VERSION 5.8 ;
BUSBITCHARS "[]" ;
DIVIDERCHAR "/" ;
UNITS
    DATABASE MICRONS 1000 ;
END UNITS

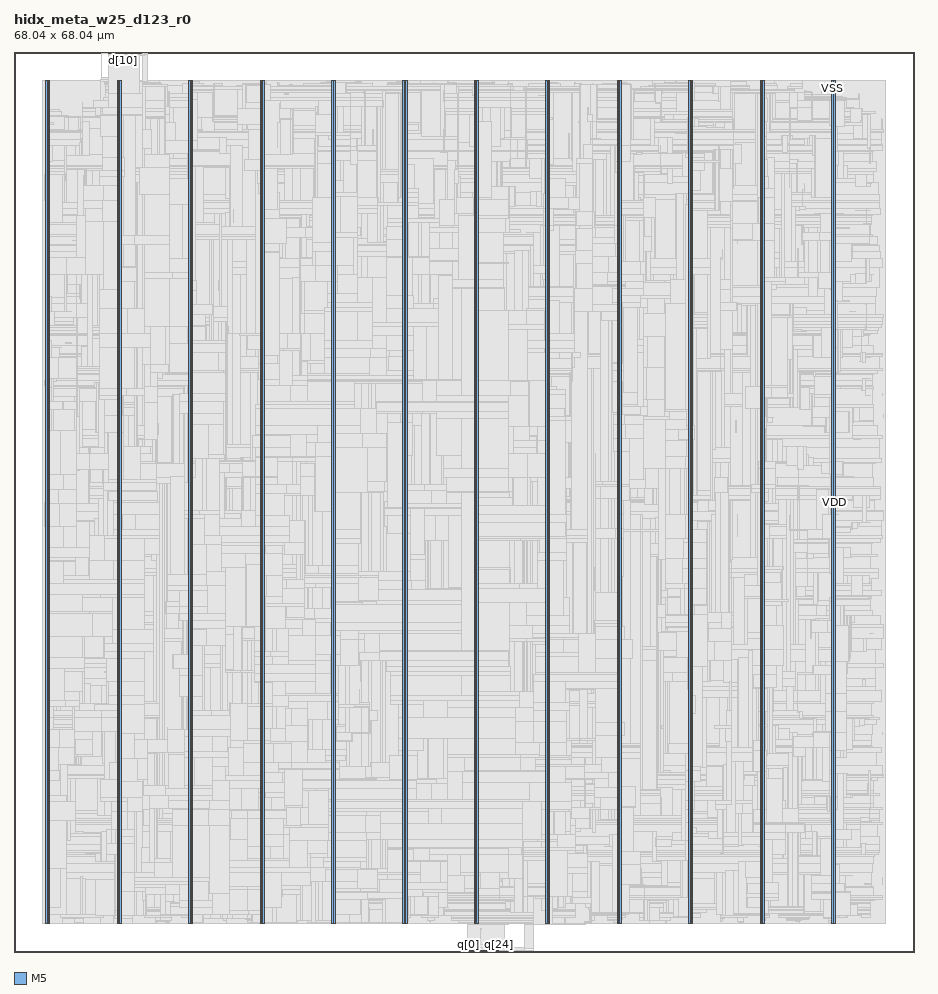
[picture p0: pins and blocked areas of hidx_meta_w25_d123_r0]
MACRO hidx_meta_w25_d123_r0
  FOREIGN hidx_meta_w25_d123_r0 0 0 ;
  CLASS BLOCK ;
  SIZE 68.04 BY 68.04 ;
  PIN clk
    DIRECTION INPUT ;
    USE SIGNAL ;
    PORT
      LAYER M5 ;
        RECT  7.152 67.956 7.176 68.04 ;
    END
  END clk
  PIN d[0]
    DIRECTION INPUT ;
    USE SIGNAL ;
    PORT
      LAYER M5 ;
        RECT  7.248 67.956 7.272 68.04 ;
    END
  END d[0]
  PIN d[10]
    DIRECTION INPUT ;
    USE SIGNAL ;
    PORT
      LAYER M5 ;
        RECT  8.208 67.956 8.232 68.04 ;
    END
  END d[10]
  PIN d[11]
    DIRECTION INPUT ;
    USE SIGNAL ;
    PORT
      LAYER M5 ;
        RECT  8.304 67.956 8.328 68.04 ;
    END
  END d[11]
  PIN d[12]
    DIRECTION INPUT ;
    USE SIGNAL ;
    PORT
      LAYER M5 ;
        RECT  8.4 67.956 8.424 68.04 ;
    END
  END d[12]
  PIN d[13]
    DIRECTION INPUT ;
    USE SIGNAL ;
    PORT
      LAYER M5 ;
        RECT  8.496 67.956 8.52 68.04 ;
    END
  END d[13]
  PIN d[14]
    DIRECTION INPUT ;
    USE SIGNAL ;
    PORT
      LAYER M5 ;
        RECT  8.592 67.956 8.616 68.04 ;
    END
  END d[14]
  PIN d[15]
    DIRECTION INPUT ;
    USE SIGNAL ;
    PORT
      LAYER M5 ;
        RECT  8.688 67.956 8.712 68.04 ;
    END
  END d[15]
  PIN d[16]
    DIRECTION INPUT ;
    USE SIGNAL ;
    PORT
      LAYER M5 ;
        RECT  8.784 67.956 8.808 68.04 ;
    END
  END d[16]
  PIN d[17]
    DIRECTION INPUT ;
    USE SIGNAL ;
    PORT
      LAYER M5 ;
        RECT  8.88 67.956 8.904 68.04 ;
    END
  END d[17]
  PIN d[18]
    DIRECTION INPUT ;
    USE SIGNAL ;
    PORT
      LAYER M5 ;
        RECT  8.976 67.956 9 68.04 ;
    END
  END d[18]
  PIN d[19]
    DIRECTION INPUT ;
    USE SIGNAL ;
    PORT
      LAYER M5 ;
        RECT  9.072 67.956 9.096 68.04 ;
    END
  END d[19]
  PIN d[1]
    DIRECTION INPUT ;
    USE SIGNAL ;
    PORT
      LAYER M5 ;
        RECT  7.344 67.956 7.368 68.04 ;
    END
  END d[1]
  PIN d[20]
    DIRECTION INPUT ;
    USE SIGNAL ;
    PORT
      LAYER M5 ;
        RECT  9.168 67.956 9.192 68.04 ;
    END
  END d[20]
  PIN d[21]
    DIRECTION INPUT ;
    USE SIGNAL ;
    PORT
      LAYER M5 ;
        RECT  9.264 67.956 9.288 68.04 ;
    END
  END d[21]
  PIN d[22]
    DIRECTION INPUT ;
    USE SIGNAL ;
    PORT
      LAYER M5 ;
        RECT  9.36 67.956 9.384 68.04 ;
    END
  END d[22]
  PIN d[23]
    DIRECTION INPUT ;
    USE SIGNAL ;
    PORT
      LAYER M5 ;
        RECT  9.456 67.956 9.48 68.04 ;
    END
  END d[23]
  PIN d[24]
    DIRECTION INPUT ;
    USE SIGNAL ;
    PORT
      LAYER M5 ;
        RECT  9.552 67.956 9.576 68.04 ;
    END
  END d[24]
  PIN d[2]
    DIRECTION INPUT ;
    USE SIGNAL ;
    PORT
      LAYER M5 ;
        RECT  7.44 67.956 7.464 68.04 ;
    END
  END d[2]
  PIN d[3]
    DIRECTION INPUT ;
    USE SIGNAL ;
    PORT
      LAYER M5 ;
        RECT  7.536 67.956 7.56 68.04 ;
    END
  END d[3]
  PIN d[4]
    DIRECTION INPUT ;
    USE SIGNAL ;
    PORT
      LAYER M5 ;
        RECT  7.632 67.956 7.656 68.04 ;
    END
  END d[4]
  PIN d[5]
    DIRECTION INPUT ;
    USE SIGNAL ;
    PORT
      LAYER M5 ;
        RECT  7.728 67.956 7.752 68.04 ;
    END
  END d[5]
  PIN d[6]
    DIRECTION INPUT ;
    USE SIGNAL ;
    PORT
      LAYER M5 ;
        RECT  7.824 67.956 7.848 68.04 ;
    END
  END d[6]
  PIN d[7]
    DIRECTION INPUT ;
    USE SIGNAL ;
    PORT
      LAYER M5 ;
        RECT  7.92 67.956 7.944 68.04 ;
    END
  END d[7]
  PIN d[8]
    DIRECTION INPUT ;
    USE SIGNAL ;
    PORT
      LAYER M5 ;
        RECT  8.016 67.956 8.04 68.04 ;
    END
  END d[8]
  PIN d[9]
    DIRECTION INPUT ;
    USE SIGNAL ;
    PORT
      LAYER M5 ;
        RECT  8.112 67.956 8.136 68.04 ;
    END
  END d[9]
  PIN q[0]
    DIRECTION OUTPUT ;
    USE SIGNAL ;
    PORT
      LAYER M5 ;
        RECT  34.32 0 34.344 0.084 ;
    END
  END q[0]
  PIN q[10]
    DIRECTION OUTPUT ;
    USE SIGNAL ;
    PORT
      LAYER M5 ;
        RECT  35.28 0 35.304 0.084 ;
    END
  END q[10]
  PIN q[11]
    DIRECTION OUTPUT ;
    USE SIGNAL ;
    PORT
      LAYER M5 ;
        RECT  35.376 0 35.4 0.084 ;
    END
  END q[11]
  PIN q[12]
    DIRECTION OUTPUT ;
    USE SIGNAL ;
    PORT
      LAYER M5 ;
        RECT  35.472 0 35.496 0.084 ;
    END
  END q[12]
  PIN q[13]
    DIRECTION OUTPUT ;
    USE SIGNAL ;
    PORT
      LAYER M5 ;
        RECT  35.568 0 35.592 0.084 ;
    END
  END q[13]
  PIN q[14]
    DIRECTION OUTPUT ;
    USE SIGNAL ;
    PORT
      LAYER M5 ;
        RECT  35.664 0 35.688 0.084 ;
    END
  END q[14]
  PIN q[15]
    DIRECTION OUTPUT ;
    USE SIGNAL ;
    PORT
      LAYER M5 ;
        RECT  35.76 0 35.784 0.084 ;
    END
  END q[15]
  PIN q[16]
    DIRECTION OUTPUT ;
    USE SIGNAL ;
    PORT
      LAYER M5 ;
        RECT  35.856 0 35.88 0.084 ;
    END
  END q[16]
  PIN q[17]
    DIRECTION OUTPUT ;
    USE SIGNAL ;
    PORT
      LAYER M5 ;
        RECT  35.952 0 35.976 0.084 ;
    END
  END q[17]
  PIN q[18]
    DIRECTION OUTPUT ;
    USE SIGNAL ;
    PORT
      LAYER M5 ;
        RECT  36.048 0 36.072 0.084 ;
    END
  END q[18]
  PIN q[19]
    DIRECTION OUTPUT ;
    USE SIGNAL ;
    PORT
      LAYER M5 ;
        RECT  36.144 0 36.168 0.084 ;
    END
  END q[19]
  PIN q[1]
    DIRECTION OUTPUT ;
    USE SIGNAL ;
    PORT
      LAYER M5 ;
        RECT  34.416 0 34.44 0.084 ;
    END
  END q[1]
  PIN q[20]
    DIRECTION OUTPUT ;
    USE SIGNAL ;
    PORT
      LAYER M5 ;
        RECT  36.24 0 36.264 0.084 ;
    END
  END q[20]
  PIN q[21]
    DIRECTION OUTPUT ;
    USE SIGNAL ;
    PORT
      LAYER M5 ;
        RECT  36.336 0 36.36 0.084 ;
    END
  END q[21]
  PIN q[22]
    DIRECTION OUTPUT ;
    USE SIGNAL ;
    PORT
      LAYER M5 ;
        RECT  36.432 0 36.456 0.084 ;
    END
  END q[22]
  PIN q[23]
    DIRECTION OUTPUT ;
    USE SIGNAL ;
    PORT
      LAYER M5 ;
        RECT  36.528 0 36.552 0.084 ;
    END
  END q[23]
  PIN q[24]
    DIRECTION OUTPUT ;
    USE SIGNAL ;
    PORT
      LAYER M5 ;
        RECT  36.624 0 36.648 0.084 ;
    END
  END q[24]
  PIN q[2]
    DIRECTION OUTPUT ;
    USE SIGNAL ;
    PORT
      LAYER M5 ;
        RECT  34.512 0 34.536 0.084 ;
    END
  END q[2]
  PIN q[3]
    DIRECTION OUTPUT ;
    USE SIGNAL ;
    PORT
      LAYER M5 ;
        RECT  34.608 0 34.632 0.084 ;
    END
  END q[3]
  PIN q[4]
    DIRECTION OUTPUT ;
    USE SIGNAL ;
    PORT
      LAYER M5 ;
        RECT  34.704 0 34.728 0.084 ;
    END
  END q[4]
  PIN q[5]
    DIRECTION OUTPUT ;
    USE SIGNAL ;
    PORT
      LAYER M5 ;
        RECT  34.8 0 34.824 0.084 ;
    END
  END q[5]
  PIN q[6]
    DIRECTION OUTPUT ;
    USE SIGNAL ;
    PORT
      LAYER M5 ;
        RECT  34.896 0 34.92 0.084 ;
    END
  END q[6]
  PIN q[7]
    DIRECTION OUTPUT ;
    USE SIGNAL ;
    PORT
      LAYER M5 ;
        RECT  34.992 0 35.016 0.084 ;
    END
  END q[7]
  PIN q[8]
    DIRECTION OUTPUT ;
    USE SIGNAL ;
    PORT
      LAYER M5 ;
        RECT  35.088 0 35.112 0.084 ;
    END
  END q[8]
  PIN q[9]
    DIRECTION OUTPUT ;
    USE SIGNAL ;
    PORT
      LAYER M5 ;
        RECT  35.184 0 35.208 0.084 ;
    END
  END q[9]
  PIN rst_n
    DIRECTION INPUT ;
    USE SIGNAL ;
    PORT
      LAYER M5 ;
        RECT  9.648 67.956 9.672 68.04 ;
    END
  END rst_n
  PIN VDD
    DIRECTION INOUT ;
    USE POWER ;
    PORT
      LAYER M5 ;
        RECT  61.992 2.151 62.112 65.889 ;
        RECT  56.592 2.151 56.712 65.889 ;
        RECT  51.192 2.151 51.312 65.889 ;
        RECT  45.792 2.151 45.912 65.889 ;
        RECT  40.392 2.151 40.512 65.889 ;
        RECT  34.992 2.151 35.112 65.889 ;
        RECT  29.592 2.151 29.712 65.889 ;
        RECT  24.192 2.151 24.312 65.889 ;
        RECT  18.792 2.151 18.912 65.889 ;
        RECT  13.392 2.151 13.512 65.889 ;
        RECT  7.992 2.151 8.112 65.889 ;
        RECT  2.592 2.151 2.712 65.889 ;
    END
  END VDD
  PIN VSS
    DIRECTION INOUT ;
    USE GROUND ;
    PORT
      LAYER M5 ;
        RECT  61.8 2.137 61.92 65.903 ;
        RECT  56.4 2.137 56.52 65.903 ;
        RECT  51 2.137 51.12 65.903 ;
        RECT  45.6 2.137 45.72 65.903 ;
        RECT  40.2 2.137 40.32 65.903 ;
        RECT  34.8 2.137 34.92 65.903 ;
        RECT  29.4 2.137 29.52 65.903 ;
        RECT  24 2.137 24.12 65.903 ;
        RECT  18.6 2.137 18.72 65.903 ;
        RECT  13.2 2.137 13.32 65.903 ;
        RECT  7.8 2.137 7.92 65.903 ;
        RECT  2.4 2.137 2.52 65.903 ;
    END
  END VSS
  # OT_OBS_CLOSED layer=M5 d_um=1.536 added=598
  OBS
    LAYER RVTN ;
     RECT  2.16 2.16 65.88 2.295 ;
     RECT  2.16 2.565 65.88 2.835 ;
     RECT  2.16 3.105 65.88 3.375 ;
     RECT  2.16 3.645 65.88 3.915 ;
     RECT  2.16 4.185 65.88 4.455 ;
     RECT  2.16 4.725 65.88 4.995 ;
     RECT  2.16 5.265 65.88 5.535 ;
     RECT  2.16 5.805 65.88 6.075 ;
     RECT  2.16 6.345 65.88 6.615 ;
     RECT  2.16 6.885 65.88 7.155 ;
     RECT  2.16 7.425 65.88 7.695 ;
     RECT  2.16 7.965 65.88 8.235 ;
     RECT  2.16 8.505 65.88 8.775 ;
     RECT  2.16 9.045 65.88 9.315 ;
     RECT  2.16 9.585 65.88 9.855 ;
     RECT  2.16 10.125 65.88 10.395 ;
     RECT  2.16 10.665 65.88 10.935 ;
     RECT  2.16 11.205 65.88 11.475 ;
     RECT  2.16 11.745 65.88 12.015 ;
     RECT  2.16 12.285 65.88 12.555 ;
     RECT  2.16 12.825 65.88 13.095 ;
     RECT  2.16 13.365 65.88 13.635 ;
     RECT  2.16 13.905 65.88 14.175 ;
     RECT  2.16 14.445 65.88 14.715 ;
     RECT  2.16 14.985 65.88 15.255 ;
     RECT  2.16 15.525 65.88 15.795 ;
     RECT  2.16 16.065 65.88 16.335 ;
     RECT  2.16 16.605 65.88 16.875 ;
     RECT  2.16 17.145 65.88 17.415 ;
     RECT  2.16 17.685 65.88 17.955 ;
     RECT  2.16 18.225 65.88 18.495 ;
     RECT  2.16 18.765 65.88 19.035 ;
     RECT  2.16 19.305 65.88 19.575 ;
     RECT  2.16 19.845 65.88 20.115 ;
     RECT  2.16 20.385 65.88 20.655 ;
     RECT  2.16 20.925 65.88 21.195 ;
     RECT  2.16 21.465 65.88 21.735 ;
     RECT  2.16 22.005 65.88 22.275 ;
     RECT  2.16 22.545 65.88 22.815 ;
     RECT  2.16 23.085 65.88 23.355 ;
     RECT  2.16 23.625 65.88 23.895 ;
     RECT  2.16 24.165 65.88 24.435 ;
     RECT  2.16 24.705 65.88 24.975 ;
     RECT  2.16 25.245 65.88 25.515 ;
     RECT  2.16 25.785 65.88 26.055 ;
     RECT  2.16 26.325 65.88 26.595 ;
     RECT  2.16 26.865 65.88 27.135 ;
     RECT  2.16 27.405 65.88 27.675 ;
     RECT  2.16 27.945 65.88 28.215 ;
     RECT  2.16 28.485 65.88 28.755 ;
     RECT  2.16 29.025 65.88 29.295 ;
     RECT  2.16 29.565 65.88 29.835 ;
     RECT  2.16 30.105 65.88 30.375 ;
     RECT  2.16 30.645 65.88 30.915 ;
     RECT  2.16 31.185 65.88 31.455 ;
     RECT  2.16 31.725 65.88 31.995 ;
     RECT  2.16 32.265 65.88 32.535 ;
     RECT  2.16 32.805 65.88 33.075 ;
     RECT  2.16 33.345 65.88 33.615 ;
     RECT  2.16 33.885 65.88 34.155 ;
     RECT  2.16 34.425 65.88 34.695 ;
     RECT  2.16 34.965 65.88 35.235 ;
     RECT  2.16 35.505 65.88 35.775 ;
     RECT  2.16 36.045 65.88 36.315 ;
     RECT  2.16 36.585 65.88 36.855 ;
     RECT  2.16 37.125 65.88 37.395 ;
     RECT  2.16 37.665 65.88 37.935 ;
     RECT  2.16 38.205 65.88 38.475 ;
     RECT  2.16 38.745 65.88 39.015 ;
     RECT  2.16 39.285 65.88 39.555 ;
     RECT  2.16 39.825 65.88 40.095 ;
     RECT  2.16 40.365 65.88 40.635 ;
     RECT  2.16 40.905 65.88 41.175 ;
     RECT  2.16 41.445 65.88 41.715 ;
     RECT  2.16 41.985 65.88 42.255 ;
     RECT  2.16 42.525 65.88 42.795 ;
     RECT  2.16 43.065 65.88 43.335 ;
     RECT  2.16 43.605 65.88 43.875 ;
     RECT  2.16 44.145 65.88 44.415 ;
     RECT  2.16 44.685 65.88 44.955 ;
     RECT  2.16 45.225 65.88 45.495 ;
     RECT  2.16 45.765 65.88 46.035 ;
     RECT  2.16 46.305 65.88 46.575 ;
     RECT  2.16 46.845 65.88 47.115 ;
     RECT  2.16 47.385 65.88 47.655 ;
     RECT  2.16 47.925 65.88 48.195 ;
     RECT  2.16 48.465 65.88 48.735 ;
     RECT  2.16 49.005 65.88 49.275 ;
     RECT  2.16 49.545 65.88 49.815 ;
     RECT  2.16 50.085 65.88 50.355 ;
     RECT  2.16 50.625 65.88 50.895 ;
     RECT  2.16 51.165 65.88 51.435 ;
     RECT  2.16 51.705 65.88 51.975 ;
     RECT  2.16 52.245 65.88 52.515 ;
     RECT  2.16 52.785 65.88 53.055 ;
     RECT  2.16 53.325 65.88 53.595 ;
     RECT  2.16 53.865 65.88 54.135 ;
     RECT  2.16 54.405 65.88 54.675 ;
     RECT  2.16 54.945 65.88 55.215 ;
     RECT  2.16 55.485 65.88 55.755 ;
     RECT  2.16 56.025 65.88 56.295 ;
     RECT  2.16 56.565 65.88 56.835 ;
     RECT  2.16 57.105 65.88 57.375 ;
     RECT  2.16 57.645 65.88 57.915 ;
     RECT  2.16 58.185 65.88 58.455 ;
     RECT  2.16 58.725 65.88 58.995 ;
     RECT  2.16 59.265 65.88 59.535 ;
     RECT  2.16 59.805 65.88 60.075 ;
     RECT  2.16 60.345 65.88 60.615 ;
     RECT  2.16 60.885 65.88 61.155 ;
     RECT  2.16 61.425 65.88 61.695 ;
     RECT  2.16 61.965 65.88 62.235 ;
     RECT  2.16 62.505 65.88 62.775 ;
     RECT  2.16 63.045 65.88 63.315 ;
     RECT  2.16 63.585 65.88 63.855 ;
     RECT  2.16 64.125 65.88 64.395 ;
     RECT  2.16 64.665 65.88 64.935 ;
     RECT  2.16 65.205 65.88 65.475 ;
     RECT  2.16 65.745 65.88 65.88 ;
    LAYER RVTP ;
     RECT  2.16 2.295 65.88 2.565 ;
     RECT  2.16 2.835 65.88 3.105 ;
     RECT  2.16 3.375 65.88 3.645 ;
     RECT  2.16 3.915 65.88 4.185 ;
     RECT  2.16 4.455 65.88 4.725 ;
     RECT  2.16 4.995 65.88 5.265 ;
     RECT  2.16 5.535 65.88 5.805 ;
     RECT  2.16 6.075 65.88 6.345 ;
     RECT  2.16 6.615 65.88 6.885 ;
     RECT  2.16 7.155 65.88 7.425 ;
     RECT  2.16 7.695 65.88 7.965 ;
     RECT  2.16 8.235 65.88 8.505 ;
     RECT  2.16 8.775 65.88 9.045 ;
     RECT  2.16 9.315 65.88 9.585 ;
     RECT  2.16 9.855 65.88 10.125 ;
     RECT  2.16 10.395 65.88 10.665 ;
     RECT  2.16 10.935 65.88 11.205 ;
     RECT  2.16 11.475 65.88 11.745 ;
     RECT  2.16 12.015 65.88 12.285 ;
     RECT  2.16 12.555 65.88 12.825 ;
     RECT  2.16 13.095 65.88 13.365 ;
     RECT  2.16 13.635 65.88 13.905 ;
     RECT  2.16 14.175 65.88 14.445 ;
     RECT  2.16 14.715 65.88 14.985 ;
     RECT  2.16 15.255 65.88 15.525 ;
     RECT  2.16 15.795 65.88 16.065 ;
     RECT  2.16 16.335 65.88 16.605 ;
     RECT  2.16 16.875 65.88 17.145 ;
     RECT  2.16 17.415 65.88 17.685 ;
     RECT  2.16 17.955 65.88 18.225 ;
     RECT  2.16 18.495 65.88 18.765 ;
     RECT  2.16 19.035 65.88 19.305 ;
     RECT  2.16 19.575 65.88 19.845 ;
     RECT  2.16 20.115 65.88 20.385 ;
     RECT  2.16 20.655 65.88 20.925 ;
     RECT  2.16 21.195 65.88 21.465 ;
     RECT  2.16 21.735 65.88 22.005 ;
     RECT  2.16 22.275 65.88 22.545 ;
     RECT  2.16 22.815 65.88 23.085 ;
     RECT  2.16 23.355 65.88 23.625 ;
     RECT  2.16 23.895 65.88 24.165 ;
     RECT  2.16 24.435 65.88 24.705 ;
     RECT  2.16 24.975 65.88 25.245 ;
     RECT  2.16 25.515 65.88 25.785 ;
     RECT  2.16 26.055 65.88 26.325 ;
     RECT  2.16 26.595 65.88 26.865 ;
     RECT  2.16 27.135 65.88 27.405 ;
     RECT  2.16 27.675 65.88 27.945 ;
     RECT  2.16 28.215 65.88 28.485 ;
     RECT  2.16 28.755 65.88 29.025 ;
     RECT  2.16 29.295 65.88 29.565 ;
     RECT  2.16 29.835 65.88 30.105 ;
     RECT  2.16 30.375 65.88 30.645 ;
     RECT  2.16 30.915 65.88 31.185 ;
     RECT  2.16 31.455 65.88 31.725 ;
     RECT  2.16 31.995 65.88 32.265 ;
     RECT  2.16 32.535 65.88 32.805 ;
     RECT  2.16 33.075 65.88 33.345 ;
     RECT  2.16 33.615 65.88 33.885 ;
     RECT  2.16 34.155 65.88 34.425 ;
     RECT  2.16 34.695 65.88 34.965 ;
     RECT  2.16 35.235 65.88 35.505 ;
     RECT  2.16 35.775 65.88 36.045 ;
     RECT  2.16 36.315 65.88 36.585 ;
     RECT  2.16 36.855 65.88 37.125 ;
     RECT  2.16 37.395 65.88 37.665 ;
     RECT  2.16 37.935 65.88 38.205 ;
     RECT  2.16 38.475 65.88 38.745 ;
     RECT  2.16 39.015 65.88 39.285 ;
     RECT  2.16 39.555 65.88 39.825 ;
     RECT  2.16 40.095 65.88 40.365 ;
     RECT  2.16 40.635 65.88 40.905 ;
     RECT  2.16 41.175 65.88 41.445 ;
     RECT  2.16 41.715 65.88 41.985 ;
     RECT  2.16 42.255 65.88 42.525 ;
     RECT  2.16 42.795 65.88 43.065 ;
     RECT  2.16 43.335 65.88 43.605 ;
     RECT  2.16 43.875 65.88 44.145 ;
     RECT  2.16 44.415 65.88 44.685 ;
     RECT  2.16 44.955 65.88 45.225 ;
     RECT  2.16 45.495 65.88 45.765 ;
     RECT  2.16 46.035 65.88 46.305 ;
     RECT  2.16 46.575 65.88 46.845 ;
     RECT  2.16 47.115 65.88 47.385 ;
     RECT  2.16 47.655 65.88 47.925 ;
     RECT  2.16 48.195 65.88 48.465 ;
     RECT  2.16 48.735 65.88 49.005 ;
     RECT  2.16 49.275 65.88 49.545 ;
     RECT  2.16 49.815 65.88 50.085 ;
     RECT  2.16 50.355 65.88 50.625 ;
     RECT  2.16 50.895 65.88 51.165 ;
     RECT  2.16 51.435 65.88 51.705 ;
     RECT  2.16 51.975 65.88 52.245 ;
     RECT  2.16 52.515 65.88 52.785 ;
     RECT  2.16 53.055 65.88 53.325 ;
     RECT  2.16 53.595 65.88 53.865 ;
     RECT  2.16 54.135 65.88 54.405 ;
     RECT  2.16 54.675 65.88 54.945 ;
     RECT  2.16 55.215 65.88 55.485 ;
     RECT  2.16 55.755 65.88 56.025 ;
     RECT  2.16 56.295 65.88 56.565 ;
     RECT  2.16 56.835 65.88 57.105 ;
     RECT  2.16 57.375 65.88 57.645 ;
     RECT  2.16 57.915 65.88 58.185 ;
     RECT  2.16 58.455 65.88 58.725 ;
     RECT  2.16 58.995 65.88 59.265 ;
     RECT  2.16 59.535 65.88 59.805 ;
     RECT  2.16 60.075 65.88 60.345 ;
     RECT  2.16 60.615 65.88 60.885 ;
     RECT  2.16 61.155 65.88 61.425 ;
     RECT  2.16 61.695 65.88 61.965 ;
     RECT  2.16 62.235 65.88 62.505 ;
     RECT  2.16 62.775 65.88 63.045 ;
     RECT  2.16 63.315 65.88 63.585 ;
     RECT  2.16 63.855 65.88 64.125 ;
     RECT  2.16 64.395 65.88 64.665 ;
     RECT  2.16 64.935 65.88 65.205 ;
     RECT  2.16 65.475 65.88 65.745 ;
    LAYER M1 ;
     RECT  2.16 2.151 65.88 65.889 ;
    LAYER M2 ;
     RECT  2.16 2.151 6.547 65.889 ;
     RECT  6.547 2.151 7.511 65.934 ;
     RECT  34.447 0.531 34.547 0.549 ;
     RECT  7.511 2.151 36.211 65.889 ;
     RECT  36.211 2.106 37.355 65.889 ;
     RECT  37.355 2.151 65.88 65.889 ;
    LAYER M3 ;
     RECT  34.344 0.091 36.27 0.187 ;
     RECT  37.044 0.139 37.062 0.187 ;
     RECT  39.24 0.091 39.258 0.283 ;
     RECT  34.344 0.187 37.062 0.475 ;
     RECT  38.592 0.283 39.258 2.059 ;
     RECT  34.308 0.475 37.062 2.101 ;
     RECT  7.815 2.143 7.905 2.191 ;
     RECT  18.615 2.143 18.705 2.191 ;
     RECT  34.308 2.101 37.35 2.191 ;
     RECT  38.592 2.059 39.33 2.191 ;
     RECT  40.215 2.143 40.305 2.191 ;
     RECT  43.164 2.059 43.182 2.191 ;
     RECT  5.256 2.191 5.274 2.227 ;
     RECT  11.736 2.191 11.754 2.227 ;
     RECT  22.68 2.191 22.698 2.227 ;
     RECT  24.015 2.143 24.105 2.227 ;
     RECT  38.592 2.191 40.305 2.227 ;
     RECT  45.615 2.143 45.705 2.227 ;
     RECT  13.215 2.143 13.305 2.251 ;
     RECT  21.42 2.227 21.438 2.251 ;
     RECT  22.212 2.227 22.698 2.251 ;
     RECT  23.508 2.227 24.105 2.251 ;
     RECT  18.036 2.191 18.705 2.263 ;
     RECT  21.312 2.251 21.438 2.263 ;
     RECT  25.092 2.251 25.11 2.263 ;
     RECT  26.676 2.251 26.694 2.263 ;
     RECT  27.576 2.251 27.594 2.263 ;
     RECT  33.624 2.191 37.35 2.263 ;
     RECT  38.556 2.227 40.305 2.263 ;
     RECT  61.815 2.143 61.905 2.263 ;
     RECT  43.164 2.191 43.578 2.291 ;
     RECT  10.728 2.227 10.746 2.299 ;
     RECT  11.484 2.227 11.754 2.299 ;
     RECT  13.215 2.251 13.842 2.299 ;
     RECT  26.676 2.263 27.738 2.335 ;
     RECT  29.415 2.143 29.505 2.335 ;
     RECT  31.5 2.263 31.518 2.335 ;
     RECT  54.792 2.227 55.17 2.335 ;
     RECT  59.4 2.263 59.418 2.335 ;
     RECT  10.728 2.299 11.754 2.371 ;
     RECT  16.056 2.263 16.074 2.371 ;
     RECT  17.676 2.263 19.314 2.371 ;
     RECT  26.676 2.335 27.846 2.371 ;
     RECT  31.428 2.335 31.518 2.371 ;
     RECT  33.624 2.263 40.305 2.371 ;
     RECT  41.652 2.263 41.67 2.371 ;
     RECT  43.488 2.291 43.578 2.371 ;
     RECT  45.324 2.227 45.705 2.371 ;
     RECT  48.06 2.191 48.078 2.371 ;
     RECT  49.284 2.191 49.302 2.371 ;
     RECT  56.415 2.143 56.505 2.371 ;
     RECT  59.112 2.335 59.418 2.371 ;
     RECT  2.415 2.143 2.505 2.413 ;
     RECT  22.212 2.251 24.105 2.413 ;
     RECT  24.912 2.263 25.182 2.413 ;
     RECT  33.084 2.371 40.305 2.413 ;
     RECT  44.892 2.371 45.705 2.413 ;
     RECT  51.015 2.143 51.105 2.413 ;
     RECT  61.56 2.263 61.974 2.413 ;
     RECT  13.215 2.299 14.202 2.461 ;
     RECT  17.676 2.371 19.53 2.461 ;
     RECT  20.268 2.371 20.286 2.461 ;
     RECT  21.132 2.263 21.438 2.461 ;
     RECT  26.208 2.371 27.846 2.461 ;
     RECT  44.892 2.413 45.897 2.461 ;
     RECT  58.392 2.371 59.562 2.461 ;
     RECT  17.676 2.461 21.438 2.488 ;
     RECT  58.392 2.461 60.102 2.497 ;
     RECT  61.56 2.413 62.097 2.497 ;
     RECT  3.636 2.191 3.654 2.533 ;
     RECT  4.572 2.227 5.274 2.533 ;
     RECT  7.815 2.191 8.982 2.533 ;
     RECT  15.84 2.371 16.074 2.533 ;
     RECT  53.424 2.335 53.55 2.533 ;
     RECT  17.496 2.488 21.438 2.569 ;
     RECT  33.084 2.413 40.497 2.569 ;
     RECT  61.2 2.497 62.097 2.587 ;
     RECT  13.176 2.461 14.202 2.605 ;
     RECT  15.732 2.533 16.074 2.605 ;
     RECT  17.424 2.569 21.438 2.605 ;
     RECT  22.212 2.413 25.182 2.605 ;
     RECT  26.172 2.461 27.846 2.605 ;
     RECT  31.284 2.371 31.77 2.605 ;
     RECT  33.048 2.569 40.497 2.605 ;
     RECT  41.616 2.371 41.67 2.605 ;
     RECT  47.304 2.371 49.626 2.605 ;
     RECT  51.015 2.413 51.297 2.605 ;
     RECT  53.424 2.533 53.73 2.605 ;
     RECT  54.684 2.335 55.17 2.605 ;
     RECT  56.415 2.371 56.79 2.605 ;
     RECT  58.392 2.497 60.174 2.605 ;
     RECT  3.636 2.533 5.274 2.641 ;
     RECT  6.732 2.605 6.75 2.641 ;
     RECT  9.9 2.605 9.918 2.641 ;
     RECT  10.728 2.371 11.934 2.641 ;
     RECT  15.732 2.605 16.182 2.641 ;
     RECT  17.424 2.605 25.182 2.641 ;
     RECT  26.1 2.605 27.846 2.641 ;
     RECT  29.415 2.335 29.79 2.641 ;
     RECT  31.284 2.605 32.058 2.641 ;
     RECT  33.048 2.605 40.662 2.641 ;
     RECT  41.436 2.605 41.742 2.641 ;
     RECT  44.892 2.461 45.99 2.641 ;
     RECT  47.304 2.605 50.058 2.641 ;
     RECT  51.015 2.605 51.93 2.641 ;
     RECT  53.424 2.605 55.17 2.641 ;
     RECT  56.415 2.605 56.898 2.641 ;
     RECT  58.284 2.605 60.174 2.641 ;
     RECT  61.2 2.587 62.262 2.641 ;
     RECT  63 2.587 63.018 2.641 ;
     RECT  64.044 2.605 64.062 2.641 ;
     RECT  30.78 2.641 32.058 2.731 ;
     RECT  33.048 2.641 42.426 2.731 ;
     RECT  43.488 2.371 43.902 2.731 ;
     RECT  44.856 2.641 46.206 2.731 ;
     RECT  53.424 2.641 55.458 2.731 ;
     RECT  56.415 2.641 57.078 2.731 ;
     RECT  57.816 2.641 60.174 2.731 ;
     RECT  61.2 2.641 63.018 2.731 ;
     RECT  9.9 2.641 11.934 2.767 ;
     RECT  12.672 2.605 14.742 2.767 ;
     RECT  15.48 2.641 16.326 2.767 ;
     RECT  17.424 2.641 27.846 2.767 ;
     RECT  29.376 2.641 30.006 2.767 ;
     RECT  30.78 2.731 42.426 2.767 ;
     RECT  2.415 2.413 2.697 2.803 ;
     RECT  3.492 2.641 6.75 2.803 ;
     RECT  43.488 2.731 46.206 2.803 ;
     RECT  53.424 2.731 57.078 2.803 ;
     RECT  57.816 2.731 63.018 2.803 ;
     RECT  64.044 2.641 64.746 2.803 ;
     RECT  2.415 2.803 6.75 2.911 ;
     RECT  7.632 2.533 8.982 2.911 ;
     RECT  43.488 2.803 46.422 2.911 ;
     RECT  47.304 2.641 51.93 2.911 ;
     RECT  53.1 2.803 57.078 2.911 ;
     RECT  57.816 2.803 64.746 2.911 ;
     RECT  43.488 2.911 51.93 3.001 ;
     RECT  7.632 2.911 9.09 3.037 ;
     RECT  9.9 2.767 16.326 3.037 ;
     RECT  17.424 2.767 28.458 3.037 ;
     RECT  17.172 3.037 28.458 3.064 ;
     RECT  29.196 2.767 42.426 3.064 ;
     RECT  7.632 3.037 16.326 3.145 ;
     RECT  17.172 3.064 42.426 3.145 ;
     RECT  53.1 2.911 64.746 3.145 ;
     RECT  2.415 2.911 6.894 3.181 ;
     RECT  7.632 3.145 42.426 3.181 ;
     RECT  43.488 3.001 52.362 3.181 ;
     RECT  53.1 3.145 64.782 3.181 ;
     RECT  43.452 3.181 64.782 3.379 ;
     RECT  2.415 3.181 42.426 3.685 ;
     RECT  43.236 3.379 64.782 3.685 ;
     RECT  2.415 3.685 64.782 3.749 ;
     RECT  2.415 3.749 12.114 3.839 ;
     RECT  12.888 3.749 64.782 3.883 ;
     RECT  12.888 3.883 65.034 3.991 ;
     RECT  12.888 3.991 65.682 4.109 ;
     RECT  13.032 4.109 65.682 4.253 ;
     RECT  2.415 3.839 12.078 4.891 ;
     RECT  13.032 4.253 64.998 4.891 ;
     RECT  2.415 4.891 64.998 4.919 ;
     RECT  65.664 5.071 65.682 5.603 ;
     RECT  2.415 4.919 64.854 6.043 ;
     RECT  2.415 6.043 64.89 6.691 ;
     RECT  2.415 6.691 64.998 7.231 ;
     RECT  2.415 7.231 65.034 7.393 ;
     RECT  2.415 7.393 65.358 7.501 ;
     RECT  2.415 7.501 65.43 7.699 ;
     RECT  2.415 7.699 65.466 8.159 ;
     RECT  2.415 8.159 65.43 8.699 ;
     RECT  2.415 8.699 65.25 8.735 ;
     RECT  60.3 8.735 65.25 9.625 ;
     RECT  2.415 8.735 59.526 9.643 ;
     RECT  60.264 9.625 65.25 9.643 ;
     RECT  2.415 9.643 65.25 9.661 ;
     RECT  2.415 9.661 65.682 9.815 ;
     RECT  2.415 9.815 65.466 9.931 ;
     RECT  2.376 9.931 65.466 10.109 ;
     RECT  2.415 10.109 65.466 10.445 ;
     RECT  55.872 10.445 65.466 10.741 ;
     RECT  55.872 10.741 65.682 10.931 ;
     RECT  2.415 10.445 55.098 11.209 ;
     RECT  55.872 10.931 64.962 11.209 ;
     RECT  2.415 11.209 64.962 11.821 ;
     RECT  2.415 11.821 65.43 11.975 ;
     RECT  2.415 11.975 64.998 12.209 ;
     RECT  2.415 12.209 55.17 12.631 ;
     RECT  55.98 12.209 64.998 12.991 ;
     RECT  2.376 12.631 55.17 13.063 ;
     RECT  55.98 12.991 65.286 13.171 ;
     RECT  2.376 13.063 55.206 13.369 ;
     RECT  55.98 13.171 65.754 13.369 ;
     RECT  2.376 13.369 65.754 13.433 ;
     RECT  2.376 13.433 65.646 14.099 ;
     RECT  2.415 14.099 65.574 14.135 ;
     RECT  2.415 14.135 65.178 15.061 ;
     RECT  2.415 15.061 65.574 15.448 ;
     RECT  2.412 15.448 65.574 15.485 ;
     RECT  2.415 15.485 64.89 15.521 ;
     RECT  2.415 15.521 64.854 15.629 ;
     RECT  2.415 15.629 64.818 16.411 ;
     RECT  65.664 16.411 65.682 16.601 ;
     RECT  2.415 16.411 64.89 17.185 ;
     RECT  2.415 17.185 65.178 17.581 ;
     RECT  2.415 17.581 65.43 17.753 ;
     RECT  2.415 17.753 64.998 17.879 ;
     RECT  2.415 17.879 64.818 18.769 ;
     RECT  2.415 18.769 64.962 18.931 ;
     RECT  2.415 18.931 65.61 19.769 ;
     RECT  2.415 19.769 65.502 19.805 ;
     RECT  2.415 19.805 65.106 20.047 ;
     RECT  2.376 20.047 65.106 20.651 ;
     RECT  2.415 20.651 65.106 21.541 ;
     RECT  2.415 21.541 65.754 21.803 ;
     RECT  2.415 21.803 65.106 22.891 ;
     RECT  2.415 22.891 65.574 23.701 ;
     RECT  2.415 23.701 65.754 24.539 ;
     RECT  2.415 24.539 58.194 24.629 ;
     RECT  58.932 24.539 65.754 24.773 ;
     RECT  2.415 24.629 58.086 24.907 ;
     RECT  2.412 24.907 58.086 24.944 ;
     RECT  58.932 24.773 65.502 25.439 ;
     RECT  2.415 24.944 58.086 25.447 ;
     RECT  58.932 25.439 60.678 25.447 ;
     RECT  61.416 25.439 65.502 25.475 ;
     RECT  61.416 25.475 64.926 25.853 ;
     RECT  2.415 25.447 60.678 26.221 ;
     RECT  61.416 25.853 64.746 26.221 ;
     RECT  2.415 26.221 64.746 26.671 ;
     RECT  2.415 26.671 64.782 26.761 ;
     RECT  2.415 26.761 64.818 26.897 ;
     RECT  2.415 26.897 59.13 26.905 ;
     RECT  59.868 26.897 64.818 26.941 ;
     RECT  59.868 26.941 65.574 27.329 ;
     RECT  59.868 27.329 65.43 27.365 ;
     RECT  2.376 26.905 59.13 27.679 ;
     RECT  59.868 27.365 64.818 27.679 ;
     RECT  2.376 27.679 64.818 28.255 ;
     RECT  2.376 28.255 65.322 28.679 ;
     RECT  2.415 28.679 65.322 28.985 ;
     RECT  2.415 28.985 64.746 29.911 ;
     RECT  2.415 29.911 65.286 30.065 ;
     RECT  2.415 30.065 64.854 30.919 ;
     RECT  2.415 30.919 64.926 30.991 ;
     RECT  2.415 30.991 65.502 31.261 ;
     RECT  2.415 31.261 65.682 31.523 ;
     RECT  2.415 31.523 65.61 32.197 ;
     RECT  2.34 32.197 65.61 32.611 ;
     RECT  2.34 32.611 65.754 33.269 ;
     RECT  52.524 33.269 65.754 33.413 ;
     RECT  2.34 33.269 51.642 33.989 ;
     RECT  2.376 33.989 51.642 34.087 ;
     RECT  2.376 34.087 51.75 34.159 ;
     RECT  52.524 33.413 65.07 34.159 ;
     RECT  2.376 34.159 65.07 34.231 ;
     RECT  2.376 34.231 65.502 34.493 ;
     RECT  2.415 34.493 65.502 35.041 ;
     RECT  2.415 35.041 65.538 35.195 ;
     RECT  2.415 35.195 64.998 35.843 ;
     RECT  2.415 35.843 64.926 36.931 ;
     RECT  2.415 36.931 65.142 37.021 ;
     RECT  2.415 37.021 65.574 37.319 ;
     RECT  2.415 37.319 65.43 38.155 ;
     RECT  2.376 38.155 65.43 38.821 ;
     RECT  2.376 38.821 65.682 39.083 ;
     RECT  2.376 39.083 65.286 39.773 ;
     RECT  2.415 39.773 65.286 39.785 ;
     RECT  65.736 40.441 65.754 40.631 ;
     RECT  2.415 39.785 64.962 41.179 ;
     RECT  2.415 41.179 64.998 41.369 ;
     RECT  65.664 42.061 65.682 42.251 ;
     RECT  2.415 41.369 64.926 42.565 ;
     RECT  2.376 42.565 64.926 42.601 ;
     RECT  2.376 42.601 64.962 42.719 ;
     RECT  2.376 42.719 64.926 42.835 ;
     RECT  2.304 42.835 64.926 43.169 ;
     RECT  2.376 43.169 64.926 43.681 ;
     RECT  2.376 43.681 64.998 43.771 ;
     RECT  2.376 43.771 65.25 43.951 ;
     RECT  2.376 43.951 65.682 44.141 ;
     RECT  2.376 44.141 65.466 45.031 ;
     RECT  2.376 45.031 65.682 45.149 ;
     RECT  2.415 45.149 65.682 45.221 ;
     RECT  2.415 45.221 64.998 45.833 ;
     RECT  2.415 45.833 64.566 46.579 ;
     RECT  2.415 46.579 64.674 46.651 ;
     RECT  2.415 46.651 64.746 46.741 ;
     RECT  2.415 46.741 65.286 47.011 ;
     RECT  2.415 47.011 65.358 47.191 ;
     RECT  2.376 47.191 65.574 47.461 ;
     RECT  2.376 47.461 65.682 47.651 ;
     RECT  2.376 47.651 27.162 47.981 ;
     RECT  27.936 47.651 65.682 48.001 ;
     RECT  27.936 48.001 65.754 48.191 ;
     RECT  2.415 47.981 27.162 49.045 ;
     RECT  27.936 48.191 65.106 49.045 ;
     RECT  2.415 49.045 65.106 49.585 ;
     RECT  2.415 49.585 65.214 50.251 ;
     RECT  2.415 50.251 65.394 51.745 ;
     RECT  2.376 51.745 65.394 51.781 ;
     RECT  2.376 51.781 65.682 52.439 ;
     RECT  2.376 52.439 65.538 52.979 ;
     RECT  2.376 52.979 65.43 53.393 ;
     RECT  2.376 53.393 65.286 53.519 ;
     RECT  2.415 53.519 65.286 54.059 ;
     RECT  2.415 54.059 65.178 54.095 ;
     RECT  2.415 54.095 64.89 54.239 ;
     RECT  2.415 54.239 64.746 55.021 ;
     RECT  2.415 55.021 64.854 55.255 ;
     RECT  2.412 55.255 64.854 55.553 ;
     RECT  2.415 55.553 64.854 55.651 ;
     RECT  2.415 55.651 64.926 55.759 ;
     RECT  2.415 55.759 65.502 56.219 ;
     RECT  2.415 56.219 65.394 56.641 ;
     RECT  2.376 56.641 65.394 56.803 ;
     RECT  2.304 56.803 65.394 57.299 ;
     RECT  2.304 57.299 65.358 58.145 ;
     RECT  2.304 58.145 64.998 58.793 ;
     RECT  2.376 58.793 64.998 59.035 ;
     RECT  2.376 59.035 65.178 59.225 ;
     RECT  2.376 59.225 53.946 59.369 ;
     RECT  2.415 59.369 53.946 59.459 ;
     RECT  54.684 59.225 65.178 59.729 ;
     RECT  54.684 59.729 64.998 59.765 ;
     RECT  38.844 59.459 53.946 60.385 ;
     RECT  54.684 59.765 64.89 60.385 ;
     RECT  38.844 60.385 64.89 60.511 ;
     RECT  2.415 59.459 38.07 60.523 ;
     RECT  38.844 60.511 64.962 60.523 ;
     RECT  2.415 60.523 64.962 60.575 ;
     RECT  38.844 60.575 64.962 60.619 ;
     RECT  38.844 60.619 65.646 60.961 ;
     RECT  38.844 60.961 65.682 61.079 ;
     RECT  2.415 60.575 38.07 61.393 ;
     RECT  38.844 61.079 65.574 61.393 ;
     RECT  2.415 61.393 65.574 61.969 ;
     RECT  2.415 61.969 65.754 62.033 ;
     RECT  2.415 62.033 14.238 62.069 ;
     RECT  4.86 62.069 14.238 62.159 ;
     RECT  15.192 62.033 65.754 62.159 ;
     RECT  15.192 62.159 64.746 62.699 ;
     RECT  15.192 62.699 63.27 62.815 ;
     RECT  64.008 62.699 64.746 62.843 ;
     RECT  15.012 62.815 63.27 62.969 ;
     RECT  65.556 62.159 65.646 62.969 ;
     RECT  65.556 62.969 65.574 63.005 ;
     RECT  4.86 62.159 14.202 63.067 ;
     RECT  15.012 62.969 63.234 63.067 ;
     RECT  2.415 62.069 4.122 63.121 ;
     RECT  4.86 63.067 63.234 63.121 ;
     RECT  2.415 63.121 63.234 63.149 ;
     RECT  2.415 63.149 4.446 63.197 ;
     RECT  2.415 63.197 4.122 63.239 ;
     RECT  64.08 62.843 64.746 63.355 ;
     RECT  5.184 63.149 63.234 63.509 ;
     RECT  64.08 63.355 65.106 63.509 ;
     RECT  2.415 63.239 3.618 63.545 ;
     RECT  2.415 63.545 3.402 63.689 ;
     RECT  51.015 63.509 60.606 63.689 ;
     RECT  61.524 63.509 63.234 63.751 ;
     RECT  64.08 63.509 64.17 63.751 ;
     RECT  5.184 63.509 50.094 63.779 ;
     RECT  61.524 63.751 64.17 63.779 ;
     RECT  5.184 63.779 5.202 64.193 ;
     RECT  5.976 63.779 50.094 64.355 ;
     RECT  51.015 63.689 60.462 64.391 ;
     RECT  59.796 64.391 60.462 64.471 ;
     RECT  61.524 63.779 63.954 64.471 ;
     RECT  59.796 64.471 63.954 64.499 ;
     RECT  6.732 64.355 50.094 64.625 ;
     RECT  59.796 64.499 62.91 64.625 ;
     RECT  59.796 64.625 62.622 64.697 ;
     RECT  59.796 64.697 62.097 64.859 ;
     RECT  63.828 64.499 63.954 64.859 ;
     RECT  63.828 64.859 63.846 64.895 ;
     RECT  6.912 64.625 50.094 64.975 ;
     RECT  51.015 64.391 59.022 64.975 ;
     RECT  59.796 64.859 60.318 65.021 ;
     RECT  6.912 64.975 59.022 65.129 ;
     RECT  59.796 65.021 59.886 65.129 ;
     RECT  61.056 64.859 62.097 65.129 ;
     RECT  59.796 65.129 59.814 65.165 ;
     RECT  61.056 65.129 61.074 65.165 ;
     RECT  6.912 65.129 37.782 65.201 ;
     RECT  38.556 65.129 59.022 65.201 ;
     RECT  12.564 65.201 37.782 65.237 ;
     RECT  38.556 65.201 57.69 65.237 ;
     RECT  58.5 65.201 59.022 65.245 ;
     RECT  38.556 65.237 55.638 65.273 ;
     RECT  38.556 65.273 46.602 65.309 ;
     RECT  6.912 65.201 11.754 65.399 ;
     RECT  12.564 65.237 24.297 65.399 ;
     RECT  25.02 65.237 37.782 65.399 ;
     RECT  38.556 65.309 42.93 65.399 ;
     RECT  47.376 65.273 55.602 65.399 ;
     RECT  47.952 65.399 53.262 65.405 ;
     RECT  12.744 65.399 24.297 65.435 ;
     RECT  25.02 65.399 27.09 65.435 ;
     RECT  38.88 65.399 42.93 65.435 ;
     RECT  58.5 65.245 59.598 65.435 ;
     RECT  56.415 65.237 57.69 65.471 ;
     RECT  12.744 65.435 15.75 65.507 ;
     RECT  16.848 65.435 19.17 65.507 ;
     RECT  19.944 65.435 21.042 65.507 ;
     RECT  47.952 65.405 53.046 65.543 ;
     RECT  54.144 65.399 55.602 65.543 ;
     RECT  6.912 65.399 11.61 65.549 ;
     RECT  17.28 65.507 19.17 65.549 ;
     RECT  20.844 65.507 21.042 65.549 ;
     RECT  6.912 65.549 11.178 65.551 ;
     RECT  21.024 65.549 21.042 65.579 ;
     RECT  28.26 65.399 37.674 65.579 ;
     RECT  43.704 65.309 46.602 65.597 ;
     RECT  2.415 63.689 2.697 65.627 ;
     RECT  21.924 65.435 24.297 65.627 ;
     RECT  61.815 65.129 62.097 65.627 ;
     RECT  6.804 65.551 11.178 65.669 ;
     RECT  12.744 65.507 14.31 65.669 ;
     RECT  15.12 65.507 15.75 65.669 ;
     RECT  17.28 65.549 19.098 65.669 ;
     RECT  19.944 65.507 20.106 65.669 ;
     RECT  21.924 65.627 24.105 65.669 ;
     RECT  25.092 65.435 27.09 65.669 ;
     RECT  28.26 65.579 36.342 65.669 ;
     RECT  37.296 65.579 37.674 65.669 ;
     RECT  38.88 65.435 41.31 65.669 ;
     RECT  42.408 65.435 42.93 65.669 ;
     RECT  43.704 65.597 43.722 65.669 ;
     RECT  44.496 65.597 46.602 65.669 ;
     RECT  48.24 65.543 53.046 65.669 ;
     RECT  56.415 65.471 57.654 65.669 ;
     RECT  58.68 65.435 59.598 65.669 ;
     RECT  6.804 65.669 11.106 65.705 ;
     RECT  19.944 65.669 19.962 65.705 ;
     RECT  23.148 65.669 24.105 65.705 ;
     RECT  25.092 65.669 26.298 65.705 ;
     RECT  28.26 65.669 29.79 65.705 ;
     RECT  31.68 65.669 31.698 65.705 ;
     RECT  32.796 65.669 33.426 65.705 ;
     RECT  34.815 65.669 36.342 65.705 ;
     RECT  40.215 65.669 41.094 65.705 ;
     RECT  42.408 65.669 42.426 65.705 ;
     RECT  45.612 65.669 46.314 65.705 ;
     RECT  49.176 65.669 51.105 65.705 ;
     RECT  6.804 65.705 11.034 65.741 ;
     RECT  27.072 65.669 27.09 65.741 ;
     RECT  34.815 65.705 35.55 65.741 ;
     RECT  45.615 65.705 46.314 65.741 ;
     RECT  49.176 65.705 50.058 65.741 ;
     RECT  36.324 65.705 36.342 65.777 ;
     RECT  50.04 65.741 50.058 65.777 ;
     RECT  54.144 65.543 55.35 65.777 ;
     RECT  6.804 65.741 10.098 65.785 ;
     RECT  13.215 65.669 14.022 65.813 ;
     RECT  23.652 65.705 24.105 65.813 ;
     RECT  25.812 65.705 26.298 65.813 ;
     RECT  28.908 65.705 29.574 65.813 ;
     RECT  30.744 65.669 30.762 65.813 ;
     RECT  48.24 65.669 48.258 65.813 ;
     RECT  54.792 65.777 55.35 65.813 ;
     RECT  57.492 65.669 57.51 65.813 ;
     RECT  59.58 65.669 59.598 65.813 ;
     RECT  6.624 65.785 10.098 65.821 ;
     RECT  6.552 65.821 10.098 65.837 ;
     RECT  11.016 65.741 11.034 65.849 ;
     RECT  18.615 65.669 19.062 65.849 ;
     RECT  29.415 65.813 29.574 65.849 ;
     RECT  32.796 65.705 32.814 65.849 ;
     RECT  49.176 65.741 49.194 65.849 ;
     RECT  54.792 65.813 54.81 65.849 ;
     RECT  2.415 65.627 2.505 65.897 ;
     RECT  13.215 65.813 13.305 65.897 ;
     RECT  18.615 65.849 18.705 65.897 ;
     RECT  24.015 65.813 24.105 65.897 ;
     RECT  29.415 65.849 29.505 65.897 ;
     RECT  34.815 65.741 34.905 65.897 ;
     RECT  40.215 65.705 40.305 65.897 ;
     RECT  45.615 65.741 45.705 65.897 ;
     RECT  51.015 65.705 51.105 65.897 ;
     RECT  56.415 65.669 56.505 65.897 ;
     RECT  61.815 65.627 61.905 65.897 ;
     RECT  6.552 65.837 8.73 65.939 ;
     RECT  6.624 65.939 8.73 66.077 ;
     RECT  6.624 66.077 7.65 66.125 ;
     RECT  7.416 66.125 7.65 67.277 ;
     RECT  9.684 65.837 10.098 67.901 ;
     RECT  6.624 66.125 6.642 67.949 ;
     RECT  8.712 66.077 8.73 67.949 ;
     RECT  9.684 67.901 9.702 67.949 ;
    LAYER M4 ;
     RECT  2.365 10.08 2.408 10.104 ;
     RECT  2.401 15.456 2.408 15.48 ;
     RECT  2.401 24.912 2.408 24.936 ;
     RECT  2.365 38.16 2.408 38.184 ;
     RECT  2.365 39.744 2.408 39.768 ;
     RECT  2.365 47.952 2.408 47.976 ;
     RECT  2.365 57.6 2.408 57.624 ;
     RECT  2.408 2.148 2.512 65.892 ;
     RECT  2.512 2.418 2.704 65.622 ;
     RECT  2.704 39.36 2.819 46.248 ;
     RECT  2.704 8.448 2.981 25.128 ;
     RECT  2.704 29.616 2.981 33.912 ;
     RECT  2.819 39.36 2.981 43.368 ;
     RECT  2.704 47.328 3.089 48.456 ;
     RECT  2.981 18.24 3.233 25.128 ;
     RECT  2.981 43.152 3.233 43.368 ;
     RECT  2.819 44.4 3.436 45.72 ;
     RECT  3.233 18.24 3.485 22.008 ;
     RECT  2.981 8.448 3.521 15.624 ;
     RECT  3.485 21.6 3.521 22.008 ;
     RECT  3.436 45.696 3.557 45.72 ;
     RECT  2.981 29.616 3.685 32.76 ;
     RECT  2.704 55.152 3.701 58.776 ;
     RECT  2.704 38.112 3.733 38.184 ;
     RECT  3.521 21.6 3.781 21.672 ;
     RECT  3.089 48.432 3.805 48.456 ;
     RECT  2.704 49.488 3.805 51.288 ;
     RECT  3.685 29.52 3.809 32.76 ;
     RECT  3.701 56.64 3.841 58.776 ;
     RECT  2.704 59.808 3.841 60.984 ;
     RECT  2.704 26.256 3.845 28.248 ;
     RECT  2.704 62.208 3.845 63.192 ;
     RECT  3.809 29.616 3.875 32.76 ;
     RECT  3.845 26.736 3.881 28.248 ;
     RECT  3.233 43.344 3.949 43.368 ;
     RECT  3.436 44.4 3.949 44.472 ;
     RECT  3.805 48.432 3.953 51.288 ;
     RECT  2.704 2.832 3.971 7.368 ;
     RECT  3.953 49.776 3.973 51.288 ;
     RECT  2.704 52.272 3.973 52.296 ;
     RECT  3.971 2.832 3.989 6.36 ;
     RECT  3.841 56.64 3.989 60.984 ;
     RECT  3.973 49.776 4.019 52.488 ;
     RECT  3.521 8.448 4.061 15.24 ;
     RECT  4.019 49.776 4.061 50.76 ;
     RECT  4.019 51.792 4.061 52.488 ;
     RECT  3.233 23.232 4.165 25.128 ;
     RECT  3.733 38.112 4.169 38.28 ;
     RECT  4.061 8.448 4.277 13.08 ;
     RECT  3.949 43.344 4.349 44.472 ;
     RECT  3.913 46.032 4.349 46.056 ;
     RECT  3.953 48.432 4.349 48.456 ;
     RECT  2.981 16.8 4.453 16.968 ;
     RECT  3.485 18.24 4.453 20.328 ;
     RECT  3.089 47.328 4.525 47.4 ;
     RECT  4.165 23.232 4.561 25.752 ;
     RECT  2.981 33.84 4.561 33.912 ;
     RECT  2.704 34.944 4.561 36.648 ;
     RECT  4.169 38.16 4.561 38.28 ;
     RECT  2.981 39.36 4.561 42.024 ;
     RECT  4.561 33.84 4.601 36.648 ;
     RECT  4.277 8.976 4.643 13.08 ;
     RECT  4.061 14.16 4.681 15.24 ;
     RECT  4.681 14.208 4.705 15.24 ;
     RECT  4.453 16.8 4.705 20.328 ;
     RECT  4.561 22.752 4.741 25.752 ;
     RECT  4.601 33.888 4.741 36.648 ;
     RECT  4.349 43.728 4.741 44.472 ;
     RECT  4.453 53.76 4.741 53.784 ;
     RECT  3.875 31.344 4.745 32.76 ;
     RECT  3.781 21.6 4.777 21.624 ;
     RECT  4.741 22.704 4.777 25.752 ;
     RECT  4.525 47.328 4.777 47.976 ;
     RECT  3.701 55.152 4.777 55.656 ;
     RECT  3.989 56.64 4.777 59.16 ;
     RECT  4.741 43.728 4.787 45.048 ;
     RECT  4.561 38.16 4.789 42.024 ;
     RECT  3.875 29.616 4.817 30.216 ;
     RECT  4.705 14.208 4.844 20.328 ;
     RECT  3.881 26.736 4.844 28.2 ;
     RECT  4.741 53.376 4.853 53.928 ;
     RECT  4.061 49.776 4.921 50.472 ;
     RECT  4.745 31.344 4.925 32.52 ;
     RECT  4.789 38.16 4.925 42.696 ;
     RECT  3.989 60.192 4.988 60.984 ;
     RECT  3.989 2.832 5.029 5.544 ;
     RECT  4.844 14.208 5.029 20.424 ;
     RECT  4.777 21.6 5.029 25.752 ;
     RECT  4.921 49.44 5.029 50.472 ;
     RECT  3.845 63.168 5.029 63.192 ;
     RECT  5.029 14.208 5.069 25.752 ;
     RECT  5.029 49.008 5.101 50.472 ;
     RECT  4.061 51.792 5.101 51.912 ;
     RECT  4.787 44.256 5.137 45.048 ;
     RECT  4.988 60.192 5.137 61.224 ;
     RECT  4.844 26.736 5.141 28.44 ;
     RECT  4.925 38.16 5.141 41.64 ;
     RECT  5.029 62.736 5.173 63.192 ;
     RECT  5.029 2.832 5.177 5.736 ;
     RECT  5.137 60.192 5.209 61.512 ;
     RECT  5.173 62.736 5.209 63.864 ;
     RECT  4.853 53.76 5.213 53.928 ;
     RECT  5.209 60.192 5.213 63.864 ;
     RECT  4.643 8.976 5.249 9.096 ;
     RECT  5.069 14.784 5.363 25.752 ;
     RECT  5.213 53.904 5.365 53.928 ;
     RECT  4.777 55.152 5.365 59.16 ;
     RECT  5.177 2.832 5.393 5.544 ;
     RECT  5.365 53.904 5.393 59.16 ;
     RECT  5.393 53.904 5.411 56.808 ;
     RECT  3.971 7.344 5.425 7.368 ;
     RECT  5.393 57.888 5.465 59.16 ;
     RECT  5.137 44.256 5.569 45.768 ;
     RECT  4.777 46.752 5.569 47.976 ;
     RECT  5.101 49.008 5.569 51.912 ;
     RECT  4.925 42.672 5.641 42.696 ;
     RECT  4.741 33.888 5.669 37.128 ;
     RECT  5.141 38.16 5.669 38.184 ;
     RECT  5.141 26.736 5.681 28.296 ;
     RECT  5.213 60.192 5.681 62.76 ;
     RECT  5.669 33.888 5.717 38.184 ;
     RECT  5.717 35.472 5.747 38.184 ;
     RECT  5.363 14.784 5.753 20.328 ;
     RECT  5.747 37.632 5.753 38.184 ;
     RECT  5.569 44.256 5.933 52.584 ;
     RECT  5.465 57.888 5.969 59.064 ;
     RECT  5.411 53.904 6.005 55.704 ;
     RECT  4.925 31.44 6.073 32.52 ;
     RECT  5.641 42.672 6.073 42.744 ;
     RECT  5.425 7.344 6.145 7.416 ;
     RECT  5.393 2.832 6.181 5.496 ;
     RECT  5.141 39.504 6.181 41.64 ;
     RECT  5.213 63.84 6.181 63.864 ;
     RECT  6.181 39.264 6.217 41.64 ;
     RECT  6.073 42.672 6.217 43.032 ;
     RECT  4.643 10.704 6.289 13.08 ;
     RECT  5.933 47.328 6.289 52.584 ;
     RECT  5.681 26.784 6.361 28.296 ;
     RECT  6.073 31.44 6.361 32.76 ;
     RECT  5.717 33.888 6.361 34.248 ;
     RECT  5.753 38.16 6.361 38.184 ;
     RECT  6.217 39.264 6.361 43.032 ;
     RECT  6.361 26.784 6.433 28.44 ;
     RECT  5.969 57.984 6.467 59.064 ;
     RECT  6.181 63.264 6.563 63.864 ;
     RECT  6.145 6.816 6.577 7.416 ;
     RECT  5.249 8.976 6.577 9.048 ;
     RECT  5.753 14.784 6.611 20.184 ;
     RECT  6.577 6.816 6.613 9.048 ;
     RECT  4.817 29.616 6.613 30.168 ;
     RECT  6.289 47.328 6.617 53.304 ;
     RECT  6.467 58.08 6.657 59.064 ;
     RECT  5.681 60.288 6.657 62.28 ;
     RECT  6.611 14.784 6.659 17.688 ;
     RECT  6.657 58.08 6.661 62.28 ;
     RECT  5.747 35.472 6.685 36.504 ;
     RECT  6.659 14.784 6.721 17.64 ;
     RECT  6.005 54.624 6.721 55.704 ;
     RECT  5.411 56.784 6.721 56.808 ;
     RECT  5.363 22.176 6.757 25.752 ;
     RECT  6.433 26.784 6.757 28.488 ;
     RECT  6.361 31.44 6.757 34.248 ;
     RECT  6.685 35.424 6.757 36.504 ;
     RECT  5.933 44.256 6.793 46.344 ;
     RECT  6.617 53.28 6.803 53.304 ;
     RECT  6.661 58.08 6.803 62.472 ;
     RECT  6.721 54.624 6.805 56.808 ;
     RECT  6.361 38.16 6.829 43.032 ;
     RECT  6.289 10.32 6.865 13.08 ;
     RECT  6.721 14.256 6.865 17.64 ;
     RECT  6.829 37.872 6.865 43.032 ;
     RECT  6.611 18.72 6.997 20.184 ;
     RECT  6.829 21.168 6.997 21.192 ;
     RECT  6.613 6.816 7.009 9.144 ;
     RECT  6.613 29.568 7.045 30.168 ;
     RECT  6.757 31.2 7.045 36.504 ;
     RECT  6.865 37.68 7.081 43.032 ;
     RECT  6.793 44.16 7.081 46.344 ;
     RECT  6.997 18.72 7.189 21.192 ;
     RECT  6.757 22.176 7.189 28.488 ;
     RECT  7.081 37.68 7.285 46.344 ;
     RECT  6.617 47.328 7.285 52.2 ;
     RECT  7.153 66.096 7.379 66.12 ;
     RECT  6.613 67.92 7.405 67.944 ;
     RECT  7.429 65.568 7.477 66.072 ;
     RECT  6.805 54.624 7.58 55.032 ;
     RECT  7.189 18.72 7.585 28.488 ;
     RECT  7.045 29.568 7.585 36.504 ;
     RECT  7.285 37.68 7.621 52.2 ;
     RECT  7.405 67.248 7.621 67.944 ;
     RECT  6.181 2.784 7.628 5.496 ;
     RECT  7.009 6.816 7.628 9.288 ;
     RECT  7.628 2.784 7.669 9.288 ;
     RECT  6.865 10.32 7.669 17.64 ;
     RECT  6.563 63.84 7.669 63.864 ;
     RECT  7.477 64.944 7.669 66.072 ;
     RECT  7.621 67.152 7.763 67.944 ;
     RECT  6.803 60.336 7.765 62.472 ;
     RECT  7.585 18.72 7.801 36.504 ;
     RECT  6.803 58.08 7.801 59.064 ;
     RECT  7.765 60.336 7.801 62.856 ;
     RECT  7.669 2.784 7.808 17.64 ;
     RECT  7.801 18.72 7.808 36.648 ;
     RECT  7.621 37.68 7.808 52.824 ;
     RECT  7.58 54.048 7.808 55.032 ;
     RECT  6.805 56.592 7.808 56.808 ;
     RECT  7.801 58.08 7.808 62.856 ;
     RECT  7.669 63.84 7.808 66.072 ;
     RECT  7.808 2.148 7.912 66.072 ;
     RECT  7.912 2.418 8.104 66.072 ;
     RECT  8.104 51.792 8.273 66.072 ;
     RECT  8.104 9.264 8.597 25.128 ;
     RECT  8.104 26.112 8.675 40.584 ;
     RECT  7.763 67.872 8.869 67.944 ;
     RECT  8.104 2.784 9.133 8.232 ;
     RECT  8.597 9.264 9.133 17.736 ;
     RECT  8.675 30.048 9.133 40.584 ;
     RECT  8.104 41.568 9.133 50.712 ;
     RECT  8.597 18.768 9.209 25.128 ;
     RECT  8.273 51.792 9.209 65.832 ;
     RECT  9.133 30.048 9.277 50.712 ;
     RECT  9.209 51.792 9.277 58.152 ;
     RECT  9.133 2.784 9.281 17.736 ;
     RECT  8.675 26.112 9.349 28.536 ;
     RECT  9.209 18.768 9.353 24.792 ;
     RECT  9.277 30.048 9.353 58.152 ;
     RECT  9.353 30.048 9.425 38.808 ;
     RECT  9.349 25.776 9.677 28.536 ;
     RECT  9.209 59.28 9.677 65.832 ;
     RECT  8.869 67.776 9.713 67.944 ;
     RECT  9.425 30.048 9.721 38.712 ;
     RECT  9.353 39.792 9.731 58.152 ;
     RECT  9.281 2.784 9.785 17.64 ;
     RECT  9.721 30.048 9.785 35.592 ;
     RECT  9.785 30.048 9.827 34.392 ;
     RECT  9.731 45.744 9.857 58.152 ;
     RECT  9.713 67.776 9.893 67.896 ;
     RECT  9.677 59.28 9.965 65.448 ;
     RECT  9.785 2.784 9.993 15 ;
     RECT  9.893 67.872 10.109 67.896 ;
     RECT  9.857 45.744 10.115 56.52 ;
     RECT  9.731 39.792 10.145 44.76 ;
     RECT  10.115 45.744 10.289 49.848 ;
     RECT  9.857 57.6 10.357 58.152 ;
     RECT  9.965 59.28 10.357 63 ;
     RECT  9.827 30.048 10.393 34.152 ;
     RECT  9.721 36.576 10.393 38.712 ;
     RECT  10.145 39.792 10.393 44.424 ;
     RECT  9.353 18.96 10.537 24.792 ;
     RECT  9.677 25.776 10.537 28.44 ;
     RECT  9.993 3.36 10.643 15 ;
     RECT  9.785 35.568 10.693 35.592 ;
     RECT  10.393 36.576 10.693 44.424 ;
     RECT  10.537 18.96 10.753 28.44 ;
     RECT  10.393 29.616 10.753 34.152 ;
     RECT  10.643 7.056 10.789 15 ;
     RECT  9.785 16.032 10.789 17.64 ;
     RECT  10.753 18.96 10.789 34.152 ;
     RECT  10.693 35.568 10.789 44.424 ;
     RECT  10.789 18.768 10.793 44.424 ;
     RECT  10.789 7.056 10.829 17.64 ;
     RECT  10.357 57.6 10.835 63 ;
     RECT  10.793 37.008 10.883 44.424 ;
     RECT  10.829 10.08 10.969 17.64 ;
     RECT  10.793 18.768 10.969 35.448 ;
     RECT  10.969 10.08 10.973 35.448 ;
     RECT  10.835 59.28 11.001 63 ;
     RECT  10.717 2.304 11.041 2.328 ;
     RECT  10.643 3.36 11.041 5.976 ;
     RECT  10.289 45.744 11.077 49.8 ;
     RECT  11.041 2.304 11.081 5.976 ;
     RECT  10.973 10.128 11.189 35.448 ;
     RECT  10.883 43.344 11.189 44.424 ;
     RECT  11.077 45.696 11.225 49.8 ;
     RECT  11.225 45.696 11.261 49.704 ;
     RECT  11.189 10.848 11.369 35.448 ;
     RECT  10.115 50.88 11.401 56.52 ;
     RECT  10.835 57.6 11.401 58.152 ;
     RECT  11.001 59.808 11.401 63 ;
     RECT  9.965 64.368 11.401 65.448 ;
     RECT  11.401 59.808 11.441 65.448 ;
     RECT  11.081 2.832 11.459 5.976 ;
     RECT  11.189 43.68 11.477 44.424 ;
     RECT  11.369 24.48 11.507 35.448 ;
     RECT  11.477 43.824 11.545 44.424 ;
     RECT  11.261 45.696 11.545 49.608 ;
     RECT  11.401 50.88 11.581 58.152 ;
     RECT  11.441 59.952 11.581 65.448 ;
     RECT  11.507 27.312 11.603 35.448 ;
     RECT  11.581 59.952 11.621 65.544 ;
     RECT  11.621 59.952 11.629 63.864 ;
     RECT  11.581 50.832 11.651 58.152 ;
     RECT  11.459 4.896 11.761 5.976 ;
     RECT  11.603 27.648 11.797 35.448 ;
     RECT  11.761 4.896 11.833 6.072 ;
     RECT  10.829 7.056 11.833 9.096 ;
     RECT  11.459 2.832 11.837 3.816 ;
     RECT  10.883 37.008 11.941 41.976 ;
     RECT  11.941 37.008 11.977 42.024 ;
     RECT  11.651 50.832 11.987 55.272 ;
     RECT  11.977 37.008 12.049 42.168 ;
     RECT  11.833 4.896 12.053 9.096 ;
     RECT  11.629 59.952 12.053 63.816 ;
     RECT  12.053 9.024 12.083 9.096 ;
     RECT  11.545 43.824 12.229 49.608 ;
     RECT  11.987 50.832 12.229 50.952 ;
     RECT  11.651 56.448 12.373 58.152 ;
     RECT  11.507 24.48 12.445 26.328 ;
     RECT  12.049 36.96 12.517 42.168 ;
     RECT  11.369 10.848 12.661 23.448 ;
     RECT  11.987 52.176 12.661 55.272 ;
     RECT  12.373 56.448 12.661 58.296 ;
     RECT  11.621 64.896 12.709 65.544 ;
     RECT  12.661 10.8 12.733 23.448 ;
     RECT  12.445 24.432 12.733 26.328 ;
     RECT  12.517 36.96 12.805 42.216 ;
     RECT  12.733 10.8 12.812 26.328 ;
     RECT  11.797 27.648 12.877 35.928 ;
     RECT  12.805 36.96 12.877 42.792 ;
     RECT  12.812 10.704 13.055 26.328 ;
     RECT  12.229 43.824 13.057 50.952 ;
     RECT  12.661 52.176 13.093 58.296 ;
     RECT  13.055 10.704 13.129 26.568 ;
     RECT  12.877 27.648 13.129 42.792 ;
     RECT  11.837 2.832 13.208 3.432 ;
     RECT  12.053 4.896 13.208 7.896 ;
     RECT  12.083 9.072 13.208 9.096 ;
     RECT  13.129 10.704 13.208 42.792 ;
     RECT  13.057 43.824 13.208 51 ;
     RECT  13.093 52.176 13.208 58.536 ;
     RECT  12.053 60 13.208 63.816 ;
     RECT  12.709 64.896 13.208 65.64 ;
     RECT  13.208 2.148 13.312 65.892 ;
     RECT  13.312 2.256 13.504 65.622 ;
     RECT  13.504 5.088 13.529 42.792 ;
     RECT  13.529 5.088 13.709 29.784 ;
     RECT  13.504 48.576 13.745 59.4 ;
     RECT  13.504 60.672 13.859 64.968 ;
     RECT  13.529 30.768 14.285 42.792 ;
     RECT  13.504 2.256 14.291 3.912 ;
     RECT  13.745 55.152 14.321 59.4 ;
     RECT  14.321 55.152 14.357 59.304 ;
     RECT  13.709 5.088 14.429 23.448 ;
     RECT  13.504 44.4 14.533 47.352 ;
     RECT  13.709 24.48 14.579 29.784 ;
     RECT  14.285 30.768 14.579 42.696 ;
     RECT  14.533 44.304 14.785 47.352 ;
     RECT  13.745 48.576 14.785 53.88 ;
     RECT  14.291 2.496 14.857 3.912 ;
     RECT  14.429 5.088 14.857 21.528 ;
     RECT  14.785 44.304 14.965 53.88 ;
     RECT  13.859 63.072 14.972 64.968 ;
     RECT  14.972 62.832 15.059 64.968 ;
     RECT  15.059 63.264 15.068 64.968 ;
     RECT  14.965 44.112 15.1 53.88 ;
     RECT  14.579 24.48 15.155 29.496 ;
     RECT  15.068 63.264 15.155 65.64 ;
     RECT  14.357 55.152 15.181 55.848 ;
     RECT  15.1 44.112 15.469 47.688 ;
     RECT  15.1 48.768 15.505 53.88 ;
     RECT  15.181 55.008 15.505 55.848 ;
     RECT  13.859 60.672 15.541 61.608 ;
     RECT  14.579 30.816 15.577 42.696 ;
     RECT  14.857 2.496 15.613 21.528 ;
     RECT  14.429 22.512 15.613 23.448 ;
     RECT  15.505 48.768 15.653 55.848 ;
     RECT  15.469 43.92 15.721 47.688 ;
     RECT  15.155 25.056 15.757 29.496 ;
     RECT  15.577 30.768 15.757 42.696 ;
     RECT  15.613 2.496 15.793 23.448 ;
     RECT  15.757 25.056 15.973 42.696 ;
     RECT  15.721 43.776 15.973 47.688 ;
     RECT  15.653 54.864 15.973 55.848 ;
     RECT  14.357 57.264 15.973 59.304 ;
     RECT  15.973 25.056 16.049 47.688 ;
     RECT  15.541 60.384 16.049 61.608 ;
     RECT  16.049 36.096 16.085 47.688 ;
     RECT  15.793 2.496 16.153 23.592 ;
     RECT  16.085 38.4 16.153 47.688 ;
     RECT  15.653 48.768 16.153 53.88 ;
     RECT  16.049 25.056 16.261 35.064 ;
     RECT  15.973 54.864 16.297 55.944 ;
     RECT  15.973 56.976 16.297 59.304 ;
     RECT  16.297 54.864 16.369 59.304 ;
     RECT  16.049 60.384 16.369 60.984 ;
     RECT  16.153 2.496 16.513 23.64 ;
     RECT  16.261 24.72 16.513 35.064 ;
     RECT  16.513 2.496 16.553 35.064 ;
     RECT  16.153 38.4 16.553 53.88 ;
     RECT  16.837 62.016 16.873 62.04 ;
     RECT  15.155 63.264 16.873 65.208 ;
     RECT  16.085 36.096 17.125 37.176 ;
     RECT  16.553 38.4 17.129 51.192 ;
     RECT  16.553 18.528 17.228 35.064 ;
     RECT  17.125 36.096 17.228 37.416 ;
     RECT  16.369 54.864 17.237 60.984 ;
     RECT  16.873 62.016 17.269 65.208 ;
     RECT  17.228 18.528 17.309 37.416 ;
     RECT  17.269 62.016 17.309 65.592 ;
     RECT  17.309 24.624 17.345 37.416 ;
     RECT  17.309 62.16 17.555 65.592 ;
     RECT  17.129 45.024 17.593 51.192 ;
     RECT  16.553 52.176 17.593 53.88 ;
     RECT  16.553 2.496 17.653 17.496 ;
     RECT  17.309 18.528 17.653 23.544 ;
     RECT  17.345 31.488 17.917 37.416 ;
     RECT  17.129 38.4 17.917 43.848 ;
     RECT  17.653 2.496 17.989 23.544 ;
     RECT  17.593 45.024 18.277 53.88 ;
     RECT  17.237 54.864 18.277 60.84 ;
     RECT  17.345 24.624 18.385 30.408 ;
     RECT  17.917 31.488 18.385 43.848 ;
     RECT  17.989 2.256 18.493 23.544 ;
     RECT  18.493 2.256 18.608 23.592 ;
     RECT  18.385 24.624 18.608 43.848 ;
     RECT  18.277 45.024 18.608 60.84 ;
     RECT  17.555 62.16 18.608 65.544 ;
     RECT  18.608 2.148 18.712 65.892 ;
     RECT  18.712 2.256 18.904 65.622 ;
     RECT  18.904 52.512 19.187 58.104 ;
     RECT  18.904 65.52 19.379 65.544 ;
     RECT  18.904 2.256 19.577 51.24 ;
     RECT  19.577 2.256 19.865 50.904 ;
     RECT  18.904 60.288 20.153 64.392 ;
     RECT  19.187 52.512 20.329 55.272 ;
     RECT  19.187 56.832 20.473 58.104 ;
     RECT  18.904 59.184 20.473 59.208 ;
     RECT  20.329 52.416 20.533 55.272 ;
     RECT  20.473 64.848 20.729 64.872 ;
     RECT  20.153 60.288 20.915 63.768 ;
     RECT  20.473 56.832 21.049 59.208 ;
     RECT  20.915 60.288 21.05 63.72 ;
     RECT  19.865 29.328 21.085 50.904 ;
     RECT  21.085 29.328 21.089 51 ;
     RECT  21.05 60.336 21.125 63.72 ;
     RECT  21.125 60.336 21.155 63.624 ;
     RECT  19.865 2.256 21.337 28.344 ;
     RECT  21.089 29.328 21.337 42.6 ;
     RECT  21.337 2.256 21.341 42.6 ;
     RECT  21.089 43.584 21.596 51 ;
     RECT  20.533 52.416 21.596 55.416 ;
     RECT  21.049 56.832 21.665 59.256 ;
     RECT  21.341 2.352 21.683 42.6 ;
     RECT  21.596 43.584 21.683 55.416 ;
     RECT  21.683 43.584 21.701 51.144 ;
     RECT  21.683 52.512 21.733 55.416 ;
     RECT  21.683 2.352 21.773 39.144 ;
     RECT  21.683 40.128 21.773 42.6 ;
     RECT  21.701 48.24 21.971 51.144 ;
     RECT  21.971 48.432 21.989 51.144 ;
     RECT  21.773 40.272 22.061 42.6 ;
     RECT  21.733 52.512 22.133 55.752 ;
     RECT  22.061 40.512 22.205 42.6 ;
     RECT  22.205 40.896 22.211 42.6 ;
     RECT  21.773 8.4 22.252 39.144 ;
     RECT  22.133 54.864 22.313 55.752 ;
     RECT  22.211 41.136 22.405 42.6 ;
     RECT  21.701 43.584 22.405 47.208 ;
     RECT  21.773 2.352 22.525 7.416 ;
     RECT  22.252 8.448 22.529 39.144 ;
     RECT  21.665 56.832 22.669 59.208 ;
     RECT  22.133 52.512 22.673 53.88 ;
     RECT  22.669 56.832 22.705 59.256 ;
     RECT  21.155 60.336 22.705 61.464 ;
     RECT  22.673 52.512 22.748 53.592 ;
     RECT  21.155 62.448 22.789 63.624 ;
     RECT  22.705 56.832 22.796 61.464 ;
     RECT  22.789 62.448 22.796 63.912 ;
     RECT  22.525 2.256 22.817 7.416 ;
     RECT  22.796 56.832 22.925 63.912 ;
     RECT  22.817 2.352 22.993 7.416 ;
     RECT  22.925 60.912 22.993 63.912 ;
     RECT  22.993 2.352 23.317 7.464 ;
     RECT  22.529 8.448 23.317 38.76 ;
     RECT  22.313 54.864 23.425 55.272 ;
     RECT  21.989 48.48 23.701 51.144 ;
     RECT  22.748 52.128 23.701 53.592 ;
     RECT  22.405 41.136 24.001 47.208 ;
     RECT  23.317 2.352 24.008 38.76 ;
     RECT  23.423 39.84 24.008 39.864 ;
     RECT  24.001 40.848 24.008 47.208 ;
     RECT  23.701 48.48 24.008 53.592 ;
     RECT  23.425 54.72 24.008 55.272 ;
     RECT  22.925 56.832 24.008 59.64 ;
     RECT  22.993 60.912 24.008 64.344 ;
     RECT  20.833 65.52 24.008 65.544 ;
     RECT  24.008 2.148 24.112 65.892 ;
     RECT  24.112 2.418 24.304 65.688 ;
     RECT  24.304 60.864 24.437 63.912 ;
     RECT  24.304 42.432 24.689 59.832 ;
     RECT  24.689 53.952 24.905 59.832 ;
     RECT  24.437 60.912 24.941 63.912 ;
     RECT  24.304 2.418 25.081 41.4 ;
     RECT  24.304 64.896 25.132 65.688 ;
     RECT  25.081 2.256 25.369 41.4 ;
     RECT  24.689 42.432 25.369 52.584 ;
     RECT  25.132 64.896 25.475 64.92 ;
     RECT  24.905 56.832 25.916 59.832 ;
     RECT  24.941 60.912 25.916 61.464 ;
     RECT  25.916 56.832 26.003 61.464 ;
     RECT  24.905 53.952 26.237 55.848 ;
     RECT  25.369 2.256 26.273 52.584 ;
     RECT  26.003 60.96 26.305 61.464 ;
     RECT  24.941 62.448 26.305 63.912 ;
     RECT  26.449 64.896 26.457 64.92 ;
     RECT  26.305 60.96 26.485 63.912 ;
     RECT  26.457 64.896 26.485 65.16 ;
     RECT  26.485 60.96 26.569 65.16 ;
     RECT  26.273 44.4 26.705 52.584 ;
     RECT  26.237 53.952 26.737 55.8 ;
     RECT  26.273 2.256 26.771 43.368 ;
     RECT  26.705 44.4 26.813 47.88 ;
     RECT  26.771 2.256 26.849 3.336 ;
     RECT  26.771 4.512 26.993 43.368 ;
     RECT  26.993 38.64 27.301 43.368 ;
     RECT  26.813 44.4 27.301 47.64 ;
     RECT  27.301 38.64 27.317 47.64 ;
     RECT  27.317 38.64 27.389 39.384 ;
     RECT  26.003 56.832 27.397 59.832 ;
     RECT  26.569 60.96 27.397 63.912 ;
     RECT  26.737 53.664 27.493 55.8 ;
     RECT  27.397 56.832 27.493 63.912 ;
     RECT  27.493 53.664 27.677 63.912 ;
     RECT  26.993 4.512 27.683 37.608 ;
     RECT  26.849 2.256 27.853 3.24 ;
     RECT  27.683 4.512 27.853 23.688 ;
     RECT  27.677 59.136 27.877 63.912 ;
     RECT  26.569 64.896 27.877 65.16 ;
     RECT  27.677 53.664 27.929 58.152 ;
     RECT  27.683 24.672 27.971 37.608 ;
     RECT  27.389 38.64 28.033 39.24 ;
     RECT  27.877 59.136 28.073 65.16 ;
     RECT  27.853 2.256 28.115 23.688 ;
     RECT  26.705 48.96 28.285 52.584 ;
     RECT  27.929 53.664 28.285 53.688 ;
     RECT  28.033 38.592 28.465 39.24 ;
     RECT  27.317 40.512 28.465 47.64 ;
     RECT  27.971 35.328 28.573 37.608 ;
     RECT  28.465 38.592 28.573 47.64 ;
     RECT  28.573 35.328 28.885 47.64 ;
     RECT  28.285 48.96 28.885 53.688 ;
     RECT  28.885 35.328 28.969 53.688 ;
     RECT  27.929 54.72 28.969 58.152 ;
     RECT  28.969 35.328 29.041 58.152 ;
     RECT  28.073 59.136 29.041 64.92 ;
     RECT  27.971 24.672 29.185 34.152 ;
     RECT  29.041 35.328 29.185 64.92 ;
     RECT  28.115 2.784 29.257 23.688 ;
     RECT  29.185 24.672 29.257 64.92 ;
     RECT  29.257 2.784 29.269 64.92 ;
     RECT  29.269 2.784 29.408 65.16 ;
     RECT  29.408 2.148 29.512 65.892 ;
     RECT  29.512 2.418 29.704 65.622 ;
     RECT  29.704 2.784 29.801 55.56 ;
     RECT  29.801 2.784 29.981 39.768 ;
     RECT  29.981 2.832 30.305 39.768 ;
     RECT  29.801 40.992 30.611 55.56 ;
     RECT  29.704 61.872 30.769 64.968 ;
     RECT  30.305 33.888 30.841 39.768 ;
     RECT  30.611 40.992 30.841 55.512 ;
     RECT  30.769 61.872 30.841 65.112 ;
     RECT  30.305 2.832 31.237 32.472 ;
     RECT  31.237 2.736 31.331 32.472 ;
     RECT  30.841 33.888 31.385 55.512 ;
     RECT  31.331 23.328 31.489 32.472 ;
     RECT  31.385 33.888 31.489 53.832 ;
     RECT  31.385 54.864 31.493 55.512 ;
     RECT  29.704 56.592 31.745 60.024 ;
     RECT  31.493 55.2 31.813 55.512 ;
     RECT  31.745 56.592 31.813 59.16 ;
     RECT  30.841 61.632 32.281 65.112 ;
     RECT  31.489 23.328 32.285 53.832 ;
     RECT  31.331 2.736 32.461 22.152 ;
     RECT  32.285 23.328 32.461 43.32 ;
     RECT  32.461 2.736 32.465 43.32 ;
     RECT  32.465 2.736 32.537 3.384 ;
     RECT  32.281 61.632 32.573 65.592 ;
     RECT  32.285 44.448 32.605 53.832 ;
     RECT  31.813 55.2 32.605 59.16 ;
     RECT  32.573 61.632 32.645 63.624 ;
     RECT  32.605 44.448 32.749 59.16 ;
     RECT  32.281 60.432 32.749 60.456 ;
     RECT  32.749 44.448 32.789 60.456 ;
     RECT  32.537 3.36 32.825 3.384 ;
     RECT  32.465 4.416 32.897 43.272 ;
     RECT  32.897 4.416 32.969 38.184 ;
     RECT  32.969 12.48 33.149 38.184 ;
     RECT  32.789 44.448 33.347 59.832 ;
     RECT  32.573 64.896 33.437 65.592 ;
     RECT  32.645 61.632 33.5 63.288 ;
     RECT  32.897 39.456 33.509 43.272 ;
     RECT  33.149 22.8 33.545 38.184 ;
     RECT  33.347 44.448 33.545 58.632 ;
     RECT  33.347 59.808 33.587 59.832 ;
     RECT  33.437 64.896 33.587 65.448 ;
     RECT  33.509 39.456 33.617 42.36 ;
     RECT  33.617 39.456 33.635 42.168 ;
     RECT  33.635 39.456 33.725 42.024 ;
     RECT  33.545 45.024 33.725 58.632 ;
     RECT  33.725 58.464 33.761 58.632 ;
     RECT  33.149 12.48 34.189 21.72 ;
     RECT  33.545 22.8 34.189 38.136 ;
     RECT  32.969 4.416 34.261 11.496 ;
     RECT  34.189 12.48 34.261 38.136 ;
     RECT  34.289 0.096 34.297 0.12 ;
     RECT  34.297 0.096 34.364 0.504 ;
     RECT  33.5 61.2 34.405 63.288 ;
     RECT  34.261 4.416 34.549 38.136 ;
     RECT  34.441 39.216 34.549 39.24 ;
     RECT  33.587 65.424 34.645 65.448 ;
     RECT  33.589 43.776 34.657 43.8 ;
     RECT  33.725 45.024 34.657 57.432 ;
     RECT  33.725 40.368 34.693 42.024 ;
     RECT  34.549 4.416 34.808 39.24 ;
     RECT  34.693 40.368 34.808 42.552 ;
     RECT  34.657 43.776 34.808 57.432 ;
     RECT  33.761 58.464 34.808 58.488 ;
     RECT  34.405 60.912 34.808 63.288 ;
     RECT  34.645 64.752 34.808 65.448 ;
     RECT  34.808 2.148 34.912 65.892 ;
     RECT  34.912 2.148 35.104 65.622 ;
     RECT  35.261 1.728 35.345 1.752 ;
     RECT  35.104 44.352 35.453 63.816 ;
     RECT  35.104 4.848 35.507 17.208 ;
     RECT  34.364 0.096 35.603 0.552 ;
     RECT  35.104 18.192 35.741 41.256 ;
     RECT  35.507 4.848 35.813 7.992 ;
     RECT  35.453 56.592 35.993 63.816 ;
     RECT  35.741 23.328 36.101 41.256 ;
     RECT  36.101 23.328 36.173 31.8 ;
     RECT  35.507 9.072 36.205 17.208 ;
     RECT  35.741 18.192 36.205 22.344 ;
     RECT  36.101 32.832 36.317 41.256 ;
     RECT  36.317 33.552 36.421 41.256 ;
     RECT  35.104 42.24 36.421 43.368 ;
     RECT  35.453 44.352 36.421 55.608 ;
     RECT  36.421 33.552 36.493 55.608 ;
     RECT  35.993 56.592 36.493 59.784 ;
     RECT  36.493 33.552 36.563 59.784 ;
     RECT  36.637 3.936 36.721 3.96 ;
     RECT  36.563 53.808 36.749 59.784 ;
     RECT  35.993 60.912 36.785 63.816 ;
     RECT  36.749 53.856 36.857 59.784 ;
     RECT  36.857 54.144 36.893 59.784 ;
     RECT  35.813 4.944 36.925 7.992 ;
     RECT  36.205 9.072 36.925 22.344 ;
     RECT  36.893 54.144 37.043 57.864 ;
     RECT  36.785 61.536 37.073 63.816 ;
     RECT  36.173 23.52 37.1 31.8 ;
     RECT  37.1 23.52 37.187 32.376 ;
     RECT  36.563 33.552 37.217 52.824 ;
     RECT  35.104 65.424 37.285 65.448 ;
     RECT  37.043 54.432 37.427 57.864 ;
     RECT  36.925 4.944 37.429 22.344 ;
     RECT  37.187 23.52 37.429 31.704 ;
     RECT  36.893 59.328 37.484 59.784 ;
     RECT  37.484 59.328 37.525 59.928 ;
     RECT  37.141 3.264 37.537 3.816 ;
     RECT  37.285 65.424 37.571 65.592 ;
     RECT  37.073 61.584 37.613 63.816 ;
     RECT  37.217 33.552 37.757 43.944 ;
     RECT  37.217 45.216 37.825 52.824 ;
     RECT  37.537 3.024 37.861 3.816 ;
     RECT  37.429 4.944 37.861 31.704 ;
     RECT  37.427 56.352 37.865 57.864 ;
     RECT  37.865 56.448 37.901 57.864 ;
     RECT  37.427 54.432 38.261 54.6 ;
     RECT  37.861 3.024 38.473 31.704 ;
     RECT  37.825 45.216 38.473 53.016 ;
     RECT  38.473 3.024 38.496 31.8 ;
     RECT  38.496 3.024 38.549 8.52 ;
     RECT  35.603 0.096 38.621 0.312 ;
     RECT  38.496 9.792 38.621 31.8 ;
     RECT  37.525 59.328 38.645 60.024 ;
     RECT  37.613 61.584 38.645 63.288 ;
     RECT  38.645 61.584 38.723 64.2 ;
     RECT  38.645 59.328 38.729 60.552 ;
     RECT  38.723 62.16 38.729 64.2 ;
     RECT  38.621 9.936 38.761 31.8 ;
     RECT  38.761 9.936 38.78 32.232 ;
     RECT  38.549 3.024 38.801 6.888 ;
     RECT  38.78 9.936 38.821 32.472 ;
     RECT  37.757 33.552 38.821 37.704 ;
     RECT  38.473 45.024 38.873 53.016 ;
     RECT  37.571 65.424 38.909 65.448 ;
     RECT  37.757 38.688 38.963 43.944 ;
     RECT  38.729 59.328 38.977 60.024 ;
     RECT  38.963 40.416 38.981 43.944 ;
     RECT  38.873 50.304 39.049 53.016 ;
     RECT  38.821 9.936 39.053 37.704 ;
     RECT  38.981 40.416 39.053 42.744 ;
     RECT  37.901 56.448 39.085 57.384 ;
     RECT  38.981 43.92 39.089 43.944 ;
     RECT  39.053 9.936 39.197 35.592 ;
     RECT  38.621 0.096 39.269 0.12 ;
     RECT  38.801 3.024 39.301 4.2 ;
     RECT  39.049 50.304 39.301 53.4 ;
     RECT  38.761 54.384 39.301 54.408 ;
     RECT  39.085 56.448 39.481 57.48 ;
     RECT  39.053 36.624 39.5 37.704 ;
     RECT  38.963 38.688 39.5 39 ;
     RECT  39.301 50.304 39.841 54.408 ;
     RECT  38.549 7.92 39.877 8.52 ;
     RECT  39.197 9.936 39.877 32.232 ;
     RECT  39.481 56.352 39.913 57.48 ;
     RECT  38.977 58.512 39.913 60.024 ;
     RECT  39.841 50.304 40.021 54.888 ;
     RECT  39.197 33.312 40.093 35.592 ;
     RECT  39.5 36.624 40.093 39 ;
     RECT  38.873 45.024 40.165 49.32 ;
     RECT  38.729 62.16 40.165 63.288 ;
     RECT  39.301 2.064 40.208 4.2 ;
     RECT  38.801 5.184 40.208 6.888 ;
     RECT  39.877 7.92 40.208 32.232 ;
     RECT  40.093 33.312 40.208 39 ;
     RECT  39.053 40.416 40.208 41.208 ;
     RECT  39.053 42.528 40.208 42.744 ;
     RECT  40.165 44.88 40.208 49.32 ;
     RECT  40.021 50.304 40.208 54.936 ;
     RECT  39.913 56.352 40.208 60.024 ;
     RECT  40.165 61.728 40.208 63.576 ;
     RECT  39.625 64.752 40.208 64.776 ;
     RECT  40.208 2.064 40.312 65.892 ;
     RECT  40.312 2.064 40.504 65.622 ;
     RECT  40.504 20.16 40.601 43.512 ;
     RECT  40.601 34.368 40.637 43.512 ;
     RECT  40.504 2.064 40.673 6.936 ;
     RECT  40.504 7.92 40.817 19.08 ;
     RECT  40.504 59.52 40.817 64.968 ;
     RECT  40.817 7.92 40.881 18.984 ;
     RECT  40.881 12.48 40.925 18.984 ;
     RECT  40.925 12.48 41.027 18.888 ;
     RECT  40.673 3.312 41.069 6.936 ;
     RECT  41.069 3.36 41.177 6.936 ;
     RECT  41.027 12.48 41.213 18.84 ;
     RECT  40.504 44.88 41.213 49.272 ;
     RECT  40.504 50.304 41.249 54.936 ;
     RECT  41.213 12.48 41.321 18.792 ;
     RECT  41.321 12.48 41.465 18.696 ;
     RECT  41.177 3.36 41.573 6.312 ;
     RECT  40.601 20.16 41.603 33.096 ;
     RECT  41.573 3.36 41.681 6.216 ;
     RECT  40.881 7.92 41.681 11.448 ;
     RECT  40.504 56.16 41.681 58.44 ;
     RECT  41.681 7.92 41.797 8.04 ;
     RECT  41.797 7.632 41.897 8.04 ;
     RECT  41.465 12.48 41.969 18.648 ;
     RECT  41.969 12.48 41.987 14.808 ;
     RECT  40.637 34.464 42.001 43.512 ;
     RECT  41.603 31.92 42.037 33.096 ;
     RECT  42.001 34.464 42.037 43.848 ;
     RECT  41.681 3.648 42.041 6.216 ;
     RECT  40.817 60 42.145 64.968 ;
     RECT  42.037 31.92 42.181 43.848 ;
     RECT  41.213 44.88 42.181 49.08 ;
     RECT  41.603 20.16 42.185 30.936 ;
     RECT  42.145 59.856 42.217 64.968 ;
     RECT  42.041 3.648 42.227 3.72 ;
     RECT  42.185 22.464 42.293 30.936 ;
     RECT  41.249 50.304 42.325 52.728 ;
     RECT  41.681 56.16 42.325 57.96 ;
     RECT  41.249 53.856 42.433 54.936 ;
     RECT  42.325 55.92 42.433 57.96 ;
     RECT  42.325 50.16 42.469 52.728 ;
     RECT  42.433 53.856 42.469 57.96 ;
     RECT  42.185 20.16 42.572 21.48 ;
     RECT  41.969 15.792 42.721 18.648 ;
     RECT  42.572 19.824 42.721 21.48 ;
     RECT  42.217 58.992 42.757 64.968 ;
     RECT  41.681 9.12 42.797 11.448 ;
     RECT  42.469 50.16 42.833 57.96 ;
     RECT  42.833 55.92 42.865 57.96 ;
     RECT  42.757 58.992 42.865 65.592 ;
     RECT  42.833 50.16 43.049 54.744 ;
     RECT  41.897 8.016 43.081 8.04 ;
     RECT  42.797 9.36 43.117 11.448 ;
     RECT  41.987 12.48 43.117 14.712 ;
     RECT  40.673 2.064 43.153 2.088 ;
     RECT  43.153 2.064 43.193 2.28 ;
     RECT  43.117 9.36 43.229 14.712 ;
     RECT  42.041 4.896 43.285 6.216 ;
     RECT  43.081 7.44 43.285 8.04 ;
     RECT  42.293 22.464 43.297 22.776 ;
     RECT  42.293 23.808 43.297 30.936 ;
     RECT  43.285 4.896 43.331 8.04 ;
     RECT  42.227 3.696 43.333 3.72 ;
     RECT  43.331 4.896 43.333 6.84 ;
     RECT  43.297 22.464 43.369 30.936 ;
     RECT  42.181 31.92 43.369 49.08 ;
     RECT  43.331 8.016 43.373 8.04 ;
     RECT  42.721 15.792 43.373 21.48 ;
     RECT  43.369 22.464 43.373 49.08 ;
     RECT  43.373 45.216 43.409 49.08 ;
     RECT  42.865 55.92 43.589 65.592 ;
     RECT  43.193 2.256 43.621 2.28 ;
     RECT  43.333 3.696 43.621 6.84 ;
     RECT  43.621 2.256 43.667 6.84 ;
     RECT  43.373 19.536 43.693 21.48 ;
     RECT  43.373 22.464 43.693 44.088 ;
     RECT  43.229 9.36 43.765 11.208 ;
     RECT  43.229 12.72 43.765 14.712 ;
     RECT  43.373 15.792 43.765 18.504 ;
     RECT  43.049 50.304 43.837 54.744 ;
     RECT  43.589 55.92 43.837 59.88 ;
     RECT  43.693 19.536 43.841 44.088 ;
     RECT  43.837 50.304 43.957 59.88 ;
     RECT  43.765 9.072 43.985 11.208 ;
     RECT  43.589 61.488 44.051 65.592 ;
     RECT  44.051 62.736 44.057 65.592 ;
     RECT  44.057 62.976 44.129 65.592 ;
     RECT  43.985 9.936 44.197 11.208 ;
     RECT  43.667 3.024 44.237 6.84 ;
     RECT  43.841 19.632 44.341 44.088 ;
     RECT  43.409 45.216 44.341 48.984 ;
     RECT  44.197 9.936 44.345 11.688 ;
     RECT  44.051 61.488 44.345 61.512 ;
     RECT  43.957 55.68 44.557 59.88 ;
     RECT  44.557 55.68 44.809 59.928 ;
     RECT  43.765 12.72 44.953 18.504 ;
     RECT  44.341 19.632 44.953 48.984 ;
     RECT  44.345 10.032 44.965 11.688 ;
     RECT  44.953 12.72 44.965 48.984 ;
     RECT  44.629 7.968 45.025 7.992 ;
     RECT  44.809 55.68 45.061 60.36 ;
     RECT  44.965 10.032 45.169 48.984 ;
     RECT  43.957 50.304 45.169 54.696 ;
     RECT  44.237 3.024 45.277 6.504 ;
     RECT  45.025 7.968 45.277 8.856 ;
     RECT  45.169 10.032 45.397 54.696 ;
     RECT  45.061 55.68 45.397 60.984 ;
     RECT  45.277 3.024 45.608 8.856 ;
     RECT  45.397 10.032 45.608 60.984 ;
     RECT  44.129 62.976 45.608 63.816 ;
     RECT  44.129 65.568 45.608 65.592 ;
     RECT  45.608 2.148 45.712 65.892 ;
     RECT  45.712 2.418 45.904 65.622 ;
     RECT  45.904 42.336 46.073 55.704 ;
     RECT  46.073 51.888 46.253 55.704 ;
     RECT  45.904 3.024 46.541 9.144 ;
     RECT  45.904 15.744 46.613 41.16 ;
     RECT  45.904 61.392 46.657 65.592 ;
     RECT  46.541 4.992 46.835 9.144 ;
     RECT  45.904 56.832 46.865 60.36 ;
     RECT  46.657 61.392 46.865 65.208 ;
     RECT  46.865 64.272 46.901 65.208 ;
     RECT  46.865 56.832 46.937 59.304 ;
     RECT  46.865 60.288 47.041 60.36 ;
     RECT  46.613 34.368 47.149 41.16 ;
     RECT  46.073 42.336 47.149 50.856 ;
     RECT  47.149 34.368 47.153 50.856 ;
     RECT  46.937 56.832 47.189 58.92 ;
     RECT  47.153 46.32 47.317 50.856 ;
     RECT  46.253 51.888 47.317 55.32 ;
     RECT  45.904 10.32 47.333 14.664 ;
     RECT  47.333 12.288 47.365 14.664 ;
     RECT  46.613 15.744 47.365 33.048 ;
     RECT  47.189 56.832 47.369 57.048 ;
     RECT  46.835 4.992 47.411 6.312 ;
     RECT  47.369 56.832 47.441 56.904 ;
     RECT  47.041 60.288 47.441 60.408 ;
     RECT  47.411 4.992 47.513 5.64 ;
     RECT  47.441 60.336 47.513 60.408 ;
     RECT  47.365 12.288 47.549 33.048 ;
     RECT  47.317 46.32 47.585 55.32 ;
     RECT  46.541 3.024 47.612 3.96 ;
     RECT  47.189 58.704 47.621 58.92 ;
     RECT  47.621 58.704 47.657 58.728 ;
     RECT  47.153 34.368 47.689 45.288 ;
     RECT  47.441 56.832 47.725 56.856 ;
     RECT  47.585 47.856 47.795 55.32 ;
     RECT  47.795 47.952 47.833 55.32 ;
     RECT  47.725 56.544 47.833 56.856 ;
     RECT  47.612 2.4 47.873 3.96 ;
     RECT  47.873 2.4 48.017 3.912 ;
     RECT  46.865 61.392 48.085 63 ;
     RECT  47.549 23.088 48.125 32.76 ;
     RECT  47.833 47.952 48.125 56.856 ;
     RECT  46.835 7.584 48.265 9.144 ;
     RECT  47.689 33.84 48.265 45.288 ;
     RECT  47.585 46.32 48.265 46.776 ;
     RECT  48.125 47.952 48.333 51.24 ;
     RECT  48.265 33.84 48.341 46.776 ;
     RECT  46.901 64.272 48.409 64.92 ;
     RECT  48.125 52.464 48.445 56.856 ;
     RECT  48.085 60.96 48.449 63 ;
     RECT  48.409 64.272 48.469 65.592 ;
     RECT  48.469 64.176 48.515 65.592 ;
     RECT  48.125 30.912 48.517 32.76 ;
     RECT  48.445 52.464 48.529 57.048 ;
     RECT  47.549 12.288 48.553 22.056 ;
     RECT  48.125 23.088 48.553 29.88 ;
     RECT  48.265 6.864 48.557 9.144 ;
     RECT  48.341 33.84 48.557 46.536 ;
     RECT  48.557 6.864 48.593 8.52 ;
     RECT  48.553 12.288 48.665 29.88 ;
     RECT  48.449 60.96 48.697 61.608 ;
     RECT  48.557 33.84 48.701 43.368 ;
     RECT  48.665 13.584 48.755 29.88 ;
     RECT  48.017 2.4 48.809 3.384 ;
     RECT  48.701 33.84 48.809 43.128 ;
     RECT  48.755 13.584 48.845 29.832 ;
     RECT  48.517 30.912 48.853 32.856 ;
     RECT  48.809 33.84 48.853 42.792 ;
     RECT  47.333 10.32 48.908 11.208 ;
     RECT  48.665 12.288 48.908 12.456 ;
     RECT  48.853 59.472 48.913 59.496 ;
     RECT  48.449 62.688 48.947 63 ;
     RECT  48.515 64.176 48.947 65.16 ;
     RECT  47.513 5.04 48.949 5.64 ;
     RECT  48.593 6.864 48.949 6.888 ;
     RECT  48.913 58.848 48.953 59.496 ;
     RECT  48.947 62.832 48.989 63 ;
     RECT  48.333 47.952 49.021 49.032 ;
     RECT  48.989 62.928 49.021 63 ;
     RECT  48.947 64.896 49.025 65.16 ;
     RECT  48.845 29.664 49.061 29.832 ;
     RECT  48.845 13.584 49.097 28.44 ;
     RECT  48.853 30.912 49.097 42.792 ;
     RECT  48.809 3.024 49.129 3.384 ;
     RECT  49.097 30.912 49.201 42.552 ;
     RECT  49.021 62.928 49.201 63.096 ;
     RECT  49.097 15.024 49.235 28.44 ;
     RECT  49.129 3.024 49.309 3.72 ;
     RECT  49.235 15.024 49.385 24.456 ;
     RECT  48.953 58.848 49.417 59.256 ;
     RECT  48.697 60.48 49.417 61.608 ;
     RECT  48.949 5.04 49.421 6.888 ;
     RECT  49.235 25.536 49.427 28.44 ;
     RECT  49.309 3.024 49.489 3.864 ;
     RECT  49.385 15.024 49.523 24.264 ;
     RECT  49.201 30.816 49.571 42.552 ;
     RECT  49.021 47.76 49.597 49.032 ;
     RECT  48.333 50.112 49.597 51.24 ;
     RECT  48.557 44.592 49.601 46.536 ;
     RECT  49.097 13.584 49.637 13.704 ;
     RECT  48.593 7.968 49.673 8.52 ;
     RECT  49.025 65.136 49.673 65.16 ;
     RECT  49.673 8.448 49.777 8.52 ;
     RECT  49.571 40.8 49.781 42.552 ;
     RECT  49.417 58.08 49.781 59.256 ;
     RECT  49.417 60.384 49.781 61.608 ;
     RECT  48.908 10.32 49.817 12.456 ;
     RECT  49.489 3.024 49.885 3.96 ;
     RECT  49.597 47.76 49.885 51.24 ;
     RECT  49.201 62.928 49.889 63.336 ;
     RECT  49.427 27.984 49.921 28.44 ;
     RECT  49.061 29.664 49.921 29.736 ;
     RECT  49.781 60.384 49.957 60.456 ;
     RECT  48.529 52.464 50.029 56.856 ;
     RECT  49.885 47.28 50.101 51.24 ;
     RECT  50.029 52.464 50.101 57.336 ;
     RECT  49.885 2.688 50.204 3.96 ;
     RECT  49.601 44.592 50.209 45.624 ;
     RECT  49.921 27.984 50.353 29.736 ;
     RECT  49.571 30.816 50.353 39.48 ;
     RECT  50.204 2.688 50.425 4.104 ;
     RECT  49.421 5.28 50.425 6.888 ;
     RECT  49.427 25.536 50.425 26.808 ;
     RECT  50.353 27.984 50.425 39.48 ;
     RECT  49.777 8.448 50.461 9.048 ;
     RECT  49.817 10.32 50.461 12.312 ;
     RECT  50.425 2.688 50.533 6.888 ;
     RECT  49.781 58.656 50.569 59.256 ;
     RECT  49.957 60.336 50.569 60.456 ;
     RECT  50.101 47.28 50.641 57.336 ;
     RECT  49.781 40.992 50.677 42.552 ;
     RECT  50.425 25.536 50.713 39.48 ;
     RECT  49.669 13.536 50.773 13.56 ;
     RECT  50.677 40.992 50.857 43.32 ;
     RECT  50.461 8.448 50.869 12.312 ;
     RECT  50.209 44.448 50.869 45.624 ;
     RECT  50.641 46.608 50.869 57.336 ;
     RECT  49.523 15.312 50.965 24.264 ;
     RECT  50.713 25.488 50.965 39.48 ;
     RECT  50.965 15.312 51.001 39.48 ;
     RECT  50.533 2.688 51.008 6.936 ;
     RECT  50.869 7.968 51.008 12.312 ;
     RECT  50.773 13.536 51.008 13.704 ;
     RECT  51.001 14.928 51.008 39.48 ;
     RECT  50.857 40.944 51.008 43.32 ;
     RECT  50.869 44.448 51.008 57.336 ;
     RECT  50.569 58.656 51.008 60.456 ;
     RECT  49.993 61.872 51.008 61.896 ;
     RECT  49.889 62.928 51.008 63.288 ;
     RECT  50.857 65.664 51.008 65.688 ;
     RECT  51.008 2.148 51.112 65.892 ;
     RECT  51.112 2.418 51.304 65.688 ;
     RECT  51.304 34.512 51.401 51.24 ;
     RECT  51.401 48.192 51.437 51.24 ;
     RECT  51.304 62.4 51.437 63.096 ;
     RECT  51.304 64.368 51.443 65.688 ;
     RECT  51.401 34.512 51.581 47.112 ;
     RECT  51.304 8.976 51.617 9.384 ;
     RECT  51.304 22.752 51.689 32.616 ;
     RECT  51.581 34.512 51.689 43.896 ;
     RECT  51.437 62.4 51.725 63 ;
     RECT  51.304 13.968 52.013 21.624 ;
     RECT  52.013 13.968 52.049 19.368 ;
     RECT  51.304 12.48 52.333 12.936 ;
     RECT  52.049 13.968 52.333 19.224 ;
     RECT  51.725 62.4 52.333 62.52 ;
     RECT  52.333 12.48 52.337 19.224 ;
     RECT  52.013 20.448 52.405 21.624 ;
     RECT  51.689 22.752 52.405 32.568 ;
     RECT  51.581 44.88 52.405 47.112 ;
     RECT  51.437 48.384 52.405 51.24 ;
     RECT  51.304 10.656 52.441 11.448 ;
     RECT  51.304 52.464 52.445 56.088 ;
     RECT  51.617 8.976 52.513 9.144 ;
     RECT  52.405 20.448 52.553 32.568 ;
     RECT  52.553 23.328 52.588 32.568 ;
     RECT  52.553 20.448 52.625 22.104 ;
     RECT  51.689 34.896 52.657 43.896 ;
     RECT  52.405 44.88 52.657 51.24 ;
     RECT  52.445 52.464 52.657 54.744 ;
     RECT  52.657 44.88 52.661 54.744 ;
     RECT  52.588 23.376 52.765 32.568 ;
     RECT  51.443 64.944 52.796 65.4 ;
     RECT  51.304 57.312 52.801 60.408 ;
     RECT  52.657 34.128 52.841 43.896 ;
     RECT  52.801 57.312 52.909 60.6 ;
     RECT  52.333 62.304 52.909 62.52 ;
     RECT  51.304 3.696 52.933 5.592 ;
     RECT  52.445 56.064 52.981 56.088 ;
     RECT  52.909 57.312 52.981 60.648 ;
     RECT  52.765 23.376 53.017 33.048 ;
     RECT  52.841 34.128 53.017 37.032 ;
     RECT  52.841 38.016 53.021 43.896 ;
     RECT  52.981 56.064 53.021 60.648 ;
     RECT  52.909 62.304 53.057 62.808 ;
     RECT  52.933 3.696 53.089 6.024 ;
     RECT  52.513 8.544 53.197 9.144 ;
     RECT  52.441 10.176 53.197 11.448 ;
     RECT  52.796 64.896 53.233 65.4 ;
     RECT  53.021 56.064 53.261 60.696 ;
     RECT  52.337 15.792 53.305 19.224 ;
     RECT  53.261 56.064 53.345 61.032 ;
     RECT  53.233 64.32 53.377 65.4 ;
     RECT  53.017 23.376 53.381 37.032 ;
     RECT  53.345 56.064 53.413 60.696 ;
     RECT  53.021 38.112 53.485 43.896 ;
     RECT  53.089 2.832 53.557 6.024 ;
     RECT  53.377 7.392 53.557 7.416 ;
     RECT  53.197 8.544 53.557 11.448 ;
     RECT  52.337 12.48 53.557 13.992 ;
     RECT  53.557 7.392 53.603 13.992 ;
     RECT  53.603 7.968 53.629 13.992 ;
     RECT  53.629 7.968 53.633 14.184 ;
     RECT  52.625 20.544 53.665 22.104 ;
     RECT  53.485 38.112 53.737 43.944 ;
     RECT  52.661 45.216 53.737 54.744 ;
     RECT  53.057 62.304 53.737 62.712 ;
     RECT  53.737 38.112 53.741 54.744 ;
     RECT  53.557 2.736 53.773 6.024 ;
     RECT  53.633 9.024 53.845 14.184 ;
     RECT  53.381 23.376 53.881 24.552 ;
     RECT  53.305 15.456 53.917 19.224 ;
     RECT  53.381 25.632 54.001 37.032 ;
     RECT  54.001 25.632 54.065 34.152 ;
     RECT  54.001 35.28 54.133 37.032 ;
     RECT  53.741 38.112 54.133 41.256 ;
     RECT  53.741 42.24 54.133 54.744 ;
     RECT  53.413 55.776 54.133 60.696 ;
     RECT  54.065 29.472 54.173 34.152 ;
     RECT  53.377 63.696 54.173 65.4 ;
     RECT  54.173 29.664 54.281 34.152 ;
     RECT  54.133 42.24 54.281 60.696 ;
     RECT  54.281 50.352 54.323 60.696 ;
     RECT  53.737 62.208 54.335 62.712 ;
     RECT  54.173 63.696 54.335 64.968 ;
     RECT  54.281 42.24 54.353 49.08 ;
     RECT  53.773 2.736 54.389 6.168 ;
     RECT  53.881 23.232 54.421 24.552 ;
     RECT  54.065 25.632 54.421 28.296 ;
     RECT  54.323 57.744 54.425 60.696 ;
     RECT  54.335 62.208 54.461 64.968 ;
     RECT  53.845 9.024 54.533 14.376 ;
     RECT  54.425 57.936 54.565 60.696 ;
     RECT  54.353 46.8 54.685 49.08 ;
     RECT  53.917 15.456 54.709 19.272 ;
     RECT  53.665 20.4 54.709 22.104 ;
     RECT  53.633 7.968 54.745 7.992 ;
     RECT  54.533 9.024 54.745 10.44 ;
     RECT  54.709 15.456 54.745 22.104 ;
     RECT  54.745 7.968 54.749 10.44 ;
     RECT  54.389 2.88 54.781 6.168 ;
     RECT  54.749 8.064 54.962 10.44 ;
     RECT  54.685 46.8 55.001 48.984 ;
     RECT  54.133 35.28 55.069 41.256 ;
     RECT  54.353 42.24 55.069 43.848 ;
     RECT  54.962 8.064 55.181 8.088 ;
     RECT  54.533 11.424 55.181 14.376 ;
     RECT  54.421 23.232 55.213 28.296 ;
     RECT  55.213 23.232 55.253 28.536 ;
     RECT  54.353 45.216 55.393 45.816 ;
     RECT  55.001 46.8 55.393 48.84 ;
     RECT  55.393 45.216 55.429 48.84 ;
     RECT  55.253 23.232 55.433 26.76 ;
     RECT  54.745 15.456 55.537 22.248 ;
     RECT  55.429 45.024 55.645 48.84 ;
     RECT  55.069 35.28 55.681 43.848 ;
     RECT  55.645 44.928 55.681 48.84 ;
     RECT  54.281 29.808 55.717 34.152 ;
     RECT  55.681 35.28 55.717 48.84 ;
     RECT  54.962 9.072 55.861 10.44 ;
     RECT  55.181 11.424 55.861 12.552 ;
     RECT  55.181 13.632 55.861 14.376 ;
     RECT  55.537 15.456 55.861 22.824 ;
     RECT  54.565 57.936 56.041 61.224 ;
     RECT  54.461 62.208 56.041 64.92 ;
     RECT  55.717 29.808 56.077 48.84 ;
     RECT  55.861 13.632 56.149 22.824 ;
     RECT  55.253 27.744 56.221 28.536 ;
     RECT  56.077 29.808 56.221 49.032 ;
     RECT  54.323 50.352 56.245 56.76 ;
     RECT  56.041 57.936 56.245 64.92 ;
     RECT  54.781 2.88 56.408 6.84 ;
     RECT  56.293 7.968 56.408 7.992 ;
     RECT  55.861 9.072 56.408 12.552 ;
     RECT  56.149 13.584 56.408 22.824 ;
     RECT  55.433 24.192 56.408 26.76 ;
     RECT  56.221 27.744 56.408 49.032 ;
     RECT  56.245 50.352 56.408 64.92 ;
     RECT  56.408 2.148 56.512 65.892 ;
     RECT  56.512 2.418 56.704 65.622 ;
     RECT  56.704 52.752 56.837 54.696 ;
     RECT  56.704 61.632 56.867 64.92 ;
     RECT  56.704 33.888 56.909 47.928 ;
     RECT  56.704 14.88 56.981 31.272 ;
     RECT  56.909 40.032 56.981 47.928 ;
     RECT  56.704 2.88 57.017 13.896 ;
     RECT  57.017 2.88 57.053 7.992 ;
     RECT  56.867 61.92 57.089 64.92 ;
     RECT  56.981 15.024 57.107 31.272 ;
     RECT  57.053 3.408 57.161 7.992 ;
     RECT  56.981 41.856 57.161 47.928 ;
     RECT  57.089 62.016 57.161 64.92 ;
     RECT  56.909 33.888 57.305 38.76 ;
     RECT  57.161 62.784 57.305 64.92 ;
     RECT  57.161 6.816 57.347 7.992 ;
     RECT  57.107 15.024 57.377 31.224 ;
     RECT  56.704 32.304 57.377 32.376 ;
     RECT  56.981 40.032 57.377 40.44 ;
     RECT  57.377 18.192 57.413 31.224 ;
     RECT  57.413 18.192 57.449 18.792 ;
     RECT  57.377 40.416 57.449 40.44 ;
     RECT  56.704 56.16 57.485 60.072 ;
     RECT  57.305 33.888 57.587 35.88 ;
     RECT  57.377 15.024 57.593 17.16 ;
     RECT  57.305 62.976 57.593 64.92 ;
     RECT  56.704 50.112 57.665 51.768 ;
     RECT  57.305 37.056 57.701 38.76 ;
     RECT  57.587 35.232 57.737 35.88 ;
     RECT  57.377 32.352 57.769 32.376 ;
     RECT  57.587 33.888 57.769 34.2 ;
     RECT  57.593 16.032 57.809 17.16 ;
     RECT  56.837 52.848 57.841 54.696 ;
     RECT  57.665 50.448 57.877 51.768 ;
     RECT  57.841 52.752 57.877 54.696 ;
     RECT  57.877 50.448 58.057 54.696 ;
     RECT  57.485 56.16 58.057 58.824 ;
     RECT  57.701 37.056 58.061 38.712 ;
     RECT  57.347 7.104 58.117 7.992 ;
     RECT  57.017 9.12 58.117 13.896 ;
     RECT  58.057 61.152 58.129 61.704 ;
     RECT  57.413 19.776 58.133 31.224 ;
     RECT  58.117 7.104 58.201 13.896 ;
     RECT  58.057 50.448 58.241 58.824 ;
     RECT  57.161 41.856 58.273 46.728 ;
     RECT  58.133 21.216 58.381 31.224 ;
     RECT  57.769 32.352 58.381 34.2 ;
     RECT  58.061 37.056 58.381 38.232 ;
     RECT  57.449 18.24 58.417 18.792 ;
     RECT  58.133 19.776 58.417 20.04 ;
     RECT  57.161 3.408 58.453 5.832 ;
     RECT  58.201 7.104 58.453 13.944 ;
     RECT  58.129 60.432 58.457 61.704 ;
     RECT  58.453 3.408 58.525 13.944 ;
     RECT  57.593 15.024 58.525 15.048 ;
     RECT  58.457 61.152 58.597 61.704 ;
     RECT  58.597 61.152 58.601 61.8 ;
     RECT  58.273 41.856 58.633 46.92 ;
     RECT  57.593 62.976 58.633 64.248 ;
     RECT  57.809 16.032 58.637 16.92 ;
     RECT  57.161 47.904 58.645 47.928 ;
     RECT  58.237 49.008 58.645 49.032 ;
     RECT  58.601 61.44 58.691 61.8 ;
     RECT  58.381 21.216 58.709 34.2 ;
     RECT  58.633 41.184 58.741 46.92 ;
     RECT  58.645 47.904 58.741 49.032 ;
     RECT  58.241 52.176 58.781 58.824 ;
     RECT  58.691 61.44 58.817 61.704 ;
     RECT  58.741 41.184 58.883 49.032 ;
     RECT  58.525 3.408 58.885 15.048 ;
     RECT  58.637 16.032 58.885 16.632 ;
     RECT  58.883 41.184 58.924 45.864 ;
     RECT  58.417 18.24 58.925 20.04 ;
     RECT  58.883 46.896 58.925 49.032 ;
     RECT  58.925 48.192 58.944 49.032 ;
     RECT  58.709 23.28 58.961 34.2 ;
     RECT  58.961 23.28 59.069 30.168 ;
     RECT  58.781 52.176 59.069 56.376 ;
     RECT  58.925 19.776 59.101 20.04 ;
     RECT  58.709 21.216 59.101 21.96 ;
     RECT  59.069 23.28 59.105 28.68 ;
     RECT  58.781 57.456 59.18 58.824 ;
     RECT  58.633 62.976 59.209 65.016 ;
     RECT  58.885 3.408 59.213 16.632 ;
     RECT  58.924 41.184 59.213 45.576 ;
     RECT  58.925 18.24 59.221 18.264 ;
     RECT  59.221 18.144 59.267 18.264 ;
     RECT  59.18 57.456 59.267 59.88 ;
     RECT  59.209 62.832 59.267 65.016 ;
     RECT  58.961 31.2 59.269 34.2 ;
     RECT  57.737 35.232 59.269 35.256 ;
     RECT  58.381 36.816 59.269 38.232 ;
     RECT  59.267 59.856 59.293 59.88 ;
     RECT  59.213 3.408 59.315 16.248 ;
     RECT  59.315 3.408 59.321 10.104 ;
     RECT  59.105 23.28 59.321 26.616 ;
     RECT  59.269 31.2 59.356 35.256 ;
     RECT  59.069 56.064 59.357 56.376 ;
     RECT  59.267 18.144 59.389 18.168 ;
     RECT  59.213 41.184 59.389 43.896 ;
     RECT  59.321 7.296 59.429 9.672 ;
     RECT  59.389 41.04 59.465 43.896 ;
     RECT  59.315 11.136 59.501 16.248 ;
     RECT  58.925 46.896 59.501 47.064 ;
     RECT  59.389 17.616 59.573 18.168 ;
     RECT  59.501 12.912 59.609 16.248 ;
     RECT  59.321 3.408 59.653 5.832 ;
     RECT  59.269 36.48 59.681 38.232 ;
     RECT  59.069 52.176 59.681 54.888 ;
     RECT  59.653 2.832 59.74 5.832 ;
     RECT  58.241 50.448 59.749 51 ;
     RECT  59.681 52.176 59.749 54.744 ;
     RECT  58.817 61.44 59.749 61.464 ;
     RECT  59.101 19.776 59.821 21.96 ;
     RECT  59.321 23.28 59.821 25.128 ;
     RECT  59.357 56.112 59.825 56.376 ;
     RECT  59.429 8.544 59.853 9.672 ;
     RECT  59.609 13.008 59.861 16.248 ;
     RECT  59.501 46.896 59.897 46.92 ;
     RECT  58.944 48.192 59.897 48.696 ;
     RECT  59.069 29.712 59.933 30.168 ;
     RECT  59.681 36.816 59.933 38.232 ;
     RECT  59.749 61.008 60.001 61.464 ;
     RECT  59.749 50.448 60.073 54.744 ;
     RECT  59.356 35.232 60.077 35.256 ;
     RECT  59.933 36.816 60.077 37.608 ;
     RECT  60.001 61.008 60.109 61.512 ;
     RECT  59.465 41.04 60.149 42.648 ;
     RECT  59.713 39.696 60.284 39.72 ;
     RECT  60.149 41.04 60.284 42.216 ;
     RECT  59.267 57.456 60.289 58.824 ;
     RECT  59.267 62.832 60.289 63.816 ;
     RECT  59.267 64.992 60.289 65.016 ;
     RECT  60.289 62.832 60.329 65.016 ;
     RECT  59.861 13.056 60.361 16.248 ;
     RECT  59.213 45.024 60.361 45.576 ;
     RECT  60.284 39.696 60.371 42.216 ;
     RECT  59.429 7.296 60.397 7.32 ;
     RECT  59.853 8.544 60.397 9.096 ;
     RECT  60.109 61.008 60.397 61.752 ;
     RECT  60.361 13.056 60.421 16.632 ;
     RECT  59.573 17.616 60.421 17.64 ;
     RECT  60.361 45.024 60.433 46.584 ;
     RECT  59.933 29.712 60.437 30.12 ;
     RECT  60.077 36.816 60.437 37.368 ;
     RECT  59.321 26.256 60.469 26.616 ;
     RECT  59.105 27.648 60.469 28.68 ;
     RECT  59.465 43.776 60.469 43.896 ;
     RECT  59.501 11.136 60.541 11.688 ;
     RECT  60.289 57.072 60.541 59.208 ;
     RECT  60.397 60.24 60.541 61.752 ;
     RECT  60.469 43.488 60.563 43.896 ;
     RECT  59.821 19.776 60.577 25.128 ;
     RECT  60.563 43.776 60.581 43.896 ;
     RECT  60.541 57.072 60.617 61.752 ;
     RECT  59.356 31.2 60.685 34.2 ;
     RECT  60.397 7.296 60.689 9.096 ;
     RECT  60.421 13.056 60.689 17.64 ;
     RECT  60.689 7.296 60.725 9 ;
     RECT  60.469 26.256 60.725 28.68 ;
     RECT  60.073 49.536 60.725 54.744 ;
     RECT  60.577 19.776 60.797 25.224 ;
     RECT  60.725 26.496 60.797 28.68 ;
     RECT  60.725 51.312 60.937 54.744 ;
     RECT  60.541 55.776 60.937 55.8 ;
     RECT  59.74 3.072 60.949 5.832 ;
     RECT  60.725 7.296 60.949 8.568 ;
     RECT  60.797 19.776 60.973 21.96 ;
     RECT  60.433 44.928 61.045 46.584 ;
     RECT  60.437 36.816 61.081 37.032 ;
     RECT  60.689 13.056 61.153 17.208 ;
     RECT  60.949 3.072 61.225 8.568 ;
     RECT  60.371 39.696 61.261 39.72 ;
     RECT  59.897 48.192 61.261 48.504 ;
     RECT  60.725 49.536 61.261 50.328 ;
     RECT  60.973 18.816 61.333 21.96 ;
     RECT  61.261 39.312 61.333 39.72 ;
     RECT  60.371 40.992 61.333 42.216 ;
     RECT  60.541 11.136 61.405 11.736 ;
     RECT  61.333 39.312 61.405 42.216 ;
     RECT  61.405 10.8 61.477 11.736 ;
     RECT  60.437 29.856 61.585 30.12 ;
     RECT  60.685 31.2 61.585 34.968 ;
     RECT  60.329 62.976 61.657 64.392 ;
     RECT  61.477 10.608 61.669 11.736 ;
     RECT  61.669 10.608 61.693 11.784 ;
     RECT  61.693 10.176 61.729 11.784 ;
     RECT  61.585 29.856 61.729 34.968 ;
     RECT  61.081 36.144 61.729 37.032 ;
     RECT  61.729 29.856 61.765 37.032 ;
     RECT  61.225 2.592 61.808 8.568 ;
     RECT  61.729 9.792 61.808 11.784 ;
     RECT  61.153 12.864 61.808 17.208 ;
     RECT  61.333 18.192 61.808 21.96 ;
     RECT  60.797 22.992 61.808 25.224 ;
     RECT  60.797 26.544 61.808 28.68 ;
     RECT  61.765 29.856 61.808 37.128 ;
     RECT  61.405 39.312 61.808 42.6 ;
     RECT  60.581 43.872 61.808 43.896 ;
     RECT  61.045 44.928 61.808 47.208 ;
     RECT  61.261 48.192 61.808 50.328 ;
     RECT  60.937 51.312 61.808 55.8 ;
     RECT  60.617 57.072 61.808 61.464 ;
     RECT  61.657 62.448 61.808 64.392 ;
     RECT  61.808 2.148 61.912 65.892 ;
     RECT  61.912 2.418 62.104 65.622 ;
     RECT  62.104 14.736 62.129 26.664 ;
     RECT  62.104 58.464 62.237 62.472 ;
     RECT  62.104 43.824 62.243 48.216 ;
     RECT  62.104 33.072 62.309 33.096 ;
     RECT  62.243 43.824 62.309 47.064 ;
     RECT  62.104 2.592 62.381 6.648 ;
     RECT  62.104 34.08 62.381 34.2 ;
     RECT  62.104 42.576 62.453 42.744 ;
     RECT  62.129 14.736 62.489 26.232 ;
     RECT  62.309 43.872 62.489 47.064 ;
     RECT  62.489 44.928 62.597 47.064 ;
     RECT  62.104 49.2 62.669 50.664 ;
     RECT  62.489 14.736 62.675 18.408 ;
     RECT  62.104 35.952 62.675 37.08 ;
     RECT  62.675 37.056 62.677 37.08 ;
     RECT  62.489 19.536 62.705 26.232 ;
     RECT  62.675 14.736 62.723 18.264 ;
     RECT  62.104 7.92 62.741 13.512 ;
     RECT  62.104 27.888 62.741 30.6 ;
     RECT  62.104 55.776 62.741 55.8 ;
     RECT  62.237 58.464 62.741 60.504 ;
     RECT  62.705 20.064 62.777 26.232 ;
     RECT  62.243 48.192 62.849 48.216 ;
     RECT  62.381 2.592 62.857 5.784 ;
     RECT  62.777 20.064 62.915 25.464 ;
     RECT  62.741 7.92 62.921 9.816 ;
     RECT  62.741 11.664 62.921 13.512 ;
     RECT  62.104 63.792 62.921 64.392 ;
     RECT  62.723 14.736 62.957 17.64 ;
     RECT  62.921 13.392 62.993 13.512 ;
     RECT  62.915 21.072 62.993 25.464 ;
     RECT  62.857 2.592 63.029 4.536 ;
     RECT  62.993 13.488 63.029 13.512 ;
     RECT  62.741 27.888 63.029 28.488 ;
     RECT  62.741 58.464 63.029 59.496 ;
     RECT  62.669 49.2 63.137 49.224 ;
     RECT  62.104 54.72 63.137 54.744 ;
     RECT  62.993 21.936 63.155 25.464 ;
     RECT  63.155 22.176 63.203 25.464 ;
     RECT  62.921 11.664 63.209 11.88 ;
     RECT  62.104 31.728 63.209 32.088 ;
     RECT  62.669 50.544 63.241 50.664 ;
     RECT  62.741 29.856 63.245 30.6 ;
     RECT  63.029 2.784 63.251 4.536 ;
     RECT  63.029 27.888 63.313 28.44 ;
     RECT  63.203 22.704 63.317 25.464 ;
     RECT  63.245 29.856 63.317 29.88 ;
     RECT  62.104 52.176 63.317 53.592 ;
     RECT  63.209 31.968 63.349 32.088 ;
     RECT  62.104 38.784 63.353 41.16 ;
     RECT  62.597 45.696 63.353 47.064 ;
     RECT  63.317 52.416 63.353 53.592 ;
     RECT  62.857 5.76 63.389 5.784 ;
     RECT  62.957 15.312 63.389 17.64 ;
     RECT  63.349 31.968 63.389 32.472 ;
     RECT  62.381 34.176 63.421 34.2 ;
     RECT  63.209 11.712 63.425 11.88 ;
     RECT  62.675 35.952 63.461 35.976 ;
     RECT  62.921 63.792 63.461 63.816 ;
     RECT  63.421 34.176 63.493 34.536 ;
     RECT  62.237 61.872 63.493 62.472 ;
     RECT  63.353 40.032 63.497 41.16 ;
     RECT  63.389 15.984 63.569 17.64 ;
     RECT  63.317 24.912 63.569 25.464 ;
     RECT  63.241 50.544 63.601 51.192 ;
     RECT  63.169 48.432 63.605 48.456 ;
     RECT  63.029 58.464 63.637 58.776 ;
     RECT  63.251 2.784 63.749 3.624 ;
     RECT  63.389 32.016 63.749 32.472 ;
     RECT  63.569 17.04 63.893 17.64 ;
     RECT  63.497 40.128 63.893 41.16 ;
     RECT  63.205 60.528 63.893 60.552 ;
     RECT  63.749 32.352 63.929 32.472 ;
     RECT  63.893 41.136 63.929 41.16 ;
     RECT  62.921 7.92 63.997 9.24 ;
     RECT  63.997 7.92 64.001 10.152 ;
     RECT  63.457 38.736 64.001 38.76 ;
     RECT  63.925 44.64 64.028 44.664 ;
     RECT  63.569 25.44 64.037 25.464 ;
     RECT  62.453 42.72 64.069 42.744 ;
     RECT  63.749 2.784 64.073 2.808 ;
     RECT  64.001 7.92 64.105 8.232 ;
     RECT  63.929 32.448 64.141 32.472 ;
     RECT  63.493 33.6 64.141 34.536 ;
     RECT  63.493 61.536 64.141 62.472 ;
     RECT  62.915 20.064 64.177 20.088 ;
     RECT  64.069 42.432 64.177 42.744 ;
     RECT  64.028 44.64 64.177 45.336 ;
     RECT  63.313 26.928 64.181 28.44 ;
     RECT  63.353 46.56 64.217 47.064 ;
     RECT  63.317 22.704 64.253 23.688 ;
     RECT  63.893 17.088 64.325 17.64 ;
     RECT  64.177 42.432 64.357 43.368 ;
     RECT  64.105 7.344 64.397 8.232 ;
     RECT  64.177 20.064 64.397 20.568 ;
     RECT  64.177 44.592 64.397 45.336 ;
     RECT  64.357 42.048 64.403 43.368 ;
     RECT  64.397 44.928 64.403 45.336 ;
     RECT  64.217 47.04 64.405 47.064 ;
     RECT  63.601 50.544 64.405 51.288 ;
     RECT  63.353 52.416 64.405 52.44 ;
     RECT  64.397 8.208 64.433 8.232 ;
     RECT  64.253 22.752 64.433 23.688 ;
     RECT  64.141 32.448 64.433 34.536 ;
     RECT  63.637 57.84 64.433 58.776 ;
     RECT  64.405 47.04 64.451 47.448 ;
     RECT  64.364 48.96 64.451 48.984 ;
     RECT  64.405 50.544 64.461 52.44 ;
     RECT  64.433 22.752 64.469 22.872 ;
     RECT  64.141 61.536 64.501 63.288 ;
     RECT  63.425 11.856 64.537 11.88 ;
     RECT  64.397 20.064 64.541 20.088 ;
     RECT  64.537 11.856 64.609 12.744 ;
     RECT  64.469 22.848 64.613 22.872 ;
     RECT  63.353 53.568 64.645 53.592 ;
     RECT  64.249 55.056 64.645 55.08 ;
     RECT  64.325 17.616 64.649 17.64 ;
     RECT  64.433 33.6 64.649 34.536 ;
     RECT  64.001 9.84 64.681 10.152 ;
     RECT  64.681 9.84 64.685 10.872 ;
     RECT  64.573 26.784 64.685 26.808 ;
     RECT  64.181 27.888 64.685 28.44 ;
     RECT  64.461 50.688 64.685 52.44 ;
     RECT  64.645 53.568 64.685 55.08 ;
     RECT  64.285 5.136 64.721 5.16 ;
     RECT  63.569 15.984 64.721 16.008 ;
     RECT  64.501 60.768 64.721 63.288 ;
     RECT  64.721 60.768 64.739 60.792 ;
     RECT  64.609 11.856 64.757 13.704 ;
     RECT  64.433 32.448 64.757 32.472 ;
     RECT  64.649 34.512 64.757 34.536 ;
     RECT  64.403 42.048 64.757 42.072 ;
     RECT  64.403 43.344 64.757 43.368 ;
     RECT  64.403 44.928 64.757 44.952 ;
     RECT  63.637 56.064 64.757 56.088 ;
     RECT  64.433 57.84 64.757 58.104 ;
     RECT  64.721 63.264 64.757 63.288 ;
     RECT  64.693 59.616 64.78 59.64 ;
     RECT  64.685 10.848 64.787 10.872 ;
     RECT  64.757 11.856 64.787 11.88 ;
     RECT  64.757 13.056 64.787 13.704 ;
     RECT  64.685 54.096 64.787 55.08 ;
     RECT  64.685 9.84 64.793 9.864 ;
     RECT  63.637 37.008 64.793 37.032 ;
     RECT  64.451 47.424 64.793 47.448 ;
     RECT  64.685 50.688 64.793 51.24 ;
     RECT  64.787 13.056 64.828 13.08 ;
     RECT  64.685 27.888 64.829 27.912 ;
     RECT  64.757 58.08 64.829 58.104 ;
     RECT  63.893 40.128 64.901 40.152 ;
     RECT  64.793 51.216 64.973 51.24 ;
     RECT  64.681 24.048 65.009 24.072 ;
    LAYER M5 ;
     RECT  34.32 0.016 36.648 0.131 ;
     RECT  34.416 0.131 36.648 0.323 ;
     RECT  34.416 0.323 35.592 0.563 ;
     RECT  35.28 0.563 35.304 1.763 ;
     RECT  2.4 2.137 2.52 2.151 ;
     RECT  7.8 2.137 7.92 2.151 ;
     RECT  13.2 2.137 13.32 2.151 ;
     RECT  18.6 2.137 18.72 2.151 ;
     RECT  24 2.137 24.12 2.151 ;
     RECT  29.4 2.137 29.52 2.151 ;
     RECT  40.2 2.137 40.32 2.151 ;
     RECT  45.6 2.137 45.72 2.151 ;
     RECT  51 2.137 51.12 2.151 ;
     RECT  56.4 2.137 56.52 2.151 ;
     RECT  61.8 2.137 61.92 2.151 ;
     RECT  13.2 2.151 13.512 2.245 ;
     RECT  18.6 2.151 18.912 2.245 ;
     RECT  24 2.151 24.312 2.245 ;
     RECT  51 2.151 51.312 2.677 ;
     RECT  13.2 2.245 14.28 2.821 ;
     RECT  18 2.245 18.912 2.821 ;
     RECT  24 2.245 25.368 2.821 ;
     RECT  7.8 2.151 8.112 3.109 ;
     RECT  17.712 2.821 18.912 3.109 ;
     RECT  40.2 2.151 40.512 3.157 ;
     RECT  32.064 2.821 32.088 3.349 ;
     RECT  2.4 2.151 2.712 3.397 ;
     RECT  13.2 2.821 15 3.397 ;
     RECT  59.664 2.821 59.688 3.443 ;
     RECT  9.936 2.773 9.96 3.877 ;
     RECT  12.528 3.397 15 3.923 ;
     RECT  24 2.821 26.184 3.973 ;
     RECT  53.568 2.725 53.592 4.019 ;
     RECT  28.08 2.245 28.104 4.067 ;
     RECT  39.888 3.157 40.512 4.069 ;
     RECT  43.632 2.245 43.656 4.115 ;
     RECT  50.256 2.677 51.312 4.115 ;
     RECT  55.392 3.397 55.416 4.117 ;
     RECT  56.4 2.151 56.712 4.117 ;
     RECT  57.792 3.925 57.816 4.117 ;
     RECT  39.408 4.069 40.512 4.165 ;
     RECT  38.448 4.165 40.512 4.211 ;
     RECT  20.208 3.397 20.232 4.213 ;
     RECT  42.192 3.637 42.216 4.213 ;
     RECT  14.736 3.923 15 4.403 ;
     RECT  55.392 4.117 57.816 4.403 ;
     RECT  60.288 3.973 60.312 4.453 ;
     RECT  61.8 2.151 62.112 4.453 ;
     RECT  24 3.973 26.76 4.501 ;
     RECT  30.912 4.213 30.936 4.501 ;
     RECT  32.064 3.349 32.76 4.501 ;
     RECT  34.8 2.137 35.112 4.501 ;
     RECT  60.288 4.453 62.112 4.501 ;
     RECT  63.216 2.773 63.24 4.501 ;
     RECT  24 4.501 27.624 4.547 ;
     RECT  60.288 4.501 63.24 4.547 ;
     RECT  9.744 3.877 9.96 4.597 ;
     RECT  17.664 3.109 18.912 4.741 ;
     RECT  20.208 4.213 20.28 4.741 ;
     RECT  21.648 4.357 21.672 4.741 ;
     RECT  29.4 2.151 29.712 4.741 ;
     RECT  30.912 4.501 32.76 4.741 ;
     RECT  24 4.547 26.184 4.835 ;
     RECT  34.08 4.501 35.112 4.837 ;
     RECT  9.12 4.597 9.96 4.885 ;
     RECT  11.424 4.357 11.448 4.885 ;
     RECT  16.272 2.821 16.296 4.981 ;
     RECT  17.616 4.741 18.912 4.981 ;
     RECT  20.208 4.741 21.672 5.029 ;
     RECT  9.12 4.885 11.448 5.077 ;
     RECT  12.528 3.923 13.512 5.077 ;
     RECT  47.664 2.389 47.688 5.077 ;
     RECT  47.376 5.077 47.688 5.123 ;
     RECT  55.392 4.403 55.416 5.171 ;
     RECT  60.288 4.547 62.808 5.171 ;
     RECT  29.4 4.741 32.76 5.219 ;
     RECT  56.4 4.403 57.816 5.267 ;
     RECT  9.12 5.077 13.512 5.365 ;
     RECT  14.736 4.403 14.76 5.365 ;
     RECT  24 4.835 25.944 5.365 ;
     RECT  36.672 3.925 36.696 5.365 ;
     RECT  27.456 4.547 27.624 5.461 ;
     RECT  36.672 5.365 36.84 5.557 ;
     RECT  9.12 5.365 14.76 5.651 ;
     RECT  60.288 5.171 62.112 5.747 ;
     RECT  34.08 4.837 35.256 5.749 ;
     RECT  60.864 5.747 62.112 5.795 ;
     RECT  27.456 5.461 28.248 5.845 ;
     RECT  29.4 5.219 30.744 5.845 ;
     RECT  41.808 4.213 42.216 5.941 ;
     RECT  43.344 4.549 43.368 5.941 ;
     RECT  9.12 5.651 10.632 6.035 ;
     RECT  27.456 5.845 30.744 6.035 ;
     RECT  52.944 5.173 52.968 6.035 ;
     RECT  16.272 4.981 18.912 6.037 ;
     RECT  20.208 5.029 22.392 6.037 ;
     RECT  33.744 5.749 35.256 6.037 ;
     RECT  36.672 5.557 37.416 6.037 ;
     RECT  23.568 5.365 25.944 6.229 ;
     RECT  27.456 6.035 28.248 6.323 ;
     RECT  2.4 3.397 3.48 6.325 ;
     RECT  41.808 5.941 43.368 6.371 ;
     RECT  23.568 6.229 26.184 6.373 ;
     RECT  16.272 6.037 22.392 6.419 ;
     RECT  45.6 2.151 45.912 6.613 ;
     RECT  47.376 5.123 47.4 6.613 ;
     RECT  9.648 6.035 10.632 6.803 ;
     RECT  23.376 6.373 26.184 6.805 ;
     RECT  29.4 6.035 30.744 6.805 ;
     RECT  32.256 5.219 32.76 6.805 ;
     RECT  55.296 5.605 55.32 6.851 ;
     RECT  16.272 6.419 20.808 6.899 ;
     RECT  29.4 6.805 32.76 6.899 ;
     RECT  50.88 4.115 51.312 6.901 ;
     RECT  17.616 6.899 20.808 7.091 ;
     RECT  23.376 6.805 26.664 7.139 ;
     RECT  7.68 3.109 8.112 7.381 ;
     RECT  31.392 6.899 32.76 7.381 ;
     RECT  33.744 6.037 37.416 7.381 ;
     RECT  38.448 4.211 38.472 7.381 ;
     RECT  22.176 6.419 22.392 7.427 ;
     RECT  41.808 6.371 43.32 7.475 ;
     RECT  45.6 6.613 47.4 7.619 ;
     RECT  41.808 7.475 42.456 7.667 ;
     RECT  28.224 6.323 28.248 7.717 ;
     RECT  29.4 6.899 30.216 7.717 ;
     RECT  28.224 7.717 30.216 7.861 ;
     RECT  31.392 7.381 37.416 7.861 ;
     RECT  9.648 6.803 10.248 7.907 ;
     RECT  28.224 7.861 37.416 7.909 ;
     RECT  38.4 7.381 38.472 7.909 ;
     RECT  40.2 4.211 40.512 7.909 ;
     RECT  17.616 7.091 19.416 8.003 ;
     RECT  53.568 7.381 53.592 8.003 ;
     RECT  7.008 7.381 8.112 8.195 ;
     RECT  40.2 7.909 41.064 8.389 ;
     RECT  22.176 7.427 22.2 8.435 ;
     RECT  23.664 7.139 26.664 8.435 ;
     RECT  50.784 6.901 51.312 8.437 ;
     RECT  16.272 6.899 16.296 8.485 ;
     RECT  28.224 7.909 38.472 8.485 ;
     RECT  56.4 5.267 57.336 8.485 ;
     RECT  58.32 7.381 58.344 8.485 ;
     RECT  39.552 8.389 41.064 8.531 ;
     RECT  60.96 5.795 62.112 8.579 ;
     RECT  48.48 7.957 48.504 8.675 ;
     RECT  39.888 8.531 41.064 8.867 ;
     RECT  20.4 7.091 20.808 8.917 ;
     RECT  23.76 8.435 26.664 9.059 ;
     RECT  56.4 8.485 58.344 9.061 ;
     RECT  10.224 7.907 10.248 9.109 ;
     RECT  63.312 8.485 63.336 9.251 ;
     RECT  7.68 8.195 8.112 9.253 ;
     RECT  20.352 8.917 20.808 9.397 ;
     RECT  42.432 7.667 42.456 9.541 ;
     RECT  9.744 9.109 10.248 9.587 ;
     RECT  11.952 5.651 14.76 9.587 ;
     RECT  20.352 9.397 21.72 9.587 ;
     RECT  21.696 9.587 21.72 9.637 ;
     RECT  55.872 9.061 58.344 9.637 ;
     RECT  59.76 9.061 59.784 9.637 ;
     RECT  55.872 9.637 59.784 9.683 ;
     RECT  27.744 8.485 38.472 9.731 ;
     RECT  50.736 8.437 51.312 9.779 ;
     RECT  55.872 9.683 59.304 9.827 ;
     RECT  2.4 6.325 3.96 9.925 ;
     RECT  42.096 9.541 42.456 10.067 ;
     RECT  16.272 8.485 16.392 10.117 ;
     RECT  17.616 8.003 18.912 10.117 ;
     RECT  20.352 9.587 20.568 10.117 ;
     RECT  23.76 9.059 26.568 10.357 ;
     RECT  7.392 9.253 8.112 10.597 ;
     RECT  42.096 10.067 42.168 10.597 ;
     RECT  23.76 10.357 26.616 10.645 ;
     RECT  27.744 9.731 31.368 10.645 ;
     RECT  16.272 10.117 16.44 10.693 ;
     RECT  17.616 10.117 20.568 10.693 ;
     RECT  16.272 10.693 20.568 10.739 ;
     RECT  55.872 9.827 56.856 10.739 ;
     RECT  9.744 9.587 9.768 10.741 ;
     RECT  43.536 9.349 43.56 10.741 ;
     RECT  11.952 9.587 14.712 10.789 ;
     RECT  39.888 8.867 40.512 10.789 ;
     RECT  41.952 10.597 42.168 10.789 ;
     RECT  50.784 9.779 51.312 10.789 ;
     RECT  53.856 9.781 53.88 10.789 ;
     RECT  61.8 8.579 62.112 10.789 ;
     RECT  58.128 9.827 59.304 10.883 ;
     RECT  11.952 10.789 14.808 10.885 ;
     RECT  23.76 10.645 31.368 10.885 ;
     RECT  32.352 9.731 38.472 10.885 ;
     RECT  21.696 9.637 22.248 10.931 ;
     RECT  43.536 10.741 44.376 10.931 ;
     RECT  45.6 7.619 46.824 10.933 ;
     RECT  45.6 10.933 47.016 10.979 ;
     RECT  20.448 10.739 20.568 11.075 ;
     RECT  53.04 10.789 53.88 11.173 ;
     RECT  2.4 9.925 4.632 11.363 ;
     RECT  23.76 10.885 38.472 11.365 ;
     RECT  39.888 10.789 42.168 11.365 ;
     RECT  23.76 11.365 42.168 11.411 ;
     RECT  7.392 10.597 8.568 11.413 ;
     RECT  50.784 10.789 51.432 11.459 ;
     RECT  53.04 11.173 54.264 11.459 ;
     RECT  58.128 10.883 58.344 11.459 ;
     RECT  11.664 10.885 14.808 11.461 ;
     RECT  23.76 11.411 39 11.507 ;
     RECT  61.8 10.789 62.28 11.653 ;
     RECT  6.576 11.413 8.568 11.699 ;
     RECT  18.48 10.739 19.464 11.699 ;
     RECT  43.872 10.931 44.376 11.699 ;
     RECT  48.96 10.309 48.984 11.699 ;
     RECT  61.68 11.653 62.28 11.747 ;
     RECT  2.4 11.363 3.96 11.795 ;
     RECT  11.664 11.461 15 11.797 ;
     RECT  9.744 10.741 10.248 11.843 ;
     RECT  18.48 11.699 19.032 12.083 ;
     RECT  21.792 10.931 22.248 12.229 ;
     RECT  16.272 10.739 17.208 12.325 ;
     RECT  18.48 12.083 18.912 12.325 ;
     RECT  11.424 11.797 15 12.371 ;
     RECT  21.792 12.229 22.776 12.373 ;
     RECT  23.76 11.507 30.408 12.373 ;
     RECT  45.6 10.979 45.912 12.469 ;
     RECT  46.992 10.979 47.016 12.515 ;
     RECT  11.424 12.371 11.688 12.563 ;
     RECT  12.864 12.371 15 12.611 ;
     RECT  31.536 11.507 32.76 12.755 ;
     RECT  20.448 11.075 20.472 12.805 ;
     RECT  33.936 11.507 39 12.805 ;
     RECT  40.2 11.411 42.168 12.805 ;
     RECT  33.936 12.805 42.168 12.851 ;
     RECT  9.744 11.843 9.816 12.901 ;
     RECT  50.784 11.459 51.312 12.901 ;
     RECT  16.272 12.325 18.912 12.949 ;
     RECT  2.4 11.795 3.48 12.995 ;
     RECT  21.792 12.373 30.408 12.995 ;
     RECT  6.576 11.699 8.112 13.043 ;
     RECT  21.792 12.995 27.384 13.043 ;
     RECT  9.36 12.901 9.816 13.045 ;
     RECT  28.416 12.995 30.408 13.045 ;
     RECT  41.712 12.851 42.168 13.045 ;
     RECT  43.872 11.699 43.896 13.045 ;
     RECT  41.712 13.045 43.896 13.091 ;
     RECT  58.128 11.459 58.152 13.091 ;
     RECT  26.256 13.043 27.384 13.139 ;
     RECT  31.968 12.755 32.76 13.139 ;
     RECT  26.592 13.139 27.384 13.187 ;
     RECT  15.984 12.949 18.912 13.379 ;
     RECT  61.68 11.747 62.232 13.523 ;
     RECT  20.304 12.805 20.472 13.573 ;
     RECT  44.976 12.469 45.912 13.573 ;
     RECT  33.936 12.851 40.512 13.619 ;
     RECT  56.208 10.739 56.856 13.621 ;
     RECT  2.4 12.995 3.432 13.715 ;
     RECT  34.08 13.619 40.512 13.715 ;
     RECT  50.784 12.901 51.912 13.715 ;
     RECT  64.752 10.837 64.776 13.715 ;
     RECT  61.68 13.523 62.112 13.717 ;
     RECT  19.968 13.573 20.472 13.765 ;
     RECT  21.792 13.043 24.6 13.765 ;
     RECT  19.968 13.765 24.6 13.859 ;
     RECT  51 13.715 51.912 14.003 ;
     RECT  26.592 13.187 27 14.051 ;
     RECT  14.976 12.611 15 14.053 ;
     RECT  15.984 13.379 16.248 14.053 ;
     RECT  39.456 13.715 40.512 14.053 ;
     RECT  41.712 13.091 43.128 14.053 ;
     RECT  39.456 14.053 43.128 14.147 ;
     RECT  7.2 13.043 8.112 14.291 ;
     RECT  20.976 13.859 24.6 14.291 ;
     RECT  26.976 14.051 27 14.291 ;
     RECT  59.808 13.045 59.832 14.291 ;
     RECT  17.376 13.379 18.912 14.293 ;
     RECT  19.968 13.859 19.992 14.293 ;
     RECT  17.376 14.293 19.992 14.339 ;
     RECT  23.568 14.291 24.6 14.485 ;
     RECT  39.456 14.147 42.168 14.531 ;
     RECT  9.36 13.045 10.104 14.629 ;
     RECT  39.456 14.531 41.976 14.675 ;
     RECT  12.864 12.611 13.656 14.677 ;
     RECT  14.976 14.053 16.248 14.677 ;
     RECT  44.448 13.573 45.912 14.677 ;
     RECT  32.736 13.139 32.76 14.725 ;
     RECT  34.08 13.715 38.328 14.725 ;
     RECT  4.608 14.149 4.632 14.773 ;
     RECT  28.416 13.045 30.504 14.819 ;
     RECT  39.696 14.675 41.976 14.819 ;
     RECT  23.568 14.485 25.08 14.869 ;
     RECT  4.608 14.773 4.824 14.915 ;
     RECT  11.664 12.563 11.688 14.915 ;
     RECT  32.736 14.725 38.328 14.963 ;
     RECT  12.864 14.677 16.248 15.155 ;
     RECT  29.088 14.819 30.504 15.205 ;
     RECT  55.872 13.621 56.856 15.251 ;
     RECT  61.632 13.717 62.112 15.253 ;
     RECT  23.568 14.869 25.128 15.299 ;
     RECT  2.4 13.715 3.384 15.445 ;
     RECT  16.128 15.155 16.248 15.445 ;
     RECT  17.376 14.339 19.656 15.731 ;
     RECT  49.488 15.013 49.512 15.731 ;
     RECT  39.696 14.819 41.784 15.829 ;
     RECT  20.976 14.291 22.152 15.877 ;
     RECT  24 15.299 25.128 15.877 ;
     RECT  53.856 11.459 54.264 15.877 ;
     RECT  17.376 15.731 19.368 16.019 ;
     RECT  24 15.877 25.56 16.019 ;
     RECT  55.872 15.251 56.808 16.019 ;
     RECT  9.12 14.629 10.104 16.067 ;
     RECT  4.608 14.915 4.632 16.069 ;
     RECT  5.904 14.773 5.928 16.069 ;
     RECT  29.088 15.205 30.984 16.117 ;
     RECT  32.736 14.963 37.896 16.117 ;
     RECT  42.768 15.973 42.792 16.163 ;
     RECT  58.896 14.773 58.92 16.259 ;
     RECT  12.864 15.155 15 16.261 ;
     RECT  16.128 15.445 16.344 16.261 ;
     RECT  43.968 14.677 45.912 16.357 ;
     RECT  7.8 14.291 8.112 16.501 ;
     RECT  9.12 16.067 9.864 16.501 ;
     RECT  25.536 16.019 25.56 16.595 ;
     RECT  61.632 15.253 62.904 16.595 ;
     RECT  4.608 16.069 5.928 16.645 ;
     RECT  60.432 15.493 60.456 16.691 ;
     RECT  2.4 15.445 3.432 16.835 ;
     RECT  12.864 16.261 16.344 16.835 ;
     RECT  17.616 16.019 19.368 16.883 ;
     RECT  53.808 15.877 54.264 16.885 ;
     RECT  26.928 16.501 26.952 16.933 ;
     RECT  11.616 15.061 11.64 16.979 ;
     RECT  24 16.019 24.408 17.077 ;
     RECT  56.304 16.019 56.808 17.077 ;
     RECT  20.544 15.877 22.152 17.123 ;
     RECT  48.96 16.885 49.08 17.123 ;
     RECT  52.992 16.885 54.264 17.123 ;
     RECT  24 17.077 25.08 17.219 ;
     RECT  56.304 17.077 57 17.219 ;
     RECT  43.968 16.357 46.152 17.363 ;
     RECT  39.312 15.829 41.784 17.413 ;
     RECT  26.88 16.933 26.952 17.509 ;
     RECT  24 17.219 24.504 17.605 ;
     RECT  2.4 16.835 2.952 17.699 ;
     RECT  4.608 16.645 6.648 17.699 ;
     RECT  29.088 16.117 37.896 17.747 ;
     RECT  13.2 16.835 16.344 17.843 ;
     RECT  51 14.003 51.312 18.037 ;
     RECT  56.304 17.219 56.808 18.181 ;
     RECT  61.8 16.595 62.904 18.181 ;
     RECT  4.608 17.699 6.6 18.227 ;
     RECT  13.2 17.843 14.952 18.227 ;
     RECT  39.264 17.413 41.784 18.229 ;
     RECT  6.096 18.227 6.6 18.275 ;
     RECT  26.88 17.509 27.48 18.275 ;
     RECT  53.856 17.123 54.264 18.275 ;
     RECT  20.976 17.123 22.152 18.373 ;
     RECT  32.736 17.747 37.896 18.517 ;
     RECT  4.608 18.227 4.968 18.565 ;
     RECT  17.616 16.883 18.912 18.565 ;
     RECT  25.728 18.469 25.752 18.565 ;
     RECT  26.88 18.275 26.904 18.565 ;
     RECT  25.728 18.565 26.904 18.707 ;
     RECT  7.8 16.501 9.864 18.709 ;
     RECT  29.088 17.747 30.984 18.709 ;
     RECT  6.096 18.275 6.12 18.803 ;
     RECT  17.616 18.565 19.512 18.803 ;
     RECT  16.32 17.843 16.344 18.851 ;
     RECT  26.112 18.707 26.904 18.899 ;
     RECT  39.264 18.229 42.024 18.899 ;
     RECT  20.736 18.373 22.152 18.949 ;
     RECT  23.664 17.605 24.504 18.949 ;
     RECT  3.888 18.565 4.968 19.045 ;
     RECT  28.464 18.709 30.984 19.045 ;
     RECT  32.736 18.517 38.184 19.045 ;
     RECT  13.2 18.227 14.232 19.333 ;
     RECT  7.152 18.709 9.864 19.379 ;
     RECT  20.736 18.949 24.504 19.381 ;
     RECT  28.464 19.045 38.184 19.427 ;
     RECT  51 18.037 51.528 19.427 ;
     RECT  61.344 18.181 62.904 19.523 ;
     RECT  20.496 19.381 24.504 19.571 ;
     RECT  3.84 19.045 4.968 19.669 ;
     RECT  34.8 19.427 38.184 19.715 ;
     RECT  26.112 18.899 26.136 19.811 ;
     RECT  41.712 18.899 42.024 19.813 ;
     RECT  51 19.427 51.312 19.813 ;
     RECT  41.712 19.813 42.648 19.957 ;
     RECT  43.968 17.363 45.912 19.957 ;
     RECT  56.304 18.181 57 19.957 ;
     RECT  55.872 19.957 57 20.005 ;
     RECT  18.48 18.803 19.512 20.341 ;
     RECT  54.096 18.275 54.264 20.435 ;
     RECT  39.264 18.899 40.512 20.437 ;
     RECT  41.712 19.957 45.912 20.437 ;
     RECT  7.8 19.379 9.864 20.485 ;
     RECT  18.192 20.341 19.512 20.485 ;
     RECT  20.496 19.571 22.776 20.485 ;
     RECT  49.104 17.989 49.128 20.485 ;
     RECT  12.528 19.333 14.232 20.867 ;
     RECT  28.464 19.427 33.816 20.869 ;
     RECT  34.8 19.715 37.512 20.869 ;
     RECT  39.264 20.437 45.912 20.963 ;
     RECT  26.208 20.485 26.232 21.013 ;
     RECT  55.872 20.005 57.624 21.013 ;
     RECT  18.192 20.485 22.776 21.061 ;
     RECT  59.232 18.133 59.256 21.107 ;
     RECT  26.16 21.013 26.232 21.155 ;
     RECT  39.456 20.963 45.912 21.155 ;
     RECT  49.104 20.485 49.8 21.155 ;
     RECT  3.84 19.669 5.16 21.205 ;
     RECT  28.464 20.869 37.512 21.205 ;
     RECT  17.088 21.109 17.112 21.251 ;
     RECT  15.984 21.157 16.008 21.349 ;
     RECT  2.4 17.699 2.712 21.445 ;
     RECT  3.84 21.205 5.352 21.445 ;
     RECT  28.176 21.205 37.512 21.587 ;
     RECT  23.904 19.571 24.504 21.637 ;
     RECT  26.16 21.155 26.184 21.637 ;
     RECT  55.824 21.013 57.624 21.637 ;
     RECT  26.064 21.637 26.184 21.683 ;
     RECT  60.384 21.013 60.408 21.683 ;
     RECT  18.192 21.061 22.824 21.731 ;
     RECT  61.8 19.523 62.904 21.925 ;
     RECT  61.8 21.925 63.144 21.971 ;
     RECT  20.736 21.731 22.824 22.019 ;
     RECT  28.176 21.587 37.416 22.021 ;
     RECT  52.416 21.589 52.44 22.069 ;
     RECT  7.008 20.485 9.864 22.165 ;
     RECT  43.968 21.155 45.912 22.165 ;
     RECT  63.12 21.971 63.144 22.165 ;
     RECT  2.4 21.445 5.352 22.259 ;
     RECT  50.88 19.813 51.312 22.261 ;
     RECT  18.192 21.731 19.512 22.307 ;
     RECT  49.104 21.155 49.128 22.307 ;
     RECT  39.456 21.155 42.648 22.357 ;
     RECT  12 21.397 12.024 22.499 ;
     RECT  23.904 21.637 24.696 22.499 ;
     RECT  39.408 22.357 42.648 22.643 ;
     RECT  26.064 21.683 26.088 22.645 ;
     RECT  18.192 22.307 19.368 22.739 ;
     RECT  6.864 22.165 9.864 22.741 ;
     RECT  27.648 22.021 37.416 22.741 ;
     RECT  27.648 22.741 37.464 22.787 ;
     RECT  55.824 21.637 58.152 22.835 ;
     RECT  13.2 20.867 14.232 23.173 ;
     RECT  39.408 22.643 40.512 23.221 ;
     RECT  63.12 22.165 63.192 23.267 ;
     RECT  6.864 22.741 10.536 23.315 ;
     RECT  52.416 22.069 52.968 23.459 ;
     RECT  39.168 23.221 40.512 23.509 ;
     RECT  18.192 22.739 19.032 23.555 ;
     RECT  43.968 22.165 46.776 23.603 ;
     RECT  26.064 22.645 26.472 23.605 ;
     RECT  41.568 22.643 42.648 23.605 ;
     RECT  38.736 23.509 40.512 23.699 ;
     RECT  39.168 23.699 40.512 23.797 ;
     RECT  41.52 23.605 42.648 23.797 ;
     RECT  2.4 22.259 5.208 23.845 ;
     RECT  20.736 22.019 22.776 23.891 ;
     RECT  24 22.499 24.696 23.893 ;
     RECT  21.6 23.891 22.776 23.939 ;
     RECT  15.984 21.349 16.584 23.987 ;
     RECT  39.168 23.797 42.648 24.083 ;
     RECT  26.016 23.605 26.472 24.085 ;
     RECT  27.648 22.787 33.816 24.085 ;
     RECT  48.672 22.789 48.696 24.181 ;
     RECT  61.8 21.971 62.112 24.181 ;
     RECT  50.112 22.261 51.312 24.227 ;
     RECT  23.904 23.893 24.696 24.325 ;
     RECT  26.016 24.085 33.816 24.325 ;
     RECT  7.44 23.315 10.536 24.371 ;
     RECT  13.2 23.173 14.568 24.373 ;
     RECT  13.104 24.373 14.568 24.469 ;
     RECT  15.984 23.987 16.008 24.469 ;
     RECT  54.24 20.435 54.264 24.469 ;
     RECT  43.968 23.603 46.152 24.611 ;
     RECT  56.4 22.835 58.152 24.659 ;
     RECT  63.12 23.267 63.144 24.707 ;
     RECT  39.168 24.083 42.024 24.709 ;
     RECT  43.968 24.611 46.008 24.805 ;
     RECT  23.904 24.325 33.816 24.899 ;
     RECT  52.416 23.459 52.536 24.947 ;
     RECT  43.92 24.805 46.008 25.043 ;
     RECT  60.24 23.701 60.264 25.043 ;
     RECT  61.536 24.181 62.112 25.043 ;
     RECT  13.104 24.469 16.008 25.045 ;
     RECT  21.792 23.939 22.776 25.139 ;
     RECT  21.984 25.139 22.776 25.187 ;
     RECT  20.496 24.469 20.52 25.285 ;
     RECT  48.672 24.181 48.984 25.285 ;
     RECT  38.736 24.709 42.024 25.475 ;
     RECT  51 24.227 51.312 25.525 ;
     RECT  12.528 25.045 16.008 25.571 ;
     RECT  2.4 23.845 5.928 25.619 ;
     RECT  53.52 24.469 54.264 25.667 ;
     RECT  2.4 25.619 5.688 25.715 ;
     RECT  21.984 25.187 22.728 26.003 ;
     RECT  20.496 25.285 20.616 26.099 ;
     RECT  12.528 25.571 14.616 26.149 ;
     RECT  51 25.525 51.432 26.197 ;
     RECT  52.416 24.947 52.44 26.197 ;
     RECT  56.4 24.659 57.624 26.197 ;
     RECT  24 24.899 33.816 26.243 ;
     RECT  48.672 25.285 49.224 26.243 ;
     RECT  51 26.197 52.44 26.243 ;
     RECT  24 26.243 26.328 26.245 ;
     RECT  23.904 26.245 26.328 26.435 ;
     RECT  34.8 22.787 37.464 26.437 ;
     RECT  38.736 25.475 40.512 26.437 ;
     RECT  11.472 25.621 11.496 26.483 ;
     RECT  24 26.435 26.328 26.483 ;
     RECT  56.4 26.197 58.008 26.533 ;
     RECT  61.8 25.043 62.112 26.533 ;
     RECT  27.408 26.243 33.816 26.579 ;
     RECT  56.4 26.533 58.584 26.675 ;
     RECT  7.44 24.371 9.864 26.773 ;
     RECT  48.96 26.243 49.224 26.773 ;
     RECT  41.568 25.475 42.024 26.819 ;
     RECT  61.68 26.533 62.112 26.819 ;
     RECT  18.6 23.555 19.032 26.869 ;
     RECT  2.4 25.715 5.208 27.013 ;
     RECT  6.528 26.773 9.864 27.013 ;
     RECT  43.968 25.043 46.008 27.203 ;
     RECT  12.48 26.149 14.616 27.301 ;
     RECT  43.968 27.203 43.992 27.301 ;
     RECT  48.96 26.773 49.416 27.347 ;
     RECT  27.552 26.579 33.816 27.395 ;
     RECT  31.104 27.395 33.816 27.443 ;
     RECT  34.8 26.437 40.512 27.443 ;
     RECT  20.304 26.341 20.328 27.445 ;
     RECT  51 26.243 52.344 27.445 ;
     RECT  50.688 27.445 52.344 27.491 ;
     RECT  32.832 27.443 33.816 27.539 ;
     RECT  21.984 26.003 22.2 27.541 ;
     RECT  11.568 27.301 14.616 27.683 ;
     RECT  2.4 27.013 9.864 27.827 ;
     RECT  34.8 27.443 38.232 27.875 ;
     RECT  21.984 27.541 22.824 27.877 ;
     RECT  24 26.483 26.04 27.877 ;
     RECT  50.688 27.491 51.312 27.877 ;
     RECT  56.4 26.675 58.008 27.923 ;
     RECT  27.552 27.395 30.072 28.115 ;
     RECT  3.744 27.827 9.864 28.163 ;
     RECT  20.304 27.445 20.568 28.163 ;
     RECT  21.984 27.877 26.04 28.309 ;
     RECT  45.6 27.203 46.008 28.357 ;
     RECT  3.744 28.163 5.688 28.451 ;
     RECT  18.6 26.869 19.08 28.451 ;
     RECT  21.984 28.309 26.184 28.451 ;
     RECT  11.568 27.683 14.568 28.547 ;
     RECT  21.984 28.451 26.04 28.643 ;
     RECT  61.8 26.819 62.112 28.645 ;
     RECT  57.984 27.923 58.008 28.691 ;
     RECT  27.552 28.115 29.976 28.739 ;
     RECT  15.984 25.571 16.008 28.741 ;
     RECT  34.8 27.875 37.464 28.933 ;
     RECT  50.544 27.877 51.312 28.981 ;
     RECT  52.32 27.491 52.344 28.981 ;
     RECT  15.696 28.741 16.008 29.075 ;
     RECT  34.8 28.933 37.512 29.075 ;
     RECT  43.92 27.301 43.992 29.075 ;
     RECT  11.568 28.547 11.592 29.123 ;
     RECT  58.128 28.885 58.152 29.171 ;
     RECT  23.04 28.643 26.04 29.219 ;
     RECT  17.52 24.613 17.544 29.317 ;
     RECT  18.6 28.451 18.912 29.317 ;
     RECT  3.744 28.451 4.632 29.509 ;
     RECT  2.4 27.827 2.712 29.605 ;
     RECT  3.696 29.509 4.632 29.605 ;
     RECT  7.488 28.163 9.864 29.605 ;
     RECT  39.552 27.443 40.512 29.605 ;
     RECT  41.568 26.819 41.736 29.605 ;
     RECT  48.96 27.347 49.224 29.653 ;
     RECT  31.104 27.443 31.128 29.699 ;
     RECT  54.24 25.667 54.264 29.699 ;
     RECT  50.544 28.981 52.344 29.747 ;
     RECT  2.4 29.605 4.632 29.845 ;
     RECT  5.664 28.451 5.688 29.845 ;
     RECT  20.304 28.163 20.328 30.085 ;
     RECT  15.696 29.075 15.72 30.133 ;
     RECT  17.52 29.317 18.912 30.133 ;
     RECT  39.552 29.605 41.736 30.179 ;
     RECT  2.4 29.845 5.688 30.611 ;
     RECT  15.696 30.133 19.032 30.709 ;
     RECT  20.304 30.085 20.472 30.709 ;
     RECT  13.2 28.547 14.568 30.803 ;
     RECT  24 29.219 26.04 30.853 ;
     RECT  15.696 30.709 20.472 30.949 ;
     RECT  50.592 29.747 52.344 30.995 ;
     RECT  31.008 30.085 31.032 31.141 ;
     RECT  34.8 29.075 37.464 31.141 ;
     RECT  50.592 30.995 51.312 31.235 ;
     RECT  34.8 31.141 38.328 31.237 ;
     RECT  39.696 30.179 41.736 31.237 ;
     RECT  56.4 27.923 56.712 31.237 ;
     RECT  61.68 28.645 62.112 31.237 ;
     RECT  6.864 29.605 9.864 31.285 ;
     RECT  10.992 30.085 11.016 31.285 ;
     RECT  24 30.853 26.184 31.285 ;
     RECT  45.6 28.357 46.104 31.285 ;
     RECT  34.8 31.237 41.736 31.427 ;
     RECT  6.864 31.285 11.016 31.475 ;
     RECT  15.696 30.949 20.808 31.525 ;
     RECT  28.128 28.739 29.976 31.667 ;
     RECT  7.488 31.475 11.016 31.955 ;
     RECT  24 31.285 26.232 31.955 ;
     RECT  47.328 31.765 47.352 31.955 ;
     RECT  52.32 30.995 52.344 31.955 ;
     RECT  60 27.637 60.024 31.955 ;
     RECT  45.504 31.285 46.104 32.051 ;
     RECT  2.4 30.611 3.72 32.147 ;
     RECT  15.504 31.525 20.808 32.195 ;
     RECT  28.128 31.667 28.2 32.197 ;
     RECT  56.4 31.237 57.096 32.339 ;
     RECT  34.8 31.427 40.512 32.437 ;
     RECT  41.712 31.427 41.736 32.437 ;
     RECT  4.704 30.611 5.688 32.531 ;
     RECT  21.984 28.643 22.008 32.627 ;
     RECT  15.504 32.195 17.208 32.771 ;
     RECT  13.2 30.803 14.424 32.773 ;
     RECT  18.288 32.195 20.808 33.011 ;
     RECT  58.656 31.861 58.68 33.011 ;
     RECT  27.984 32.197 28.2 33.013 ;
     RECT  29.4 31.667 29.976 33.013 ;
     RECT  31.008 31.141 31.848 33.013 ;
     RECT  32.88 27.539 33.816 33.013 ;
     RECT  12.864 32.773 14.424 33.107 ;
     RECT  34.8 32.437 41.736 33.107 ;
     RECT  45.6 32.051 46.104 33.107 ;
     RECT  50.736 31.235 51.312 33.107 ;
     RECT  54.672 31.429 54.696 33.107 ;
     RECT  61.152 31.237 62.112 33.107 ;
     RECT  7.488 31.955 8.232 33.109 ;
     RECT  9.216 31.955 11.016 33.109 ;
     RECT  17.088 32.771 17.208 33.155 ;
     RECT  17.184 33.155 17.208 33.347 ;
     RECT  12.864 33.107 13.992 33.395 ;
     RECT  27.984 33.013 29.976 33.541 ;
     RECT  31.008 33.013 33.816 33.541 ;
     RECT  27.984 33.541 33.816 33.635 ;
     RECT  34.8 33.107 40.512 33.779 ;
     RECT  2.4 32.147 3.432 33.875 ;
     RECT  29.4 33.635 33.816 33.923 ;
     RECT  7.488 33.109 11.016 33.971 ;
     RECT  27.984 33.635 28.2 34.021 ;
     RECT  56.4 32.339 56.712 34.021 ;
     RECT  7.488 33.971 10.824 34.117 ;
     RECT  45.6 33.107 45.912 34.165 ;
     RECT  43.968 29.075 43.992 34.261 ;
     RECT  34.8 33.779 37.656 34.355 ;
     RECT  18.288 33.011 20.472 34.645 ;
     RECT  24 31.955 26.184 34.741 ;
     RECT  32.688 33.923 33.816 34.741 ;
     RECT  34.8 34.355 37.464 34.741 ;
     RECT  56.4 34.021 57.048 34.741 ;
     RECT  7.152 34.117 10.824 34.835 ;
     RECT  27.936 34.021 28.2 34.835 ;
     RECT  32.688 34.741 37.464 34.835 ;
     RECT  29.4 33.923 31.56 34.883 ;
     RECT  7.152 34.835 10.776 34.885 ;
     RECT  2.4 33.875 3.336 34.933 ;
     RECT  55.728 34.741 57.048 35.029 ;
     RECT  41.712 33.107 41.736 35.077 ;
     RECT  43.968 34.261 44.328 35.173 ;
     RECT  45.6 34.165 46.536 35.173 ;
     RECT  29.4 34.883 31.032 35.315 ;
     RECT  43.968 35.173 46.536 35.315 ;
     RECT  18.24 34.645 20.568 35.363 ;
     RECT  55.728 35.029 57.576 35.363 ;
     RECT  6.768 34.885 10.776 35.507 ;
     RECT  12.864 33.395 13.512 35.507 ;
     RECT  43.968 35.315 44.472 35.555 ;
     RECT  27.984 34.835 28.2 35.603 ;
     RECT  7.152 35.507 10.776 35.747 ;
     RECT  47.712 35.077 47.736 35.749 ;
     RECT  52.944 34.117 52.968 35.843 ;
     RECT  53.952 34.741 53.976 35.843 ;
     RECT  13.2 35.507 13.512 35.845 ;
     RECT  18.24 35.363 19.944 35.845 ;
     RECT  32.688 34.835 37.416 35.845 ;
     RECT  39.6 33.779 40.512 35.845 ;
     RECT  41.712 35.077 42.168 35.891 ;
     RECT  17.28 35.845 19.944 35.939 ;
     RECT  21.648 34.549 21.672 35.939 ;
     RECT  61.8 33.107 62.112 35.941 ;
     RECT  2.4 34.933 3.72 36.083 ;
     RECT  61.8 35.941 62.664 36.133 ;
     RECT  15.504 32.771 15.912 36.229 ;
     RECT  4.704 32.531 4.728 36.421 ;
     RECT  4.704 36.421 4.92 36.469 ;
     RECT  32.448 35.845 37.416 36.515 ;
     RECT  59.28 34.165 59.304 36.515 ;
     RECT  56.4 35.363 57.576 36.517 ;
     RECT  47.616 35.749 47.736 36.565 ;
     RECT  48.72 29.653 49.224 36.565 ;
     RECT  50.832 33.107 51.312 36.565 ;
     RECT  9.6 35.747 10.776 36.899 ;
     RECT  13.2 35.845 13.752 36.901 ;
     RECT  22.752 33.301 22.776 36.901 ;
     RECT  15.504 36.229 16.296 36.949 ;
     RECT  17.28 35.939 17.304 36.949 ;
     RECT  9.6 36.899 10.728 37.091 ;
     RECT  13.104 36.901 13.752 37.091 ;
     RECT  15.504 36.949 17.304 37.091 ;
     RECT  56.304 36.517 57.576 37.091 ;
     RECT  61.68 36.133 62.664 37.091 ;
     RECT  22.08 36.901 22.776 37.093 ;
     RECT  15.504 37.091 17.208 37.139 ;
     RECT  17.184 37.139 17.208 37.187 ;
     RECT  15.504 37.139 15.912 37.333 ;
     RECT  18.288 35.939 19.944 37.381 ;
     RECT  21.024 37.093 22.776 37.381 ;
     RECT  18.288 37.381 22.776 37.427 ;
     RECT  22.08 37.427 22.776 37.429 ;
     RECT  50.736 36.565 51.312 37.475 ;
     RECT  32.448 36.515 33.816 37.525 ;
     RECT  29.4 35.315 30.072 37.573 ;
     RECT  14.736 37.333 15.912 37.619 ;
     RECT  4.704 36.469 5.736 37.667 ;
     RECT  9.6 37.091 10.44 37.715 ;
     RECT  38.784 35.845 40.512 37.715 ;
     RECT  43.968 35.555 43.992 37.715 ;
     RECT  45.6 35.315 46.536 37.861 ;
     RECT  24 34.741 26.76 38.147 ;
     RECT  18.288 37.427 20.904 38.149 ;
     RECT  9.6 37.715 10.344 38.243 ;
     RECT  22.08 37.429 22.824 38.533 ;
     RECT  41.712 35.891 41.928 38.533 ;
     RECT  39.552 37.715 40.512 38.675 ;
     RECT  50.832 37.475 51.312 38.677 ;
     RECT  50.208 38.677 51.312 38.725 ;
     RECT  45.36 37.861 46.536 38.819 ;
     RECT  18 38.149 20.904 39.059 ;
     RECT  10.848 38.725 10.872 39.109 ;
     RECT  18.288 39.059 20.904 39.109 ;
     RECT  22.08 38.533 22.968 39.109 ;
     RECT  24 38.147 26.376 39.203 ;
     RECT  28.128 35.603 28.2 39.205 ;
     RECT  7.152 35.747 8.28 39.253 ;
     RECT  2.4 36.083 3.48 39.395 ;
     RECT  50.208 38.725 51.432 39.491 ;
     RECT  13.104 37.091 13.512 39.587 ;
     RECT  56.4 37.091 56.808 39.589 ;
     RECT  50.832 39.491 51.432 39.827 ;
     RECT  18.288 39.109 22.968 39.829 ;
     RECT  24 39.203 26.184 39.829 ;
     RECT  45.36 38.819 46.248 39.875 ;
     RECT  13.2 39.587 13.512 39.877 ;
     RECT  14.736 37.619 15.864 39.877 ;
     RECT  10.848 39.109 10.92 39.923 ;
     RECT  29.4 37.573 30.12 40.021 ;
     RECT  54.576 39.301 54.6 40.163 ;
     RECT  41.712 38.533 42.168 40.165 ;
     RECT  47.616 36.565 49.224 40.261 ;
     RECT  31.968 37.525 33.816 40.357 ;
     RECT  34.8 36.515 37.416 40.357 ;
     RECT  56.4 39.589 56.856 40.451 ;
     RECT  4.704 37.667 4.92 40.499 ;
     RECT  47.616 40.261 49.56 40.499 ;
     RECT  41.664 40.165 42.168 40.501 ;
     RECT  41.616 40.501 42.168 40.547 ;
     RECT  6.816 39.253 8.28 40.595 ;
     RECT  47.616 40.499 47.88 40.597 ;
     RECT  45.36 39.875 46.152 40.643 ;
     RECT  13.2 39.877 15.864 40.693 ;
     RECT  27.408 39.205 28.2 40.693 ;
     RECT  29.184 40.021 30.12 40.693 ;
     RECT  27.408 40.693 30.12 40.741 ;
     RECT  45.36 40.643 46.008 40.789 ;
     RECT  49.2 40.499 49.56 40.835 ;
     RECT  63.12 39.301 63.144 40.835 ;
     RECT  27.408 40.741 30.888 40.837 ;
     RECT  31.968 40.357 37.416 40.837 ;
     RECT  2.4 39.395 2.808 40.981 ;
     RECT  50.832 39.827 51.312 40.981 ;
     RECT  2.4 40.981 3.72 41.027 ;
     RECT  18.288 39.829 26.184 41.075 ;
     RECT  41.616 40.547 41.688 41.075 ;
     RECT  47.376 40.597 47.88 41.219 ;
     RECT  60.336 40.405 60.36 41.267 ;
     RECT  18.288 41.075 25.704 41.363 ;
     RECT  27.408 40.837 37.416 41.509 ;
     RECT  9.84 38.243 9.864 41.557 ;
     RECT  10.848 39.923 10.872 41.557 ;
     RECT  12.528 40.693 15.864 41.605 ;
     RECT  3.696 41.027 3.72 41.651 ;
     RECT  18.6 41.363 25.704 41.651 ;
     RECT  27.312 41.509 37.416 41.651 ;
     RECT  6.816 40.595 8.232 41.749 ;
     RECT  47.616 41.219 47.88 41.795 ;
     RECT  56.4 40.451 56.808 41.893 ;
     RECT  58.896 41.557 58.92 41.893 ;
     RECT  61.68 37.091 62.112 41.939 ;
     RECT  31.968 41.651 37.416 42.035 ;
     RECT  6.432 41.749 8.232 42.037 ;
     RECT  34.8 42.035 37.416 42.037 ;
     RECT  40.2 38.675 40.512 42.181 ;
     RECT  41.664 41.075 41.688 42.181 ;
     RECT  12.528 41.605 16.008 42.227 ;
     RECT  58.464 41.893 58.92 42.227 ;
     RECT  40.2 42.181 41.688 42.515 ;
     RECT  6.432 42.037 8.52 42.563 ;
     RECT  2.4 41.027 2.712 42.709 ;
     RECT  56.4 41.893 57.288 42.709 ;
     RECT  58.464 42.227 58.488 42.709 ;
     RECT  9.84 41.557 10.872 42.755 ;
     RECT  40.2 42.515 41.016 42.755 ;
     RECT  55.296 41.125 55.32 42.755 ;
     RECT  18.6 41.651 20.904 42.803 ;
     RECT  64.368 42.037 64.392 42.803 ;
     RECT  56.4 42.709 58.488 42.851 ;
     RECT  27.312 41.651 30.888 42.997 ;
     RECT  22.176 41.651 25.704 43.093 ;
     RECT  26.88 42.997 30.888 43.093 ;
     RECT  45.264 40.789 46.008 43.093 ;
     RECT  38.928 39.733 38.952 43.141 ;
     RECT  38.784 43.141 38.952 43.187 ;
     RECT  34.8 42.037 37.512 43.235 ;
     RECT  22.176 43.093 30.888 43.237 ;
     RECT  31.968 42.035 33.816 43.237 ;
     RECT  22.176 43.237 33.816 43.283 ;
     RECT  18.6 42.803 20.088 43.285 ;
     RECT  2.4 42.709 2.808 43.333 ;
     RECT  60.528 42.181 60.552 43.523 ;
     RECT  22.176 43.283 30.168 43.571 ;
     RECT  22.176 43.571 26.904 43.715 ;
     RECT  13.2 42.227 16.008 43.811 ;
     RECT  13.2 43.811 15.864 43.955 ;
     RECT  28.128 43.571 30.168 43.955 ;
     RECT  45.264 43.093 46.056 43.957 ;
     RECT  42.192 43.141 42.216 44.197 ;
     RECT  47.616 41.795 47.784 44.197 ;
     RECT  11.712 43.813 11.736 44.389 ;
     RECT  9.84 42.755 10.344 44.437 ;
     RECT  18.48 43.285 20.088 44.483 ;
     RECT  22.176 43.715 22.44 44.483 ;
     RECT  45.216 43.957 46.056 44.483 ;
     RECT  45.216 44.483 46.008 44.531 ;
     RECT  22.176 44.483 22.2 44.677 ;
     RECT  21.696 44.677 22.2 44.723 ;
     RECT  58.464 42.851 58.488 44.773 ;
     RECT  2.4 43.333 3.384 44.915 ;
     RECT  23.472 43.715 26.904 44.965 ;
     RECT  42.192 44.197 42.36 44.965 ;
     RECT  28.128 43.955 28.296 45.013 ;
     RECT  19.92 44.483 20.088 45.059 ;
     RECT  42.192 44.965 42.792 45.299 ;
     RECT  13.2 43.955 15.432 45.301 ;
     RECT  40.2 42.755 40.512 45.301 ;
     RECT  64.368 44.917 64.392 45.301 ;
     RECT  64.08 45.301 64.392 45.347 ;
     RECT  40.08 45.301 40.512 45.349 ;
     RECT  42.192 45.299 42.36 45.349 ;
     RECT  28.128 45.013 28.392 45.445 ;
     RECT  29.4 43.955 30.168 45.445 ;
     RECT  20.064 45.059 20.088 45.493 ;
     RECT  18.48 44.483 18.912 45.541 ;
     RECT  53.376 43.861 53.4 45.541 ;
     RECT  20.064 45.493 20.376 45.589 ;
     RECT  23.472 44.965 26.952 45.589 ;
     RECT  38.784 43.187 38.808 45.589 ;
     RECT  40.08 45.349 42.36 45.589 ;
     RECT  6.432 42.563 8.112 45.733 ;
     RECT  9.696 44.437 10.344 45.733 ;
     RECT  61.8 41.939 62.112 45.733 ;
     RECT  13.2 45.301 16.008 45.973 ;
     RECT  13.104 45.973 16.008 46.211 ;
     RECT  23.472 45.589 27.096 46.211 ;
     RECT  38.784 45.589 42.36 46.211 ;
     RECT  2.4 44.915 2.808 46.259 ;
     RECT  47.616 44.197 47.88 46.501 ;
     RECT  49.2 40.835 49.224 46.501 ;
     RECT  17.616 45.541 18.912 46.645 ;
     RECT  27.072 46.211 27.096 46.645 ;
     RECT  28.128 45.445 30.168 46.645 ;
     RECT  17.04 46.645 18.912 46.741 ;
     RECT  4.704 40.499 4.824 46.787 ;
     RECT  6.432 45.733 10.344 46.787 ;
     RECT  16.224 46.741 18.912 46.787 ;
     RECT  20.064 45.589 20.712 46.787 ;
     RECT  40.08 46.211 42.36 46.787 ;
     RECT  21.696 44.723 21.72 46.789 ;
     RECT  38.784 46.211 38.808 47.027 ;
     RECT  64.08 45.347 64.104 47.029 ;
     RECT  61.8 45.733 62.28 47.075 ;
     RECT  64.08 47.029 64.44 47.075 ;
     RECT  9.84 46.787 10.344 47.269 ;
     RECT  11.424 44.389 11.736 47.269 ;
     RECT  13.104 46.211 14.472 47.315 ;
     RECT  16.224 46.787 16.248 47.315 ;
     RECT  27.072 46.645 30.168 47.317 ;
     RECT  31.152 43.283 32.088 47.317 ;
     RECT  13.2 47.315 14.472 47.363 ;
     RECT  27.072 47.317 32.088 47.603 ;
     RECT  45.264 44.531 46.008 47.749 ;
     RECT  58.464 44.773 58.872 47.939 ;
     RECT  58.656 47.939 58.872 48.131 ;
     RECT  21.696 46.789 21.96 48.275 ;
     RECT  47.616 46.501 49.224 48.275 ;
     RECT  2.4 46.259 2.712 48.421 ;
     RECT  23.472 46.211 25.992 48.421 ;
     RECT  27.072 47.603 27.096 48.421 ;
     RECT  44.448 47.749 46.008 48.421 ;
     RECT  40.08 46.787 40.512 48.467 ;
     RECT  53.376 45.541 54.312 48.469 ;
     RECT  34.8 43.235 37.416 48.515 ;
     RECT  6.432 46.787 8.616 48.659 ;
     RECT  28.128 47.603 32.088 48.659 ;
     RECT  38.736 47.461 38.76 48.659 ;
     RECT  23.472 48.421 27.096 48.707 ;
     RECT  47.616 48.275 47.928 48.709 ;
     RECT  21.696 48.275 21.72 48.803 ;
     RECT  15.024 48.229 15.048 48.947 ;
     RECT  43.728 48.421 46.008 48.947 ;
     RECT  64.416 47.075 64.44 48.995 ;
     RECT  49.2 48.275 49.224 48.997 ;
     RECT  31.68 48.659 32.088 49.043 ;
     RECT  58.848 48.131 58.872 49.043 ;
     RECT  23.712 48.707 27.096 49.091 ;
     RECT  45.264 48.947 46.008 49.091 ;
     RECT  53.376 48.469 54.648 49.091 ;
     RECT  61.8 47.075 62.232 49.235 ;
     RECT  31.728 49.043 32.088 49.427 ;
     RECT  47.328 48.709 47.928 49.429 ;
     RECT  49.2 48.997 49.656 49.429 ;
     RECT  2.4 48.421 2.856 49.523 ;
     RECT  47.328 49.429 49.656 49.619 ;
     RECT  28.128 48.659 30.168 49.667 ;
     RECT  23.712 49.091 25.992 49.811 ;
     RECT  13.2 47.363 13.512 50.005 ;
     RECT  6.432 48.659 8.112 50.051 ;
     RECT  53.376 49.091 53.4 50.101 ;
     RECT  61.8 49.235 62.112 50.101 ;
     RECT  33.12 43.283 33.816 50.149 ;
     RECT  34.8 48.515 37.08 50.149 ;
     RECT  42.336 46.787 42.36 50.149 ;
     RECT  43.728 48.947 43.752 50.149 ;
     RECT  45.264 49.091 45.912 50.149 ;
     RECT  61.68 50.101 62.112 50.149 ;
     RECT  42.336 50.149 43.752 50.195 ;
     RECT  33.12 50.149 37.08 50.243 ;
     RECT  45.264 50.149 46.2 50.293 ;
     RECT  45.168 50.293 46.2 50.389 ;
     RECT  45.072 50.389 46.2 50.437 ;
     RECT  47.616 49.619 49.656 50.579 ;
     RECT  44.832 50.437 46.2 50.675 ;
     RECT  23.712 49.811 24.456 50.677 ;
     RECT  56.4 42.851 57.288 50.677 ;
     RECT  58.32 50.437 58.344 50.677 ;
     RECT  13.2 50.005 13.8 50.771 ;
     RECT  15.456 50.005 15.48 50.771 ;
     RECT  49.2 50.579 49.656 50.771 ;
     RECT  33.12 50.243 37.032 50.819 ;
     RECT  49.632 50.771 49.656 50.819 ;
     RECT  53.376 50.101 54.168 50.819 ;
     RECT  40.2 48.467 40.512 50.821 ;
     RECT  9.84 47.269 11.736 50.917 ;
     RECT  27.072 49.091 27.096 50.963 ;
     RECT  56.4 50.677 58.344 50.965 ;
     RECT  56.4 50.965 59.304 51.011 ;
     RECT  32.064 49.427 32.088 51.107 ;
     RECT  4.704 46.787 4.728 51.253 ;
     RECT  25.968 49.811 25.992 51.253 ;
     RECT  47.616 50.579 47.736 51.253 ;
     RECT  39.984 50.821 40.512 51.301 ;
     RECT  9.84 50.917 11.976 51.347 ;
     RECT  44.832 50.675 45.912 51.347 ;
     RECT  60.816 50.149 62.112 51.347 ;
     RECT  21.648 49.189 21.672 51.923 ;
     RECT  22.8 50.677 24.456 51.923 ;
     RECT  39.312 51.301 40.512 51.923 ;
     RECT  64.416 50.533 64.44 51.923 ;
     RECT  34.8 50.819 37.032 52.021 ;
     RECT  42.528 50.195 43.752 52.021 ;
     RECT  34.8 52.021 37.368 52.163 ;
     RECT  59.28 51.011 59.304 52.165 ;
     RECT  47.328 51.253 47.736 52.211 ;
     RECT  33.12 50.819 33.624 52.213 ;
     RECT  31.392 51.253 31.416 52.309 ;
     RECT  32.976 52.213 33.624 52.309 ;
     RECT  53.376 50.819 53.4 52.357 ;
     RECT  13.2 50.771 13.512 52.405 ;
     RECT  3.984 51.253 5.4 52.499 ;
     RECT  28.128 49.667 30.12 52.499 ;
     RECT  53.376 52.357 53.592 52.499 ;
     RECT  28.128 52.499 29.88 52.595 ;
     RECT  44.976 51.347 45.912 52.595 ;
     RECT  20.064 46.787 20.088 52.885 ;
     RECT  18.6 46.787 18.912 52.981 ;
     RECT  19.92 52.885 20.088 52.981 ;
     RECT  22.8 51.923 24.312 52.981 ;
     RECT  47.616 52.211 47.736 52.981 ;
     RECT  42.48 52.021 43.752 53.027 ;
     RECT  53.568 52.499 53.592 53.075 ;
     RECT  31.392 52.309 33.624 53.219 ;
     RECT  59.232 52.165 59.304 53.219 ;
     RECT  9.84 51.347 11.736 53.461 ;
     RECT  18.6 52.981 20.088 53.557 ;
     RECT  45.504 52.595 45.912 53.557 ;
     RECT  22.56 52.981 24.312 53.603 ;
     RECT  54.672 53.557 54.696 53.797 ;
     RECT  56.4 51.011 57.528 53.797 ;
     RECT  61.68 51.347 62.112 53.797 ;
     RECT  28.128 52.595 29.832 53.843 ;
     RECT  54.288 53.797 54.696 53.843 ;
     RECT  25.68 51.253 25.992 54.035 ;
     RECT  22.56 53.603 22.584 54.037 ;
     RECT  43.728 53.027 43.752 54.037 ;
     RECT  47.616 52.981 48.216 54.083 ;
     RECT  25.968 54.035 25.992 54.133 ;
     RECT  9.12 53.461 11.736 54.179 ;
     RECT  31.392 53.219 32.184 54.373 ;
     RECT  33.168 53.219 33.624 54.373 ;
     RECT  60.912 53.797 62.112 54.419 ;
     RECT  24 53.603 24.312 54.421 ;
     RECT  34.8 52.163 37.032 54.421 ;
     RECT  40.2 51.923 40.512 54.565 ;
     RECT  54.288 53.843 54.312 54.661 ;
     RECT  42.48 53.027 42.552 54.709 ;
     RECT  25.968 54.133 26.184 54.755 ;
     RECT  31.392 54.373 33.624 54.755 ;
     RECT  43.728 54.037 43.944 54.755 ;
     RECT  22.032 54.037 22.584 54.803 ;
     RECT  28.128 53.843 29.712 54.851 ;
     RECT  45.408 53.557 45.912 54.899 ;
     RECT  59.568 53.509 59.592 54.899 ;
     RECT  40.2 54.565 40.776 54.901 ;
     RECT  33.168 54.755 33.624 54.947 ;
     RECT  42.48 54.709 42.744 54.947 ;
     RECT  55.824 53.797 57.528 55.043 ;
     RECT  64.752 54.085 64.776 55.045 ;
     RECT  64.416 55.045 64.776 55.091 ;
     RECT  28.272 54.851 29.712 55.141 ;
     RECT  31.392 54.755 32.184 55.141 ;
     RECT  6.768 50.051 8.112 55.237 ;
     RECT  54.144 54.661 54.312 55.331 ;
     RECT  18.6 53.557 20.568 55.427 ;
     RECT  28.272 55.141 32.184 55.427 ;
     RECT  34.8 54.421 37.128 55.429 ;
     RECT  47.616 54.083 47.64 55.525 ;
     RECT  4.704 52.499 5.4 55.667 ;
     RECT  34.8 55.429 37.416 55.717 ;
     RECT  33.312 54.947 33.624 55.859 ;
     RECT  43.728 54.755 43.896 55.955 ;
     RECT  42.48 54.947 42.552 55.957 ;
     RECT  16.56 55.141 16.584 56.099 ;
     RECT  18.6 55.427 20.088 56.099 ;
     RECT  64.416 55.091 64.44 56.099 ;
     RECT  42.48 55.957 42.744 56.149 ;
     RECT  5.232 55.667 5.4 56.195 ;
     RECT  40.032 54.901 40.776 56.195 ;
     RECT  54.192 55.331 54.312 56.435 ;
     RECT  28.272 55.427 30.6 56.437 ;
     RECT  12.768 52.405 13.512 56.531 ;
     RECT  50.736 40.981 51.312 56.531 ;
     RECT  27.504 56.437 30.6 56.627 ;
     RECT  6.672 55.237 8.112 56.819 ;
     RECT  32.16 55.427 32.184 56.867 ;
     RECT  50.832 56.531 51.312 56.867 ;
     RECT  34.704 55.717 37.416 56.915 ;
     RECT  22.56 54.803 22.584 57.013 ;
     RECT  22.56 57.013 22.824 57.059 ;
     RECT  27.504 56.627 27.528 57.059 ;
     RECT  29.088 56.627 30.6 57.059 ;
     RECT  34.704 56.915 36.072 57.059 ;
     RECT  41.952 56.149 42.744 57.059 ;
     RECT  47.616 55.525 48.504 57.059 ;
     RECT  56.256 55.043 57.528 57.059 ;
     RECT  24 54.421 24.648 57.109 ;
     RECT  25.968 54.755 25.992 57.109 ;
     RECT  15.984 56.965 16.008 57.299 ;
     RECT  9.84 54.179 11.736 57.301 ;
     RECT  40.032 56.195 40.512 57.347 ;
     RECT  18.6 56.099 18.912 57.349 ;
     RECT  19.92 56.099 20.088 57.395 ;
     RECT  24 57.109 25.992 57.395 ;
     RECT  29.28 57.059 30.6 57.443 ;
     RECT  59.616 56.341 59.64 57.445 ;
     RECT  51 56.867 51.312 57.589 ;
     RECT  59.616 57.445 59.784 57.635 ;
     RECT  56.4 57.059 57.528 57.683 ;
     RECT  29.4 57.443 30.6 57.731 ;
     RECT  37.392 56.915 37.416 57.875 ;
     RECT  43.728 55.955 43.848 57.875 ;
     RECT  6.768 56.819 8.112 57.973 ;
     RECT  33.312 55.859 33.48 58.069 ;
     RECT  59.76 57.635 59.784 58.115 ;
     RECT  18.48 57.349 18.912 58.117 ;
     RECT  25.968 57.395 25.992 58.163 ;
     RECT  24 57.395 24.936 58.355 ;
     RECT  13.2 56.531 13.512 58.501 ;
     RECT  56.4 57.683 57.048 58.643 ;
     RECT  6.432 57.973 8.112 58.645 ;
     RECT  5.232 56.195 5.256 58.739 ;
     RECT  47.616 57.059 47.64 58.739 ;
     RECT  3.888 58.357 3.912 58.883 ;
     RECT  45.6 54.899 45.912 58.933 ;
     RECT  6.432 58.645 8.328 59.075 ;
     RECT  18.384 58.117 18.912 59.077 ;
     RECT  51 57.589 51.912 59.077 ;
     RECT  33.312 58.069 33.576 59.171 ;
     RECT  54.288 56.435 54.312 59.173 ;
     RECT  19.92 57.395 19.944 59.219 ;
     RECT  54.288 59.173 54.408 59.219 ;
     RECT  9.456 57.301 11.736 59.315 ;
     RECT  61.8 54.419 62.112 59.461 ;
     RECT  29.4 57.731 30.264 59.555 ;
     RECT  25.968 59.221 25.992 59.557 ;
     RECT  42.528 57.059 42.744 59.605 ;
     RECT  43.728 57.875 43.752 59.605 ;
     RECT  54.384 59.219 54.408 59.605 ;
     RECT  58.608 57.829 58.632 59.605 ;
     RECT  51 59.077 52.2 59.701 ;
     RECT  53.28 56.725 53.304 59.701 ;
     RECT  45.504 58.933 45.912 59.749 ;
     RECT  2.4 49.523 2.712 59.797 ;
     RECT  51 59.701 53.304 59.843 ;
     RECT  17.424 59.077 18.912 59.891 ;
     RECT  40.08 57.347 40.512 59.891 ;
     RECT  56.4 58.643 57 59.891 ;
     RECT  58.608 59.605 59.256 59.891 ;
     RECT  42.528 59.605 43.752 59.987 ;
     RECT  6.672 59.075 8.328 60.035 ;
     RECT  51 59.843 52.2 60.085 ;
     RECT  9.84 59.315 11.736 60.275 ;
     RECT  50.736 60.085 52.2 60.371 ;
     RECT  11.424 60.275 11.736 60.373 ;
     RECT  13.104 58.501 13.512 60.373 ;
     RECT  61.8 59.461 62.328 60.515 ;
     RECT  25.44 59.557 25.992 60.563 ;
     RECT  27.408 58.597 27.432 60.611 ;
     RECT  9.84 60.275 10.392 60.709 ;
     RECT  64.704 59.605 64.728 60.803 ;
     RECT  24 58.355 24.312 60.949 ;
     RECT  25.44 60.563 25.464 60.949 ;
     RECT  2.4 59.797 2.904 60.995 ;
     RECT  4.656 60.181 4.68 60.995 ;
     RECT  45.504 59.749 46.632 60.995 ;
     RECT  48.864 59.461 48.888 60.995 ;
     RECT  43.056 59.987 43.752 61.043 ;
     RECT  53.28 59.843 53.304 61.043 ;
     RECT  54.384 59.605 55.032 61.043 ;
     RECT  11.424 60.373 13.512 61.333 ;
     RECT  11.424 61.333 13.848 61.379 ;
     RECT  24 60.949 25.464 61.429 ;
     RECT  43.728 61.043 43.752 61.477 ;
     RECT  38.688 59.365 38.712 61.619 ;
     RECT  58.608 59.891 58.632 61.619 ;
     RECT  6.672 60.035 8.112 61.621 ;
     RECT  56.4 59.891 56.856 61.667 ;
     RECT  22.8 57.059 22.824 61.765 ;
     RECT  23.808 61.429 25.464 61.765 ;
     RECT  41.952 59.989 41.976 61.859 ;
     RECT  22.8 61.765 25.464 61.955 ;
     RECT  29.4 59.555 29.712 62.101 ;
     RECT  37.536 59.893 37.56 62.101 ;
     RECT  17.712 59.891 18.912 62.149 ;
     RECT  9.696 60.709 10.392 62.195 ;
     RECT  27.12 60.949 27.144 62.195 ;
     RECT  32.496 60.421 32.52 62.195 ;
     RECT  61.8 60.515 62.112 62.437 ;
     RECT  29.4 62.101 30.552 62.533 ;
     RECT  2.4 60.995 2.712 62.581 ;
     RECT  17.664 62.149 18.912 62.581 ;
     RECT  19.92 60.805 19.944 62.677 ;
     RECT  29.28 62.533 30.552 62.677 ;
     RECT  2.4 62.581 2.952 62.723 ;
     RECT  11.424 61.379 12.216 62.723 ;
     RECT  19.92 62.677 20.088 62.723 ;
     RECT  29.28 62.677 30.84 62.723 ;
     RECT  5.04 61.189 5.064 62.771 ;
     RECT  34.8 57.059 36.072 62.771 ;
     RECT  43.728 61.477 44.04 62.771 ;
     RECT  56.4 61.667 56.712 62.773 ;
     RECT  42.672 62.677 42.696 62.819 ;
     RECT  43.728 62.771 43.752 62.821 ;
     RECT  20.064 62.723 20.088 62.965 ;
     RECT  21.12 61.573 21.144 62.965 ;
     RECT  40.2 59.891 40.512 62.965 ;
     RECT  20.064 62.965 21.144 63.011 ;
     RECT  54.384 61.043 54.408 63.011 ;
     RECT  40.2 62.965 40.68 63.107 ;
     RECT  50.88 60.371 51.312 63.107 ;
     RECT  6.528 61.621 8.112 63.205 ;
     RECT  9.696 62.195 9.72 63.205 ;
     RECT  6.528 63.205 9.72 63.299 ;
     RECT  11.424 62.723 11.736 63.299 ;
     RECT  43.392 62.821 43.752 63.299 ;
     RECT  22.8 61.955 24.312 63.347 ;
     RECT  22.8 63.347 22.872 63.491 ;
     RECT  16.896 62.581 18.912 63.731 ;
     RECT  58.656 61.765 58.68 63.733 ;
     RECT  20.064 63.011 20.904 63.779 ;
     RECT  30.816 62.723 30.84 63.779 ;
     RECT  15.024 62.821 15.048 63.827 ;
     RECT  37.056 62.101 37.56 63.827 ;
     RECT  43.392 63.299 43.416 63.827 ;
     RECT  58.656 63.733 59.256 63.827 ;
     RECT  6.672 63.299 9.72 63.875 ;
     RECT  11.472 63.299 11.736 63.923 ;
     RECT  22.8 63.491 22.824 63.923 ;
     RECT  20.064 63.779 20.088 64.115 ;
     RECT  48.912 62.677 48.936 64.165 ;
     RECT  17.52 63.731 18.912 64.211 ;
     RECT  48.48 64.165 48.936 64.211 ;
     RECT  27.888 63.877 27.912 64.355 ;
     RECT  18.6 64.211 18.912 64.357 ;
     RECT  51 63.107 51.312 64.357 ;
     RECT  61.8 62.437 62.808 64.403 ;
     RECT  13.2 61.379 13.848 64.451 ;
     RECT  59.232 63.827 59.256 64.451 ;
     RECT  56.4 62.773 57 64.499 ;
     RECT  34.8 62.771 35.112 64.741 ;
     RECT  7.152 63.875 9.72 64.883 ;
     RECT  25.44 61.955 25.464 64.931 ;
     RECT  33.552 59.171 33.576 64.931 ;
     RECT  13.2 64.451 13.512 64.933 ;
     RECT  24 63.347 24.312 64.933 ;
     RECT  11.712 63.923 11.736 65.027 ;
     RECT  32.496 64.261 32.52 65.123 ;
     RECT  26.496 64.357 26.52 65.171 ;
     RECT  29.28 62.723 29.712 65.171 ;
     RECT  52.848 64.885 52.872 65.411 ;
     RECT  34.656 64.741 35.112 65.459 ;
     RECT  38.688 63.205 38.712 65.459 ;
     RECT  18.6 64.357 19.368 65.555 ;
     RECT  17.52 64.211 17.544 65.603 ;
     RECT  37.536 63.827 37.56 65.603 ;
     RECT  45.6 60.995 46.632 65.603 ;
     RECT  48.48 64.211 48.504 65.603 ;
     RECT  12.72 64.933 13.512 65.651 ;
     RECT  15.12 64.933 15.144 65.651 ;
     RECT  24 64.933 25.08 65.699 ;
     RECT  51 64.357 51.432 65.699 ;
     RECT  2.4 62.723 2.712 65.889 ;
     RECT  13.2 65.651 13.512 65.889 ;
     RECT  18.6 65.555 18.912 65.889 ;
     RECT  24 65.699 24.312 65.889 ;
     RECT  29.4 65.171 29.712 65.889 ;
     RECT  34.8 65.459 35.112 65.889 ;
     RECT  40.2 63.107 40.512 65.889 ;
     RECT  45.6 65.603 45.912 65.889 ;
     RECT  51 65.699 51.312 65.889 ;
     RECT  56.4 64.499 56.712 65.889 ;
     RECT  61.8 64.403 62.112 65.889 ;
     RECT  2.4 65.889 2.52 65.903 ;
     RECT  13.2 65.889 13.32 65.903 ;
     RECT  18.6 65.889 18.72 65.903 ;
     RECT  24 65.889 24.12 65.903 ;
     RECT  29.4 65.889 29.52 65.903 ;
     RECT  34.8 65.889 34.92 65.903 ;
     RECT  40.2 65.889 40.32 65.903 ;
     RECT  45.6 65.889 45.72 65.903 ;
     RECT  51 65.889 51.12 65.903 ;
     RECT  56.4 65.889 56.52 65.903 ;
     RECT  61.8 65.889 61.92 65.903 ;
     RECT  7.152 64.883 9.48 67.861 ;
     RECT  7.152 67.861 9.576 67.984 ;
     RECT  28.104 2.245 29.4 4.067 ;
     RECT  62.112 2.773 63.216 4.501 ;
     RECT  15 2.821 16.272 4.403 ;
     RECT  16.296 2.821 17.712 3.109 ;
     RECT  16.296 3.109 17.664 4.741 ;
     RECT  18.912 3.397 20.208 6.037 ;
     RECT  55.416 3.397 56.4 4.117 ;
     RECT  42.216 3.637 43.632 4.115 ;
     RECT  13.512 3.923 14.736 5.365 ;
     RECT  56.712 3.925 57.792 4.117 ;
     RECT  26.76 3.973 28.08 4.067 ;
     RECT  60.312 3.973 61.8 4.453 ;
     RECT  26.76 4.067 29.4 4.501 ;
     RECT  42.216 4.115 43.368 4.549 ;
     RECT  29.712 4.213 30.912 4.741 ;
     RECT  30.936 4.213 32.064 4.501 ;
     RECT  40.512 4.213 41.808 7.667 ;
     RECT  9.96 4.357 11.424 4.885 ;
     RECT  11.448 4.357 12.528 5.077 ;
     RECT  20.28 4.357 21.648 4.741 ;
     RECT  14.76 4.403 16.272 9.587 ;
     RECT  55.416 4.403 56.4 5.171 ;
     RECT  27.624 4.501 29.4 5.461 ;
     RECT  32.76 4.501 34.08 5.749 ;
     RECT  26.184 4.547 27.456 4.835 ;
     RECT  42.216 4.549 43.344 5.941 ;
     RECT  8.112 4.597 9.12 6.035 ;
     RECT  16.296 4.741 17.616 4.981 ;
     RECT  25.944 4.835 27.456 6.229 ;
     RECT  35.256 4.837 36.672 6.037 ;
     RECT  45.912 5.077 47.376 6.613 ;
     RECT  55.392 5.171 56.4 5.605 ;
     RECT  30.744 5.219 32.256 6.805 ;
     RECT  22.392 5.365 23.568 6.373 ;
     RECT  28.248 5.461 29.4 5.845 ;
     RECT  37.416 5.557 38.448 7.381 ;
     RECT  55.32 5.605 56.4 6.851 ;
     RECT  10.632 5.651 11.952 6.803 ;
     RECT  32.76 5.749 33.744 7.381 ;
     RECT  28.248 6.035 29.4 7.717 ;
     RECT  26.184 6.229 27.456 6.323 ;
     RECT  26.184 6.323 26.664 6.805 ;
     RECT  22.392 6.373 23.376 7.139 ;
     RECT  20.808 6.419 22.176 8.435 ;
     RECT  16.296 6.899 17.616 8.485 ;
     RECT  30.216 6.899 31.392 7.861 ;
     RECT  19.416 7.091 20.4 8.003 ;
     RECT  22.392 7.139 23.664 7.427 ;
     RECT  37.416 7.381 38.4 7.909 ;
     RECT  57.336 7.381 58.32 8.485 ;
     RECT  22.2 7.427 23.664 8.435 ;
     RECT  40.512 7.667 42.432 7.909 ;
     RECT  9.744 7.907 10.224 9.109 ;
     RECT  41.064 7.909 42.432 8.867 ;
     RECT  18.912 8.003 20.4 8.917 ;
     RECT  7.392 8.195 7.68 9.253 ;
     RECT  38.472 8.389 39.552 8.531 ;
     RECT  20.808 8.435 23.76 9.397 ;
     RECT  16.392 8.485 17.616 10.117 ;
     RECT  26.664 8.485 27.744 9.059 ;
     RECT  62.112 8.485 63.312 9.251 ;
     RECT  38.472 8.531 39.888 11.365 ;
     RECT  42.096 8.867 42.432 9.541 ;
     RECT  18.912 8.917 20.352 10.117 ;
     RECT  26.568 9.059 27.744 10.357 ;
     RECT  58.344 9.061 59.76 9.637 ;
     RECT  42.456 9.349 43.536 10.067 ;
     RECT  21.72 9.397 23.76 9.637 ;
     RECT  9.768 9.587 10.248 10.741 ;
     RECT  14.712 9.587 16.272 10.789 ;
     RECT  20.568 9.587 21.696 10.931 ;
     RECT  22.248 9.637 23.76 12.229 ;
     RECT  31.368 9.731 32.352 10.885 ;
     RECT  56.856 9.827 58.128 13.091 ;
     RECT  42.168 10.067 43.536 10.931 ;
     RECT  16.44 10.117 17.616 10.693 ;
     RECT  26.616 10.357 27.744 10.645 ;
     RECT  8.568 10.597 9.744 11.699 ;
     RECT  40.512 10.597 41.952 10.789 ;
     RECT  17.208 10.739 18.48 12.325 ;
     RECT  19.464 10.739 20.448 11.699 ;
     RECT  44.376 10.741 45.6 11.699 ;
     RECT  14.808 10.789 16.272 11.461 ;
     RECT  10.248 10.885 11.664 11.797 ;
     RECT  20.568 10.931 21.792 11.075 ;
     RECT  45.912 10.979 46.992 12.515 ;
     RECT  20.472 11.075 21.792 13.765 ;
     RECT  39 11.411 40.2 12.805 ;
     RECT  51.312 11.459 51.432 12.901 ;
     RECT  15 11.461 16.272 12.949 ;
     RECT  30.408 11.507 31.536 12.755 ;
     RECT  32.76 11.507 33.936 13.619 ;
     RECT  8.112 11.699 9.744 12.901 ;
     RECT  19.032 11.699 20.448 12.083 ;
     RECT  43.896 11.699 45.6 12.469 ;
     RECT  10.248 11.797 11.424 11.843 ;
     RECT  9.816 11.843 11.424 12.563 ;
     RECT  18.912 12.083 20.448 12.805 ;
     RECT  22.776 12.229 23.76 12.373 ;
     RECT  11.688 12.371 12.864 14.915 ;
     RECT  43.896 12.469 44.976 13.091 ;
     RECT  9.816 12.563 10.104 13.045 ;
     RECT  13.656 12.611 14.976 14.677 ;
     RECT  30.408 12.755 31.968 13.045 ;
     RECT  18.912 12.805 20.304 13.573 ;
     RECT  40.512 12.851 41.712 14.053 ;
     RECT  8.112 12.901 9.36 14.629 ;
     RECT  15 12.949 15.984 14.053 ;
     RECT  3.432 12.995 3.48 13.715 ;
     RECT  27.384 12.995 28.416 13.187 ;
     RECT  24.6 13.043 26.256 13.139 ;
     RECT  30.504 13.045 31.968 13.139 ;
     RECT  43.128 13.091 44.976 13.573 ;
     RECT  24.6 13.139 26.592 14.051 ;
     RECT  27 13.187 28.416 14.291 ;
     RECT  16.248 13.379 17.376 15.445 ;
     RECT  18.912 13.573 19.968 14.293 ;
     RECT  43.128 13.573 44.448 14.147 ;
     RECT  32.76 13.619 34.08 14.725 ;
     RECT  3.384 13.715 3.48 14.149 ;
     RECT  38.328 13.715 39.456 14.675 ;
     RECT  50.784 13.715 51 15.013 ;
     RECT  19.992 13.859 20.976 14.339 ;
     RECT  24.6 14.051 25.128 14.485 ;
     RECT  43.968 14.147 44.448 14.677 ;
     RECT  3.384 14.149 4.608 15.445 ;
     RECT  22.152 14.291 23.568 15.299 ;
     RECT  59.808 14.291 59.832 14.773 ;
     RECT  19.656 14.339 20.976 15.731 ;
     RECT  25.08 14.485 25.128 14.869 ;
     RECT  41.976 14.531 42.168 14.819 ;
     RECT  8.112 14.629 9.12 16.501 ;
     RECT  38.328 14.675 39.696 14.963 ;
     RECT  4.824 14.773 5.904 14.915 ;
     RECT  58.92 14.773 59.832 15.493 ;
     RECT  41.784 14.819 42.168 15.973 ;
     RECT  4.632 14.915 5.904 16.069 ;
     RECT  11.664 14.915 12.864 15.061 ;
     RECT  37.896 14.963 39.696 15.829 ;
     RECT  49.512 15.013 51 15.731 ;
     RECT  10.104 15.061 11.616 16.067 ;
     RECT  11.64 15.061 12.864 16.835 ;
     RECT  15 15.155 16.128 16.261 ;
     RECT  3.432 15.445 4.608 16.835 ;
     RECT  16.344 15.445 17.376 16.019 ;
     RECT  58.92 15.493 60.432 16.259 ;
     RECT  60.456 15.493 61.632 16.595 ;
     RECT  19.368 15.731 20.976 15.877 ;
     RECT  37.896 15.829 39.312 17.413 ;
     RECT  19.368 15.877 20.544 16.883 ;
     RECT  41.784 15.973 42.768 16.163 ;
     RECT  42.792 15.973 43.968 16.163 ;
     RECT  16.344 16.019 17.616 18.803 ;
     RECT  24.408 16.019 25.536 16.595 ;
     RECT  25.56 16.501 26.928 16.595 ;
     RECT  24.408 16.595 25.08 17.077 ;
     RECT  26.88 16.595 26.928 16.933 ;
     RECT  60.456 16.595 61.8 16.691 ;
     RECT  6.648 16.645 7.8 17.699 ;
     RECT  61.344 16.691 61.8 18.181 ;
     RECT  20.544 17.123 20.976 18.373 ;
     RECT  24.504 17.219 25.08 18.469 ;
     RECT  56.808 17.219 57 18.181 ;
     RECT  37.896 17.413 39.264 18.517 ;
     RECT  22.152 17.605 23.664 18.949 ;
     RECT  2.712 17.699 2.952 18.565 ;
     RECT  6.6 17.699 7.8 18.275 ;
     RECT  30.984 17.747 32.736 19.045 ;
     RECT  14.952 17.843 16.32 18.227 ;
     RECT  4.968 18.227 6.096 18.803 ;
     RECT  6.12 18.275 7.8 18.709 ;
     RECT  20.544 18.373 20.736 18.565 ;
     RECT  24.504 18.469 25.728 18.707 ;
     RECT  25.752 18.469 26.88 18.565 ;
     RECT  38.184 18.517 39.264 19.715 ;
     RECT  2.712 18.565 3.888 19.045 ;
     RECT  19.512 18.565 20.736 19.381 ;
     RECT  6.12 18.709 7.152 18.803 ;
     RECT  4.968 18.803 5.16 19.669 ;
     RECT  40.512 18.899 41.712 20.437 ;
     RECT  2.712 19.045 3.84 21.445 ;
     RECT  7.152 19.379 7.8 20.485 ;
     RECT  19.512 19.381 20.496 20.485 ;
     RECT  33.816 19.427 34.8 20.869 ;
     RECT  61.344 19.523 61.8 21.013 ;
     RECT  22.776 19.571 23.904 21.061 ;
     RECT  42.648 19.813 43.968 19.957 ;
     RECT  49.8 20.485 50.88 21.155 ;
     RECT  12.528 20.867 13.2 21.397 ;
     RECT  39.408 20.963 39.456 22.357 ;
     RECT  59.256 21.013 60.384 21.107 ;
     RECT  60.408 21.013 61.8 21.683 ;
     RECT  22.824 21.061 23.904 22.019 ;
     RECT  17.112 21.109 18.192 21.251 ;
     RECT  26.184 21.155 26.232 21.683 ;
     RECT  42.648 21.155 43.968 24.083 ;
     RECT  49.128 21.155 50.88 22.261 ;
     RECT  16.008 21.157 17.088 21.251 ;
     RECT  16.008 21.251 16.584 21.349 ;
     RECT  12.024 21.397 13.2 22.499 ;
     RECT  37.416 21.587 37.464 22.741 ;
     RECT  51.312 21.589 52.416 25.525 ;
     RECT  24.696 21.637 26.064 23.605 ;
     RECT  26.088 21.683 26.232 22.021 ;
     RECT  19.512 21.731 20.736 22.307 ;
     RECT  62.112 21.971 63.12 24.707 ;
     RECT  22.776 22.019 23.904 22.499 ;
     RECT  26.088 22.021 27.648 22.645 ;
     RECT  52.968 22.069 54.24 23.459 ;
     RECT  5.352 22.165 6.864 22.259 ;
     RECT  49.128 22.261 50.112 22.307 ;
     RECT  19.368 22.307 20.736 22.739 ;
     RECT  49.104 22.307 50.112 22.789 ;
     RECT  22.776 22.499 24 23.893 ;
     RECT  40.512 22.643 41.568 23.605 ;
     RECT  26.472 22.645 27.648 24.085 ;
     RECT  33.816 22.787 34.8 34.741 ;
     RECT  48.696 22.789 50.112 24.181 ;
     RECT  14.568 23.173 15.984 24.469 ;
     RECT  6.864 23.315 7.44 23.845 ;
     RECT  52.536 23.459 54.24 24.469 ;
     RECT  37.464 23.509 38.736 23.699 ;
     RECT  18.192 23.555 18.6 24.613 ;
     RECT  24.696 23.605 26.016 24.325 ;
     RECT  40.512 23.605 41.52 23.797 ;
     RECT  37.464 23.699 39.168 24.709 ;
     RECT  5.928 23.845 7.44 25.619 ;
     RECT  20.736 23.891 21.6 23.939 ;
     RECT  22.776 23.893 23.904 24.899 ;
     RECT  20.736 23.939 21.792 24.469 ;
     RECT  16.008 23.987 16.584 24.613 ;
     RECT  43.92 24.083 43.968 24.805 ;
     RECT  48.984 24.181 50.112 24.227 ;
     RECT  60.264 24.181 61.536 25.043 ;
     RECT  48.984 24.227 49.224 25.285 ;
     RECT  19.032 24.469 20.496 26.099 ;
     RECT  20.52 24.469 21.792 25.139 ;
     RECT  52.536 24.469 53.52 24.947 ;
     RECT  16.008 24.613 17.52 29.075 ;
     RECT  17.544 24.613 18.6 29.317 ;
     RECT  37.464 24.709 38.736 26.437 ;
     RECT  22.776 24.899 24 25.187 ;
     RECT  52.44 24.947 53.52 25.667 ;
     RECT  61.68 25.043 61.8 26.533 ;
     RECT  20.52 25.139 21.984 25.285 ;
     RECT  22.728 25.187 24 26.003 ;
     RECT  20.616 25.285 21.984 26.099 ;
     RECT  40.512 25.475 41.568 29.605 ;
     RECT  51.432 25.525 52.416 26.197 ;
     RECT  14.616 25.571 15.984 27.683 ;
     RECT  5.688 25.619 7.44 25.715 ;
     RECT  11.496 25.621 12.528 26.149 ;
     RECT  5.208 25.715 7.44 26.773 ;
     RECT  23.904 26.003 24 26.245 ;
     RECT  19.032 26.099 21.984 26.341 ;
     RECT  11.496 26.149 12.48 26.483 ;
     RECT  26.328 26.243 27.408 26.483 ;
     RECT  19.032 26.341 20.304 26.869 ;
     RECT  20.328 26.341 21.984 27.445 ;
     RECT  23.904 26.435 24 27.541 ;
     RECT  11.568 26.483 12.48 27.301 ;
     RECT  26.04 26.483 27.408 26.579 ;
     RECT  26.04 26.579 27.552 28.309 ;
     RECT  5.208 26.773 6.528 27.013 ;
     RECT  19.08 26.869 20.304 28.451 ;
     RECT  49.224 27.347 49.416 27.445 ;
     RECT  30.072 27.395 31.104 28.115 ;
     RECT  38.232 27.443 39.552 27.875 ;
     RECT  20.568 27.445 21.984 28.163 ;
     RECT  49.224 27.445 50.688 27.877 ;
     RECT  51.312 27.491 52.32 28.981 ;
     RECT  22.824 27.541 24 27.877 ;
     RECT  14.568 27.683 15.984 28.741 ;
     RECT  2.712 27.827 3.744 29.509 ;
     RECT  37.464 27.875 37.512 28.933 ;
     RECT  49.224 27.877 50.544 29.747 ;
     RECT  56.712 27.923 57.984 28.691 ;
     RECT  29.976 28.115 31.104 29.699 ;
     RECT  5.688 28.163 7.488 29.605 ;
     RECT  26.184 28.309 27.552 28.451 ;
     RECT  4.632 28.451 5.664 29.845 ;
     RECT  18.912 28.451 20.304 30.133 ;
     RECT  26.04 28.451 27.552 28.739 ;
     RECT  22.008 28.643 23.04 29.219 ;
     RECT  56.712 28.691 58.008 28.885 ;
     RECT  14.568 28.741 15.696 30.803 ;
     RECT  56.712 28.885 58.128 29.171 ;
     RECT  15.72 29.075 17.52 30.133 ;
     RECT  2.712 29.509 3.696 29.605 ;
     RECT  5.688 29.605 6.864 31.475 ;
     RECT  29.976 29.699 31.128 30.085 ;
     RECT  49.224 29.747 50.592 31.235 ;
     RECT  9.864 30.085 10.992 31.285 ;
     RECT  20.472 30.085 21.984 30.949 ;
     RECT  29.976 30.085 31.008 33.541 ;
     RECT  31.032 30.085 31.128 31.141 ;
     RECT  19.032 30.133 20.304 30.709 ;
     RECT  39.552 30.179 39.696 31.141 ;
     RECT  3.72 30.611 4.704 32.147 ;
     RECT  14.424 30.803 15.696 31.525 ;
     RECT  20.808 30.949 21.984 32.627 ;
     RECT  51.312 30.995 52.32 31.955 ;
     RECT  31.848 31.141 32.88 33.013 ;
     RECT  38.328 31.141 39.696 31.237 ;
     RECT  49.224 31.235 50.736 33.107 ;
     RECT  60.024 31.237 61.152 31.955 ;
     RECT  43.992 31.285 45.504 32.051 ;
     RECT  40.512 31.427 41.712 32.437 ;
     RECT  14.424 31.525 15.504 33.107 ;
     RECT  28.2 31.667 29.4 33.013 ;
     RECT  46.104 31.765 47.328 31.955 ;
     RECT  47.352 31.765 48.72 31.955 ;
     RECT  58.68 31.861 60 31.955 ;
     RECT  8.232 31.955 9.216 33.109 ;
     RECT  3.432 32.147 4.704 33.875 ;
     RECT  17.208 32.195 18.288 33.347 ;
     RECT  15.912 32.771 17.088 33.155 ;
     RECT  13.992 33.107 15.504 33.395 ;
     RECT  40.512 33.107 41.712 40.165 ;
     RECT  45.912 33.107 46.104 34.165 ;
     RECT  15.912 33.155 17.184 33.347 ;
     RECT  22.776 33.301 24 37.429 ;
     RECT  18.24 33.347 18.288 34.645 ;
     RECT  28.2 33.635 29.4 40.021 ;
     RECT  3.336 33.875 4.704 34.933 ;
     RECT  31.56 33.923 32.688 34.883 ;
     RECT  44.328 34.261 45.6 35.173 ;
     RECT  37.464 34.355 37.656 34.835 ;
     RECT  20.472 34.549 21.648 34.645 ;
     RECT  21.672 34.549 22.752 35.939 ;
     RECT  20.568 34.645 21.648 35.363 ;
     RECT  26.76 34.741 27.936 34.835 ;
     RECT  52.968 34.741 53.952 35.843 ;
     RECT  26.76 34.835 27.984 35.603 ;
     RECT  37.416 34.835 37.656 35.845 ;
     RECT  31.032 34.883 32.688 35.315 ;
     RECT  3.72 34.933 4.704 36.083 ;
     RECT  46.536 35.077 47.712 35.749 ;
     RECT  47.736 35.077 48.72 36.565 ;
     RECT  32.448 35.315 32.688 35.845 ;
     RECT  44.472 35.315 45.6 35.555 ;
     RECT  56.304 35.363 56.4 36.517 ;
     RECT  6.768 35.507 7.152 36.469 ;
     RECT  13.104 35.507 13.2 36.901 ;
     RECT  26.76 35.603 28.128 38.147 ;
     RECT  8.28 35.747 9.6 38.243 ;
     RECT  46.536 35.749 47.616 38.819 ;
     RECT  15.912 35.845 17.28 36.229 ;
     RECT  37.416 35.845 38.784 37.715 ;
     RECT  17.304 35.939 18.288 37.091 ;
     RECT  21.648 35.939 22.752 36.901 ;
     RECT  3.48 36.083 4.704 39.395 ;
     RECT  16.296 36.229 17.28 36.949 ;
     RECT  5.736 36.469 7.152 37.667 ;
     RECT  33.816 36.515 34.8 40.357 ;
     RECT  49.224 36.565 50.736 37.475 ;
     RECT  21.648 36.901 22.08 37.093 ;
     RECT  13.512 37.091 13.752 37.333 ;
     RECT  17.208 37.091 18.288 37.187 ;
     RECT  19.944 37.093 21.024 37.381 ;
     RECT  15.912 37.139 17.184 37.187 ;
     RECT  18 37.187 18.288 38.149 ;
     RECT  13.512 37.333 14.736 39.877 ;
     RECT  20.904 37.427 22.08 39.109 ;
     RECT  22.824 37.429 24 38.533 ;
     RECT  49.224 37.475 50.832 38.677 ;
     RECT  10.344 37.715 10.44 38.243 ;
     RECT  26.376 38.147 28.128 39.203 ;
     RECT  9.864 38.243 10.44 38.725 ;
     RECT  22.968 38.533 24 39.829 ;
     RECT  39.552 38.675 40.2 39.733 ;
     RECT  49.224 38.677 50.208 39.491 ;
     RECT  9.864 38.725 10.848 41.557 ;
     RECT  46.248 38.819 47.616 39.875 ;
     RECT  26.184 39.203 28.128 39.205 ;
     RECT  26.184 39.205 27.408 41.075 ;
     RECT  62.112 39.301 63.12 40.835 ;
     RECT  49.224 39.491 50.832 40.261 ;
     RECT  13.104 39.587 13.2 40.693 ;
     RECT  37.416 39.733 38.928 42.037 ;
     RECT  38.952 39.733 40.2 43.187 ;
     RECT  46.152 39.875 47.616 40.597 ;
     RECT  28.2 40.021 29.184 40.693 ;
     RECT  40.512 40.165 41.664 40.501 ;
     RECT  49.56 40.261 50.832 40.835 ;
     RECT  60.36 40.405 61.68 41.267 ;
     RECT  56.808 40.451 56.856 41.893 ;
     RECT  47.88 40.499 49.2 41.795 ;
     RECT  40.512 40.501 41.616 41.075 ;
     RECT  8.232 40.595 8.28 42.037 ;
     RECT  46.152 40.597 47.376 40.643 ;
     RECT  46.008 40.643 47.376 41.219 ;
     RECT  30.888 40.741 31.968 40.837 ;
     RECT  49.224 40.835 50.832 40.981 ;
     RECT  3.72 40.981 4.704 41.651 ;
     RECT  49.224 40.981 50.736 48.997 ;
     RECT  2.712 41.027 3.696 41.651 ;
     RECT  27.312 41.075 27.408 41.509 ;
     RECT  40.512 41.075 41.664 42.181 ;
     RECT  55.32 41.125 56.4 42.755 ;
     RECT  60.528 41.267 61.68 41.939 ;
     RECT  2.712 41.651 2.808 42.709 ;
     RECT  20.904 41.651 22.176 42.803 ;
     RECT  30.888 41.651 31.968 43.237 ;
     RECT  47.784 41.795 49.2 44.197 ;
     RECT  57.288 41.893 58.464 42.709 ;
     RECT  60.528 41.939 61.8 42.181 ;
     RECT  33.816 42.035 34.8 50.149 ;
     RECT  8.52 42.037 9.84 42.563 ;
     RECT  37.512 42.037 38.928 43.141 ;
     RECT  60.552 42.181 61.8 43.523 ;
     RECT  10.344 42.755 10.872 43.813 ;
     RECT  57.288 42.851 58.464 47.939 ;
     RECT  25.704 42.997 26.88 43.093 ;
     RECT  37.512 43.141 38.784 43.235 ;
     RECT  38.808 43.187 40.2 45.301 ;
     RECT  37.416 43.235 38.784 47.027 ;
     RECT  30.168 43.283 31.152 47.317 ;
     RECT  32.088 43.283 33.12 51.107 ;
     RECT  3.384 43.333 4.704 44.915 ;
     RECT  26.904 43.571 28.128 44.965 ;
     RECT  22.44 43.715 23.472 44.483 ;
     RECT  15.864 43.811 16.008 43.955 ;
     RECT  10.344 43.813 11.712 44.389 ;
     RECT  11.736 43.813 13.2 45.973 ;
     RECT  15.432 43.955 16.008 45.301 ;
     RECT  28.296 43.955 29.4 45.013 ;
     RECT  47.88 44.197 49.2 46.501 ;
     RECT  10.344 44.389 11.424 47.269 ;
     RECT  18.912 44.483 19.92 45.059 ;
     RECT  22.2 44.483 23.472 44.723 ;
     RECT  26.952 44.965 28.128 45.589 ;
     RECT  28.392 45.013 29.4 45.445 ;
     RECT  18.912 45.059 20.064 52.885 ;
     RECT  38.808 45.301 40.08 45.589 ;
     RECT  20.376 45.493 21.696 45.589 ;
     RECT  20.712 45.589 21.696 46.787 ;
     RECT  27.096 45.589 28.128 46.645 ;
     RECT  11.736 45.973 13.104 47.315 ;
     RECT  25.992 46.211 27.072 48.421 ;
     RECT  38.808 46.211 40.08 47.027 ;
     RECT  8.616 46.787 9.84 48.659 ;
     RECT  21.96 46.789 23.472 48.275 ;
     RECT  37.416 47.027 40.08 47.461 ;
     RECT  11.736 47.315 13.2 50.917 ;
     RECT  13.512 47.363 14.472 48.229 ;
     RECT  37.416 47.461 38.736 48.515 ;
     RECT  38.76 47.461 40.08 48.467 ;
     RECT  27.096 47.603 28.128 50.963 ;
     RECT  57.288 47.939 58.656 48.131 ;
     RECT  13.512 48.229 15.024 48.947 ;
     RECT  47.928 48.275 49.2 49.429 ;
     RECT  42.36 48.421 43.728 50.149 ;
     RECT  38.76 48.467 40.2 48.659 ;
     RECT  30.168 48.659 31.68 49.043 ;
     RECT  46.008 48.709 47.328 49.091 ;
     RECT  13.512 48.947 13.8 50.005 ;
     RECT  43.752 48.947 45.264 50.293 ;
     RECT  49.656 48.997 50.736 50.819 ;
     RECT  25.992 49.091 27.072 50.963 ;
     RECT  45.912 49.091 47.328 49.619 ;
     RECT  53.4 49.091 54.168 50.101 ;
     RECT  45.912 49.619 47.616 50.149 ;
     RECT  24.456 49.811 25.968 51.253 ;
     RECT  6.432 50.051 6.768 51.253 ;
     RECT  46.2 50.149 47.616 50.675 ;
     RECT  43.752 50.293 45.168 50.389 ;
     RECT  43.752 50.389 45.072 50.437 ;
     RECT  43.752 50.437 44.832 51.347 ;
     RECT  57.288 50.437 58.32 50.677 ;
     RECT  47.736 50.579 49.2 50.771 ;
     RECT  45.912 50.675 47.616 51.253 ;
     RECT  21.672 50.677 22.8 51.923 ;
     RECT  33.624 50.819 34.8 55.717 ;
     RECT  11.976 50.917 13.2 51.347 ;
     RECT  59.304 50.965 60.816 51.347 ;
     RECT  59.232 51.011 59.28 52.165 ;
     RECT  32.064 51.107 33.12 51.253 ;
     RECT  2.712 51.253 3.984 52.499 ;
     RECT  5.4 51.253 6.768 55.237 ;
     RECT  24.456 51.253 25.68 51.923 ;
     RECT  30.12 51.253 31.392 52.499 ;
     RECT  31.416 51.253 33.12 52.213 ;
     RECT  45.912 51.253 47.328 52.211 ;
     RECT  11.736 51.347 13.2 52.405 ;
     RECT  43.752 51.347 44.976 52.595 ;
     RECT  22.56 51.923 22.8 52.981 ;
     RECT  24.312 51.923 25.68 54.035 ;
     RECT  31.416 52.213 32.976 52.309 ;
     RECT  11.736 52.405 12.768 56.531 ;
     RECT  29.88 52.499 31.392 52.595 ;
     RECT  43.752 52.595 45.504 53.557 ;
     RECT  18.912 52.885 19.92 52.981 ;
     RECT  42.552 53.027 43.728 54.709 ;
     RECT  32.184 53.219 33.168 54.373 ;
     RECT  8.112 53.461 9.12 54.179 ;
     RECT  43.752 53.557 45.408 54.037 ;
     RECT  22.584 53.603 24 57.013 ;
     RECT  54.696 53.797 55.824 53.843 ;
     RECT  59.592 53.797 60.912 54.419 ;
     RECT  29.712 53.843 29.832 55.141 ;
     RECT  54.312 53.843 55.824 55.043 ;
     RECT  24.312 54.035 25.968 54.421 ;
     RECT  20.568 54.037 22.032 54.803 ;
     RECT  43.944 54.037 45.408 54.755 ;
     RECT  47.64 54.083 48.216 55.525 ;
     RECT  24.648 54.421 25.968 57.109 ;
     RECT  42.744 54.709 43.728 54.947 ;
     RECT  32.184 54.755 33.168 54.947 ;
     RECT  43.896 54.755 45.408 54.899 ;
     RECT  32.184 54.947 33.312 56.867 ;
     RECT  42.552 54.947 43.728 55.957 ;
     RECT  5.4 55.237 6.672 56.195 ;
     RECT  54.144 55.331 54.192 56.435 ;
     RECT  33.624 55.717 34.704 55.859 ;
     RECT  33.48 55.859 34.704 57.059 ;
     RECT  42.744 55.957 43.728 59.605 ;
     RECT  18.912 56.099 19.92 59.219 ;
     RECT  40.776 56.149 41.952 56.195 ;
     RECT  5.256 56.195 6.672 56.819 ;
     RECT  40.512 56.195 41.952 57.059 ;
     RECT  54.144 56.435 54.288 56.725 ;
     RECT  25.992 56.437 27.504 57.059 ;
     RECT  11.736 56.531 13.2 58.501 ;
     RECT  53.304 56.725 54.288 59.219 ;
     RECT  5.256 56.819 6.768 57.973 ;
     RECT  36.072 56.915 37.392 57.875 ;
     RECT  22.824 57.013 24 61.429 ;
     RECT  33.48 57.059 34.8 58.069 ;
     RECT  8.112 57.301 9.456 58.645 ;
     RECT  24.936 57.395 25.968 58.163 ;
     RECT  51.912 57.589 53.28 59.077 ;
     RECT  59.616 57.635 59.76 57.829 ;
     RECT  58.632 57.829 59.76 58.115 ;
     RECT  5.256 57.973 6.432 58.739 ;
     RECT  33.576 58.069 34.8 64.741 ;
     RECT  58.632 58.115 59.256 59.605 ;
     RECT  24.936 58.163 25.992 58.355 ;
     RECT  24.312 58.355 25.992 58.597 ;
     RECT  2.712 58.357 3.888 58.883 ;
     RECT  3.912 58.357 5.232 58.739 ;
     RECT  11.736 58.501 13.104 60.373 ;
     RECT  24.312 58.597 27.408 59.221 ;
     RECT  8.328 58.645 9.456 59.315 ;
     RECT  3.912 58.739 4.68 58.883 ;
     RECT  2.712 58.883 2.904 59.797 ;
     RECT  4.656 58.883 4.68 60.181 ;
     RECT  52.2 59.077 53.28 59.701 ;
     RECT  33.312 59.171 33.552 60.421 ;
     RECT  53.304 59.219 54.384 61.043 ;
     RECT  24.312 59.221 25.968 59.557 ;
     RECT  25.992 59.221 27.408 60.563 ;
     RECT  8.328 59.315 9.84 60.035 ;
     RECT  38.712 59.365 40.08 59.891 ;
     RECT  24.312 59.557 25.44 60.949 ;
     RECT  55.032 59.605 56.4 61.043 ;
     RECT  52.2 59.843 53.28 60.371 ;
     RECT  38.712 59.891 40.2 61.619 ;
     RECT  36.072 59.893 37.536 62.101 ;
     RECT  37.56 59.893 38.688 61.619 ;
     RECT  42.528 59.987 43.056 59.989 ;
     RECT  40.512 59.989 41.952 61.859 ;
     RECT  41.976 59.989 43.056 61.043 ;
     RECT  9.696 60.035 9.84 60.709 ;
     RECT  10.392 60.275 11.424 62.195 ;
     RECT  32.52 60.421 33.552 62.195 ;
     RECT  27.12 60.563 27.408 60.611 ;
     RECT  27.12 60.611 27.144 60.949 ;
     RECT  18.912 60.805 19.92 62.723 ;
     RECT  12.216 61.379 13.2 62.723 ;
     RECT  22.824 61.429 23.808 61.765 ;
     RECT  19.944 61.573 21.12 62.677 ;
     RECT  5.064 61.621 6.528 62.771 ;
     RECT  56.712 61.667 56.856 62.773 ;
     RECT  40.512 61.859 40.68 62.965 ;
     RECT  24.312 61.955 25.44 64.931 ;
     RECT  36.072 62.101 37.056 62.771 ;
     RECT  20.088 62.677 21.12 62.965 ;
     RECT  42.696 62.677 43.728 62.819 ;
     RECT  11.736 62.723 13.2 64.933 ;
     RECT  18.912 62.723 20.064 64.115 ;
     RECT  29.712 62.723 30.816 63.779 ;
     RECT  43.392 62.819 43.728 62.821 ;
     RECT  13.848 62.821 15.024 63.827 ;
     RECT  37.56 63.205 38.688 65.459 ;
     RECT  38.712 63.205 40.2 65.459 ;
     RECT  22.872 63.347 24 63.491 ;
     RECT  22.824 63.491 24 63.923 ;
     RECT  27.912 63.877 29.28 64.355 ;
     RECT  18.912 64.115 19.368 64.357 ;
     RECT  17.544 64.211 18.6 65.603 ;
     RECT  32.52 64.261 33.552 64.931 ;
     RECT  25.464 64.357 26.496 64.931 ;
     RECT  33.576 64.741 34.656 64.931 ;
     RECT  51.432 64.885 52.848 65.411 ;
     RECT  24.312 64.931 26.496 64.933 ;
     RECT  11.736 64.933 12.72 65.027 ;
     RECT  25.08 64.933 26.496 65.171 ;
  END
END hidx_meta_w25_d123_r0
END LIBRARY
